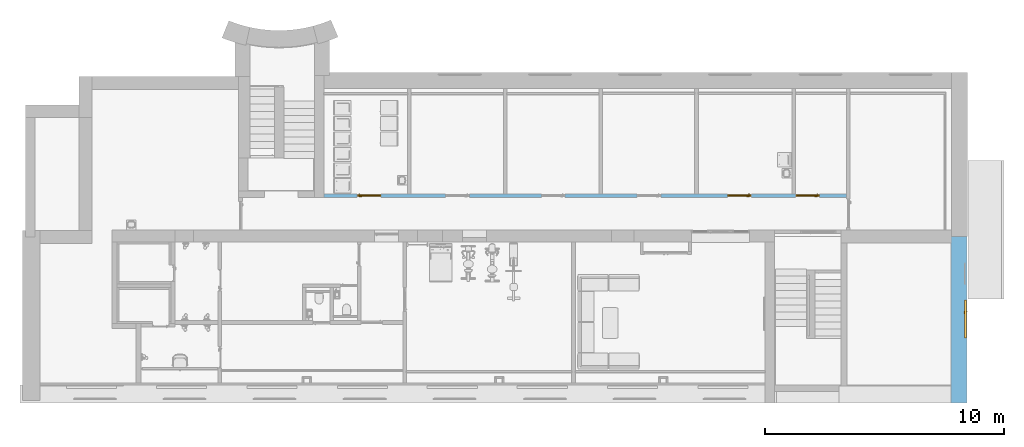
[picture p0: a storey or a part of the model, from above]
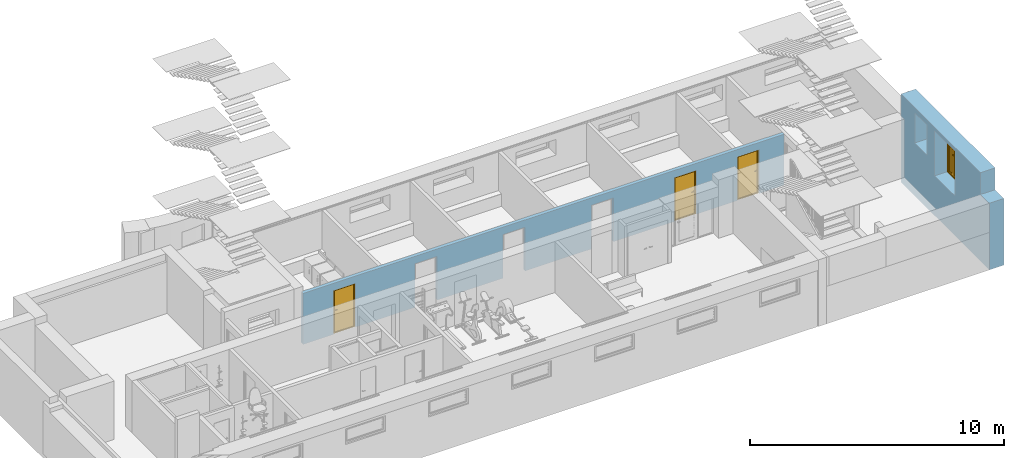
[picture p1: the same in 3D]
Properties of the parts of a building model (IFC2X3), part 1 of 4

# File
Description: ViewDefinition [CoordinationView_V2.0]
File name: 19080
Time: 2020-03-24T19:36:21
Written by: The EXPRESS Data Manager Version 5.02.0100.07 : 28 Aug 2013
Made in: 20180806_1515(x64) - Exporter 19.3.0.0 - Alternate UI 19.3.0.0
Comment: STEP Physical File produced by: The EXPRESS Data Manager Version 5.02.0100.07 : 28 Aug 2013 * Module: EDMstepFileFactory/EDMstandAlone * Creation date: Tue Mar 24 19:36:21 2020 * Host: SA-28 * Database: C:\Users\Evely\AppData\Local\Temp\{456B217A-5B38-47CA-B494-E4B1A39EF6CF}\ifc * Database version: 5507 * Database creation date: Tue Mar 24 19:32:30 2020 * Schema: IFC2X3 * Model: DataRepository.ifc * Model creation date: Tue Mar 24 19:32:31 2020 * Header model: DataRepository.ifc_HeaderModel * Header model creation date: Tue Mar 24 19:32:31 2020 * EDMuser: sdai-user * EDMgroup: sdai-group * License ID and type: 5605 : Permanent license. Expiry date: * EDMstepFileFactory options: 020000

# IfcProject, 19080
LongName: Tulika 37 rekonstrueerimine; Phase: TP

# IfcSite, Default
RefLatitude: 59, 26, 11, 113586; RefLongitude: 24, 45, 9, 290313; RefElevation: 0 mm
Pset_ProductRequirements - Category: Project Information

# IfcBuilding, SMA ARH
LongName: SMA ARH
Pset_BuildingCommon - NumberOfStoreys: 7
Pset_ProductRequirements - Category: Project Information

# IfcBuildingStorey: Level:Level head 1 (7)
In: SMA ARH
Pset_ProductRequirements - Category: Levels
Name | LongName = Pset_AirSideSystemInformation, Name = Pset_ProductRequirements, Name | Elevation (mm)
0 Sokkel | 0 Sokkel | -2800
Sissepääs | Sissepääs | -1270
1 Korrus | 1 Korrus | 0
2 Korrus | 2 Korrus | 3300
3 Korrus | 3 Korrus | 6600
4 Korrus | 4 Korrus | 9910
Katus | Katus | 13000

# IfcSpace: Abiruum 0-28:1304011, 0-28
In: 0 Sokkel
LongName: Abiruum; InteriorOrExteriorSpace: INTERNAL
Pset_AirSideSystemInformation - Name: Abiruum; sets with these values: 2
Pset_SpaceCommon - Reference: Abiruum 0-28

# IfcSpace: Abiruum 0-30:1328334, 0-30
In: 0 Sokkel
LongName: Abiruum; InteriorOrExteriorSpace: INTERNAL
Pset_AirSideSystemInformation - Name: Abiruum; sets with these values: 2
Pset_SpaceCommon - Reference: Abiruum 0-30

# IfcSpace: Administraator 1-1:847130, 1-1
In: 1 Korrus
LongName: Administraator; InteriorOrExteriorSpace: INTERNAL
Pset_AirSideSystemInformation - Name: Administraator; sets with these values: 2
Pset_SpaceCommon - Reference: Administraator 1-1

# IfcSpace: El.kilbiruum 0-21:888839, 0-21
In: 0 Sokkel
LongName: El.kilbiruum; InteriorOrExteriorSpace: INTERNAL
Pset_AirSideSystemInformation - Name: El.kilbiruum; sets with these values: 2
Pset_SpaceCommon - Reference: El.kilbiruum 0-21

# IfcSpace: El.kilp 0-29:1313636, 0-29
In: 0 Sokkel
LongName: El.kilp; InteriorOrExteriorSpace: INTERNAL
Pset_AirSideSystemInformation - Name: El.kilp; sets with these values: 2
Pset_SpaceCommon - Reference: El.kilp 0-29

# IfcSpace: Esik 1-10:847145, 1-10
In: 1 Korrus
LongName: Esik; InteriorOrExteriorSpace: INTERNAL
Pset_AirSideSystemInformation - Name: Esik; sets with these values: 2
Pset_SpaceCommon - Reference: Esik 1-10

# IfcSpace: Esik 1-16:847163, 1-16
In: 1 Korrus
LongName: Esik; InteriorOrExteriorSpace: INTERNAL
Pset_AirSideSystemInformation - Name: Esik; sets with these values: 2
Pset_SpaceCommon - Reference: Esik 1-16

# IfcSpace: Esik 1-18:847178, 1-18
In: 1 Korrus
LongName: Esik; InteriorOrExteriorSpace: INTERNAL
Pset_AirSideSystemInformation - Name: Esik; sets with these values: 2
Pset_SpaceCommon - Reference: Esik 1-18

# IfcSpace: Esik 1-25:847196, 1-25
In: 1 Korrus
LongName: Esik; InteriorOrExteriorSpace: INTERNAL
Pset_AirSideSystemInformation - Name: Esik; sets with these values: 2
Pset_SpaceCommon - Reference: Esik 1-25

# IfcSpace: Esik 1-28:847211, 1-28
In: 1 Korrus
LongName: Esik; InteriorOrExteriorSpace: INTERNAL
Pset_AirSideSystemInformation - Name: Esik; sets with these values: 2
Pset_SpaceCommon - Reference: Esik 1-28

# IfcSpace: Esik 1-32:847223, 1-32
In: 1 Korrus
LongName: Esik; InteriorOrExteriorSpace: INTERNAL
Pset_AirSideSystemInformation - Name: Esik; sets with these values: 2
Pset_SpaceCommon - Reference: Esik 1-32

# IfcSpace: Esik 2-10:856734, 2-10
In: 2 Korrus
LongName: Esik; InteriorOrExteriorSpace: INTERNAL
Pset_AirSideSystemInformation - Name: Esik; sets with these values: 2
Pset_SpaceCommon - Reference: Esik 2-10

# IfcSpace: Esik 2-16:856764, 2-16
In: 2 Korrus
LongName: Esik; InteriorOrExteriorSpace: INTERNAL
Pset_AirSideSystemInformation - Name: Esik; sets with these values: 2
Pset_SpaceCommon - Reference: Esik 2-16

# IfcSpace: Esik 2-18:856779, 2-18
In: 2 Korrus
LongName: Esik; InteriorOrExteriorSpace: INTERNAL
Pset_AirSideSystemInformation - Name: Esik; sets with these values: 2
Pset_SpaceCommon - Reference: Esik 2-18

# IfcSpace: Esik 2-25:856797, 2-25
In: 2 Korrus
LongName: Esik; InteriorOrExteriorSpace: INTERNAL
Pset_AirSideSystemInformation - Name: Esik; sets with these values: 2
Pset_SpaceCommon - Reference: Esik 2-25

# IfcSpace: Esik 2-28:856812, 2-28
In: 2 Korrus
LongName: Esik; InteriorOrExteriorSpace: INTERNAL
Pset_AirSideSystemInformation - Name: Esik; sets with these values: 2
Pset_SpaceCommon - Reference: Esik 2-28

# IfcSpace: Esik 2-3:856827, 2-3
In: 2 Korrus
LongName: Esik; InteriorOrExteriorSpace: INTERNAL
Pset_AirSideSystemInformation - Name: Esik; sets with these values: 2
Pset_SpaceCommon - Reference: Esik 2-3

# IfcSpace: Esik 3-10:867600, 3-10
In: 3 Korrus
LongName: Esik; InteriorOrExteriorSpace: INTERNAL
Pset_AirSideSystemInformation - Name: Esik; sets with these values: 2
Pset_SpaceCommon - Reference: Esik 3-10

# IfcSpace: Esik 3-16:867627, 3-16
In: 3 Korrus
LongName: Esik; InteriorOrExteriorSpace: INTERNAL
Pset_AirSideSystemInformation - Name: Esik; sets with these values: 2
Pset_SpaceCommon - Reference: Esik 3-16

# IfcSpace: Esik 3-18:867639, 3-18
In: 3 Korrus
LongName: Esik; InteriorOrExteriorSpace: INTERNAL
Pset_AirSideSystemInformation - Name: Esik; sets with these values: 2
Pset_SpaceCommon - Reference: Esik 3-18

# IfcSpace: Esik 3-25:867688, 3-25
In: 3 Korrus
LongName: Esik; InteriorOrExteriorSpace: INTERNAL
Pset_AirSideSystemInformation - Name: Esik; sets with these values: 2
Pset_SpaceCommon - Reference: Esik 3-25

# IfcSpace: Esik 3-28:867691, 3-28
In: 3 Korrus
LongName: Esik; InteriorOrExteriorSpace: INTERNAL
Pset_AirSideSystemInformation - Name: Esik; sets with these values: 2
Pset_SpaceCommon - Reference: Esik 3-28

# IfcSpace: Esik 3-3:867551, 3-3
In: 3 Korrus
LongName: Esik; InteriorOrExteriorSpace: INTERNAL
Pset_AirSideSystemInformation - Name: Esik; sets with these values: 2
Pset_SpaceCommon - Reference: Esik 3-3

# IfcSpace: Esik 4-10:867950, 4-10
In: 4 Korrus
LongName: Esik; InteriorOrExteriorSpace: INTERNAL
Pset_AirSideSystemInformation - Name: Esik; sets with these values: 2
Pset_SpaceCommon - Reference: Esik 4-10

# IfcSpace: Esik 4-16:867977, 4-16
In: 4 Korrus
LongName: Esik; InteriorOrExteriorSpace: INTERNAL
Pset_AirSideSystemInformation - Name: Esik; sets with these values: 2
Pset_SpaceCommon - Reference: Esik 4-16

# IfcSpace: Esik 4-18:867989, 4-18
In: 4 Korrus
LongName: Esik; InteriorOrExteriorSpace: INTERNAL
Pset_AirSideSystemInformation - Name: Esik; sets with these values: 2
Pset_SpaceCommon - Reference: Esik 4-18

# IfcSpace: Esik 4-25:868047, 4-25
In: 4 Korrus
LongName: Esik; InteriorOrExteriorSpace: INTERNAL
Pset_AirSideSystemInformation - Name: Esik; sets with these values: 2
Pset_SpaceCommon - Reference: Esik 4-25

# IfcSpace: Esik 4-27:868059, 4-27
In: 4 Korrus
LongName: Esik; InteriorOrExteriorSpace: INTERNAL
Pset_AirSideSystemInformation - Name: Esik; sets with these values: 2
Pset_SpaceCommon - Reference: Esik 4-27

# IfcSpace: Esik 4-3:867819, 4-3
In: 4 Korrus
LongName: Esik; InteriorOrExteriorSpace: INTERNAL
Pset_AirSideSystemInformation - Name: Esik; sets with these values: 2
Pset_SpaceCommon - Reference: Esik 4-3

# IfcSpace: Fuajee 1-3:847124, 1-3
In: 1 Korrus
LongName: Fuajee; InteriorOrExteriorSpace: INTERNAL
Pset_AirSideSystemInformation - Name: Fuajee; sets with these values: 2
Pset_SpaceCommon - Reference: Fuajee 1-3

# IfcSpace: Jõusaal 0-3:888782, 0-3
In: 0 Sokkel
LongName: Jõusaal; InteriorOrExteriorSpace: INTERNAL
Pset_AirSideSystemInformation - Name: Jõusaal; sets with these values: 2
Pset_SpaceCommon - Reference: Jõusaal 0-3

# IfcSpace: Kor.v 0-20:888836, 0-20
In: 0 Sokkel
LongName: Kor.v; InteriorOrExteriorSpace: INTERNAL
Pset_AirSideSystemInformation - Name: Kor.v; sets with these values: 2
Pset_SpaceCommon - Reference: Kor.v 0-20

# IfcSpace: Kor.v 1-21:847190, 1-21
In: 1 Korrus
LongName: Kor.v; InteriorOrExteriorSpace: INTERNAL
Pset_AirSideSystemInformation - Name: Kor.v; sets with these values: 2
Pset_SpaceCommon - Reference: Kor.v 1-21

# IfcSpace: Kor.v 2-21:856791, 2-21
In: 2 Korrus
LongName: Kor.v; InteriorOrExteriorSpace: INTERNAL
Pset_AirSideSystemInformation - Name: Kor.v; sets with these values: 2
Pset_SpaceCommon - Reference: Kor.v 2-21

# IfcSpace: Kor.v 3-21:867657, 3-21
In: 3 Korrus
LongName: Kor.v; InteriorOrExteriorSpace: INTERNAL
Pset_AirSideSystemInformation - Name: Kor.v; sets with these values: 2
Pset_SpaceCommon - Reference: Kor.v 3-21

# IfcSpace: Kor.v 4-21:868010, 4-21
In: 4 Korrus
LongName: Kor.v; InteriorOrExteriorSpace: INTERNAL
Pset_AirSideSystemInformation - Name: Kor.v; sets with these values: 2
Pset_SpaceCommon - Reference: Kor.v 4-21

# IfcSpace: Koridor 0-1:887768, 0-1
In: 0 Sokkel
LongName: Koridor; InteriorOrExteriorSpace: INTERNAL
Pset_AirSideSystemInformation - Name: Koridor; sets with these values: 2
Pset_SpaceCommon - Reference: Koridor 0-1

# IfcSpace: Koridor 0-4:888785, 0-4
In: 0 Sokkel
LongName: Koridor; InteriorOrExteriorSpace: INTERNAL
Pset_AirSideSystemInformation - Name: Koridor; sets with these values: 2
Pset_SpaceCommon - Reference: Koridor 0-4

# IfcSpace: Koridor 1-5:847139, 1-5
In: 1 Korrus
LongName: Koridor; InteriorOrExteriorSpace: INTERNAL
Pset_AirSideSystemInformation - Name: Koridor; sets with these values: 2
Pset_SpaceCommon - Reference: Koridor 1-5

# IfcSpace: Koridor 2-5:856731, 2-5
In: 2 Korrus
LongName: Koridor; InteriorOrExteriorSpace: INTERNAL
Pset_AirSideSystemInformation - Name: Koridor; sets with these values: 2
Pset_SpaceCommon - Reference: Koridor 2-5

# IfcSpace: Koridor 3-5:867579, 3-5
In: 3 Korrus
LongName: Koridor; InteriorOrExteriorSpace: INTERNAL
Pset_AirSideSystemInformation - Name: Koridor; sets with these values: 2
Pset_SpaceCommon - Reference: Koridor 3-5

# IfcSpace: Koridor 4-5:867831, 4-5
In: 4 Korrus
LongName: Koridor; InteriorOrExteriorSpace: INTERNAL
Pset_AirSideSystemInformation - Name: Koridor; sets with these values: 2
Pset_SpaceCommon - Reference: Koridor 4-5

# IfcSpace: Ladu 0-19:888833, 0-19
In: 0 Sokkel
LongName: Ladu; InteriorOrExteriorSpace: INTERNAL
Pset_AirSideSystemInformation - Name: Ladu; sets with these values: 2
Pset_SpaceCommon - Reference: Ladu 0-19

# IfcSpace: Musta pesu ladu 0-17:888827, 0-17
In: 0 Sokkel
LongName: Musta pesu ladu; InteriorOrExteriorSpace: INTERNAL
Pset_AirSideSystemInformation - Name: Musta pesu ladu; sets with these values: 2
Pset_SpaceCommon - Reference: Musta pesu ladu 0-17

# IfcSpace: Pesemisruum 0-11:888809, 0-11
In: 0 Sokkel
LongName: Pesemisruum; InteriorOrExteriorSpace: INTERNAL
Pset_AirSideSystemInformation - Name: Pesemisruum; sets with these values: 2
Pset_SpaceCommon - Reference: Pesemisruum 0-11

# IfcSpace: Pesemisruum 0-8:888800, 0-8
In: 0 Sokkel
LongName: Pesemisruum; InteriorOrExteriorSpace: INTERNAL
Pset_AirSideSystemInformation - Name: Pesemisruum; sets with these values: 2
Pset_SpaceCommon - Reference: Pesemisruum 0-8

# IfcSpace: Pesupesemisruum 0-16:888824, 0-16
In: 0 Sokkel
LongName: Pesupesemisruum; InteriorOrExteriorSpace: INTERNAL
Pset_AirSideSystemInformation - Name: Pesupesemisruum; sets with these values: 2
Pset_SpaceCommon - Reference: Pesupesemisruum 0-16

# IfcSpace: Puhkeruum 0-2:888776, 0-2
In: 0 Sokkel
LongName: Puhkeruum; InteriorOrExteriorSpace: INTERNAL
Pset_AirSideSystemInformation - Name: Puhkeruum; sets with these values: 2
Pset_SpaceCommon - Reference: Puhkeruum 0-2

# IfcSpace: Puhta pesu ladu 0-18:888830, 0-18
In: 0 Sokkel
LongName: Puhta pesu ladu; InteriorOrExteriorSpace: INTERNAL
Pset_AirSideSystemInformation - Name: Puhta pesu ladu; sets with these values: 2
Pset_SpaceCommon - Reference: Puhta pesu ladu 0-18

# IfcSpace: Riietusruum 0-12:888812, 0-12
In: 0 Sokkel
LongName: Riietusruum; InteriorOrExteriorSpace: INTERNAL
Pset_AirSideSystemInformation - Name: Riietusruum; sets with these values: 2
Pset_SpaceCommon - Reference: Riietusruum 0-12

# IfcSpace: Riietusruum 0-7:888797, 0-7
In: 0 Sokkel
LongName: Riietusruum; InteriorOrExteriorSpace: INTERNAL
Pset_AirSideSystemInformation - Name: Riietusruum; sets with these values: 2
Pset_SpaceCommon - Reference: Riietusruum 0-7

# IfcSpace: Saun 0-10:888806, 0-10
In: 0 Sokkel
LongName: Saun; InteriorOrExteriorSpace: INTERNAL
Pset_AirSideSystemInformation - Name: Saun; sets with these values: 2
Pset_SpaceCommon - Reference: Saun 0-10

# IfcSpace: Saun 0-9:888803, 0-9
In: 0 Sokkel
LongName: Saun; InteriorOrExteriorSpace: INTERNAL
Pset_AirSideSystemInformation - Name: Saun; sets with these values: 2
Pset_SpaceCommon - Reference: Saun 0-9

# IfcSpace: Tehniline ruum 0-13:888815, 0-13
In: 0 Sokkel
LongName: Tehniline ruum; InteriorOrExteriorSpace: INTERNAL
Pset_AirSideSystemInformation - Name: Tehniline ruum; sets with these values: 2
Pset_SpaceCommon - Reference: Tehniline ruum 0-13

# IfcSpace: Tehniline ruum 0-14:888818, 0-14
In: 0 Sokkel
LongName: Tehniline ruum; InteriorOrExteriorSpace: INTERNAL
Pset_AirSideSystemInformation - Name: Tehniline ruum; sets with these values: 2
Pset_SpaceCommon - Reference: Tehniline ruum 0-14

# IfcSpace: Tehniline ruum 0-22:888842, 0-22
In: 0 Sokkel
LongName: Tehniline ruum; InteriorOrExteriorSpace: INTERNAL
Pset_AirSideSystemInformation - Name: Tehniline ruum; sets with these values: 2
Pset_SpaceCommon - Reference: Tehniline ruum 0-22

# IfcSpace: Trepikoda 1 0-23:888845, 0-23
In: 0 Sokkel
LongName: Trepikoda 1; InteriorOrExteriorSpace: INTERNAL
Pset_AirSideSystemInformation - Name: Trepikoda 1; sets with these values: 2
Pset_SpaceCommon - Reference: Trepikoda 1 0-23

# IfcSpace: Trepikoda 1 1-4:847127, 1-4
In: 1 Korrus
LongName: Trepikoda 1; InteriorOrExteriorSpace: INTERNAL
Pset_AirSideSystemInformation - Name: Trepikoda 1; sets with these values: 2
Pset_SpaceCommon - Reference: Trepikoda 1 1-4

# IfcSpace: Trepikoda 1 2-4:856693, 2-4
In: 2 Korrus
LongName: Trepikoda 1; InteriorOrExteriorSpace: INTERNAL
Pset_AirSideSystemInformation - Name: Trepikoda 1; sets with these values: 2
Pset_SpaceCommon - Reference: Trepikoda 1 2-4

# IfcSpace: Trepikoda 1 3-4:867554, 3-4
In: 3 Korrus
LongName: Trepikoda 1; InteriorOrExteriorSpace: INTERNAL
Pset_AirSideSystemInformation - Name: Trepikoda 1; sets with these values: 2
Pset_SpaceCommon - Reference: Trepikoda 1 3-4

# IfcSpace: Trepikoda 1 4-4:867825, 4-4
In: 4 Korrus
LongName: Trepikoda 1; InteriorOrExteriorSpace: INTERNAL
Pset_AirSideSystemInformation - Name: Trepikoda 1; sets with these values: 2
Pset_SpaceCommon - Reference: Trepikoda 1 4-4

# IfcSpace: Trepikoda 2 0-15:888821, 0-15
In: 0 Sokkel
LongName: Trepikoda 2; InteriorOrExteriorSpace: INTERNAL
Pset_AirSideSystemInformation - Name: Trepikoda 2; sets with these values: 2
Pset_SpaceCommon - Reference: Trepikoda 2 0-15

# IfcSpace: Trepikoda 2 1-35:847193, 1-35
In: 1 Korrus
LongName: Trepikoda 2; InteriorOrExteriorSpace: INTERNAL
Pset_AirSideSystemInformation - Name: Trepikoda 2; sets with these values: 2
Pset_SpaceCommon - Reference: Trepikoda 2 1-35

# IfcSpace: Trepikoda 2 2-32:856794, 2-32
In: 2 Korrus
LongName: Trepikoda 2; InteriorOrExteriorSpace: INTERNAL
Pset_AirSideSystemInformation - Name: Trepikoda 2; sets with these values: 2
Pset_SpaceCommon - Reference: Trepikoda 2 2-32

# IfcSpace: Trepikoda 2 3-32:867660, 3-32
In: 3 Korrus
LongName: Trepikoda 2; InteriorOrExteriorSpace: INTERNAL
Pset_AirSideSystemInformation - Name: Trepikoda 2; sets with these values: 2
Pset_SpaceCommon - Reference: Trepikoda 2 3-32

# IfcSpace: Trepikoda 2 4-32:868016, 4-32
In: 4 Korrus
LongName: Trepikoda 2; InteriorOrExteriorSpace: INTERNAL
Pset_AirSideSystemInformation - Name: Trepikoda 2; sets with these values: 2
Pset_SpaceCommon - Reference: Trepikoda 2 4-32

# IfcSpace: Tuba 1-12:847166, 1-12
In: 1 Korrus
LongName: Tuba; InteriorOrExteriorSpace: INTERNAL
Pset_AirSideSystemInformation - Name: Tuba; sets with these values: 2
Pset_SpaceCommon - Reference: Tuba 1-12

# IfcSpace: Tuba 1-13:847169, 1-13
In: 1 Korrus
LongName: Tuba; InteriorOrExteriorSpace: INTERNAL
Pset_AirSideSystemInformation - Name: Tuba; sets with these values: 2
Pset_SpaceCommon - Reference: Tuba 1-13

# IfcSpace: Tuba 1-14:847172, 1-14
In: 1 Korrus
LongName: Tuba; InteriorOrExteriorSpace: INTERNAL
Pset_AirSideSystemInformation - Name: Tuba; sets with these values: 2
Pset_SpaceCommon - Reference: Tuba 1-14

# IfcSpace: Tuba 1-15:847181, 1-15
In: 1 Korrus
LongName: Tuba; InteriorOrExteriorSpace: INTERNAL
Pset_AirSideSystemInformation - Name: Tuba; sets with these values: 2
Pset_SpaceCommon - Reference: Tuba 1-15

# IfcSpace: Tuba 1-20/1:847184, 1-20/1
In: 1 Korrus
LongName: Tuba; InteriorOrExteriorSpace: INTERNAL
Pset_AirSideSystemInformation - Name: Tuba; sets with these values: 2
Pset_SpaceCommon - Reference: Tuba 1-20/1

# IfcSpace: Tuba 1-20/2:858602, 1-20/2
In: 1 Korrus
LongName: Tuba; InteriorOrExteriorSpace: INTERNAL
Pset_AirSideSystemInformation - Name: Tuba; sets with these values: 2
Pset_SpaceCommon - Reference: Tuba 1-20/2

# IfcSpace: Tuba 1-22:847199, 1-22
In: 1 Korrus
LongName: Tuba; InteriorOrExteriorSpace: INTERNAL
Pset_AirSideSystemInformation - Name: Tuba; sets with these values: 2
Pset_SpaceCommon - Reference: Tuba 1-22

# IfcSpace: Tuba 1-23:847202, 1-23
In: 1 Korrus
LongName: Tuba; InteriorOrExteriorSpace: INTERNAL
Pset_AirSideSystemInformation - Name: Tuba; sets with these values: 2
Pset_SpaceCommon - Reference: Tuba 1-23

# IfcSpace: Tuba 1-24:847205, 1-24
In: 1 Korrus
LongName: Tuba; InteriorOrExteriorSpace: INTERNAL
Pset_AirSideSystemInformation - Name: Tuba; sets with these values: 2
Pset_SpaceCommon - Reference: Tuba 1-24

# IfcSpace: Tuba 1-29:847217, 1-29
In: 1 Korrus
LongName: Tuba; InteriorOrExteriorSpace: INTERNAL
Pset_AirSideSystemInformation - Name: Tuba; sets with these values: 2
Pset_SpaceCommon - Reference: Tuba 1-29

# IfcSpace: Tuba 1-30:847220, 1-30
In: 1 Korrus
LongName: Tuba; InteriorOrExteriorSpace: INTERNAL
Pset_AirSideSystemInformation - Name: Tuba; sets with these values: 2
Pset_SpaceCommon - Reference: Tuba 1-30

# IfcSpace: Tuba 1-31:847226, 1-31
In: 1 Korrus
LongName: Tuba; InteriorOrExteriorSpace: INTERNAL
Pset_AirSideSystemInformation - Name: Tuba; sets with these values: 2
Pset_SpaceCommon - Reference: Tuba 1-31

# IfcSpace: Tuba 1-33:847229, 1-33
In: 1 Korrus
LongName: Tuba; InteriorOrExteriorSpace: INTERNAL
Pset_AirSideSystemInformation - Name: Tuba; sets with these values: 2
Pset_SpaceCommon - Reference: Tuba 1-33

# IfcSpace: Tuba 1-6:847148, 1-6
In: 1 Korrus
LongName: Tuba; InteriorOrExteriorSpace: INTERNAL
Pset_AirSideSystemInformation - Name: Tuba; sets with these values: 2
Pset_SpaceCommon - Reference: Tuba 1-6

# IfcSpace: Tuba 1-7:847151, 1-7
In: 1 Korrus
LongName: Tuba; InteriorOrExteriorSpace: INTERNAL
Pset_AirSideSystemInformation - Name: Tuba; sets with these values: 2
Pset_SpaceCommon - Reference: Tuba 1-7

# IfcSpace: Tuba 1-8:847154, 1-8
In: 1 Korrus
LongName: Tuba; InteriorOrExteriorSpace: INTERNAL
Pset_AirSideSystemInformation - Name: Tuba; sets with these values: 2
Pset_SpaceCommon - Reference: Tuba 1-8

# IfcSpace: Tuba 1-9:847157, 1-9
In: 1 Korrus
LongName: Tuba; InteriorOrExteriorSpace: INTERNAL
Pset_AirSideSystemInformation - Name: Tuba; sets with these values: 2
Pset_SpaceCommon - Reference: Tuba 1-9

# IfcSpace: Tuba 2-12:856767, 2-12
In: 2 Korrus
LongName: Tuba; InteriorOrExteriorSpace: INTERNAL
Pset_AirSideSystemInformation - Name: Tuba; sets with these values: 2
Pset_SpaceCommon - Reference: Tuba 2-12

# IfcSpace: Tuba 2-13:856770, 2-13
In: 2 Korrus
LongName: Tuba; InteriorOrExteriorSpace: INTERNAL
Pset_AirSideSystemInformation - Name: Tuba; sets with these values: 2
Pset_SpaceCommon - Reference: Tuba 2-13

# IfcSpace: Tuba 2-14:856773, 2-14
In: 2 Korrus
LongName: Tuba; InteriorOrExteriorSpace: INTERNAL
Pset_AirSideSystemInformation - Name: Tuba; sets with these values: 2
Pset_SpaceCommon - Reference: Tuba 2-14

# IfcSpace: Tuba 2-15:856782, 2-15
In: 2 Korrus
LongName: Tuba; InteriorOrExteriorSpace: INTERNAL
Pset_AirSideSystemInformation - Name: Tuba; sets with these values: 2
Pset_SpaceCommon - Reference: Tuba 2-15

# IfcSpace: Tuba 2-1:856836, 2-1
In: 2 Korrus
LongName: Tuba; InteriorOrExteriorSpace: INTERNAL
Pset_AirSideSystemInformation - Name: Tuba; sets with these values: 2
Pset_SpaceCommon - Reference: Tuba 2-1

# IfcSpace: Tuba 2-20/1:856785, 2-20/1
In: 2 Korrus
LongName: Tuba; InteriorOrExteriorSpace: INTERNAL
Pset_AirSideSystemInformation - Name: Tuba; sets with these values: 2
Pset_SpaceCommon - Reference: Tuba 2-20/1

# IfcSpace: Tuba 2-20/2:860101, 2-20/2
In: 2 Korrus
LongName: Tuba; InteriorOrExteriorSpace: INTERNAL
Pset_AirSideSystemInformation - Name: Tuba; sets with these values: 2
Pset_SpaceCommon - Reference: Tuba 2-20/2

# IfcSpace: Tuba 2-22:856800, 2-22
In: 2 Korrus
LongName: Tuba; InteriorOrExteriorSpace: INTERNAL
Pset_AirSideSystemInformation - Name: Tuba; sets with these values: 2
Pset_SpaceCommon - Reference: Tuba 2-22

# IfcSpace: Tuba 2-23:856803, 2-23
In: 2 Korrus
LongName: Tuba; InteriorOrExteriorSpace: INTERNAL
Pset_AirSideSystemInformation - Name: Tuba; sets with these values: 2
Pset_SpaceCommon - Reference: Tuba 2-23

# IfcSpace: Tuba 2-24:856806, 2-24
In: 2 Korrus
LongName: Tuba; InteriorOrExteriorSpace: INTERNAL
Pset_AirSideSystemInformation - Name: Tuba; sets with these values: 2
Pset_SpaceCommon - Reference: Tuba 2-24

# IfcSpace: Tuba 2-29:856818, 2-29
In: 2 Korrus
LongName: Tuba; InteriorOrExteriorSpace: INTERNAL
Pset_AirSideSystemInformation - Name: Tuba; sets with these values: 2
Pset_SpaceCommon - Reference: Tuba 2-29

# IfcSpace: Tuba 2-30:856821, 2-30
In: 2 Korrus
LongName: Tuba; InteriorOrExteriorSpace: INTERNAL
Pset_AirSideSystemInformation - Name: Tuba; sets with these values: 2
Pset_SpaceCommon - Reference: Tuba 2-30

# IfcSpace: Tuba 2-31/1:856830, 2-31/1
In: 2 Korrus
LongName: Tuba; InteriorOrExteriorSpace: INTERNAL
Pset_AirSideSystemInformation - Name: Tuba; sets with these values: 2
Pset_SpaceCommon - Reference: Tuba 2-31/1

# IfcSpace: Tuba 2-31:856824, 2-31
In: 2 Korrus
LongName: Tuba; InteriorOrExteriorSpace: INTERNAL
Pset_AirSideSystemInformation - Name: Tuba; sets with these values: 2
Pset_SpaceCommon - Reference: Tuba 2-31

# IfcSpace: Tuba 2-6:856737, 2-6
In: 2 Korrus
LongName: Tuba; InteriorOrExteriorSpace: INTERNAL
Pset_AirSideSystemInformation - Name: Tuba; sets with these values: 2
Pset_SpaceCommon - Reference: Tuba 2-6

# IfcSpace: Tuba 2-7:856740, 2-7
In: 2 Korrus
LongName: Tuba; InteriorOrExteriorSpace: INTERNAL
Pset_AirSideSystemInformation - Name: Tuba; sets with these values: 2
Pset_SpaceCommon - Reference: Tuba 2-7

# IfcSpace: Tuba 2-8:856743, 2-8
In: 2 Korrus
LongName: Tuba; InteriorOrExteriorSpace: INTERNAL
Pset_AirSideSystemInformation - Name: Tuba; sets with these values: 2
Pset_SpaceCommon - Reference: Tuba 2-8

# IfcSpace: Tuba 2-9:856758, 2-9
In: 2 Korrus
LongName: Tuba; InteriorOrExteriorSpace: INTERNAL
Pset_AirSideSystemInformation - Name: Tuba; sets with these values: 2
Pset_SpaceCommon - Reference: Tuba 2-9

# IfcSpace: Tuba 3-12:867612, 3-12
In: 3 Korrus
LongName: Tuba; InteriorOrExteriorSpace: INTERNAL
Pset_AirSideSystemInformation - Name: Tuba; sets with these values: 2
Pset_SpaceCommon - Reference: Tuba 3-12

# IfcSpace: Tuba 3-13:867615, 3-13
In: 3 Korrus
LongName: Tuba; InteriorOrExteriorSpace: INTERNAL
Pset_AirSideSystemInformation - Name: Tuba; sets with these values: 2
Pset_SpaceCommon - Reference: Tuba 3-13

# IfcSpace: Tuba 3-14:867618, 3-14
In: 3 Korrus
LongName: Tuba; InteriorOrExteriorSpace: INTERNAL
Pset_AirSideSystemInformation - Name: Tuba; sets with these values: 2
Pset_SpaceCommon - Reference: Tuba 3-14

# IfcSpace: Tuba 3-15:867621, 3-15
In: 3 Korrus
LongName: Tuba; InteriorOrExteriorSpace: INTERNAL
Pset_AirSideSystemInformation - Name: Tuba; sets with these values: 2
Pset_SpaceCommon - Reference: Tuba 3-15

# IfcSpace: Tuba 3-1:867539, 3-1
In: 3 Korrus
LongName: Tuba; InteriorOrExteriorSpace: INTERNAL
Pset_AirSideSystemInformation - Name: Tuba; sets with these values: 2
Pset_SpaceCommon - Reference: Tuba 3-1

# IfcSpace: Tuba 3-20/1:867651, 3-20/1
In: 3 Korrus
LongName: Tuba; InteriorOrExteriorSpace: INTERNAL
Pset_AirSideSystemInformation - Name: Tuba; sets with these values: 2
Pset_SpaceCommon - Reference: Tuba 3-20/1

# IfcSpace: Tuba 3-20/2:867654, 3-20/2
In: 3 Korrus
LongName: Tuba; InteriorOrExteriorSpace: INTERNAL
Pset_AirSideSystemInformation - Name: Tuba; sets with these values: 2
Pset_SpaceCommon - Reference: Tuba 3-20/2

# IfcSpace: Tuba 3-22:867670, 3-22
In: 3 Korrus
LongName: Tuba; InteriorOrExteriorSpace: INTERNAL
Pset_AirSideSystemInformation - Name: Tuba; sets with these values: 2
Pset_SpaceCommon - Reference: Tuba 3-22

# IfcSpace: Tuba 3-23:867673, 3-23
In: 3 Korrus
LongName: Tuba; InteriorOrExteriorSpace: INTERNAL
Pset_AirSideSystemInformation - Name: Tuba; sets with these values: 2
Pset_SpaceCommon - Reference: Tuba 3-23

# IfcSpace: Tuba 3-24:867676, 3-24
In: 3 Korrus
LongName: Tuba; InteriorOrExteriorSpace: INTERNAL
Pset_AirSideSystemInformation - Name: Tuba; sets with these values: 2
Pset_SpaceCommon - Reference: Tuba 3-24

# IfcSpace: Tuba 3-29:867715, 3-29
In: 3 Korrus
LongName: Tuba; InteriorOrExteriorSpace: INTERNAL
Pset_AirSideSystemInformation - Name: Tuba; sets with these values: 2
Pset_SpaceCommon - Reference: Tuba 3-29

# IfcSpace: Tuba 3-30:867718, 3-30
In: 3 Korrus
LongName: Tuba; InteriorOrExteriorSpace: INTERNAL
Pset_AirSideSystemInformation - Name: Tuba; sets with these values: 2
Pset_SpaceCommon - Reference: Tuba 3-30

# IfcSpace: Tuba 3-31/1:867724, 3-31/1
In: 3 Korrus
LongName: Tuba; InteriorOrExteriorSpace: INTERNAL
Pset_AirSideSystemInformation - Name: Tuba; sets with these values: 2
Pset_SpaceCommon - Reference: Tuba 3-31/1

# IfcSpace: Tuba 3-31:867721, 3-31
In: 3 Korrus
LongName: Tuba; InteriorOrExteriorSpace: INTERNAL
Pset_AirSideSystemInformation - Name: Tuba; sets with these values: 2
Pset_SpaceCommon - Reference: Tuba 3-31

# IfcSpace: Tuba 3-6:867585, 3-6
In: 3 Korrus
LongName: Tuba; InteriorOrExteriorSpace: INTERNAL
Pset_AirSideSystemInformation - Name: Tuba; sets with these values: 2
Pset_SpaceCommon - Reference: Tuba 3-6

# IfcSpace: Tuba 3-7:867588, 3-7
In: 3 Korrus
LongName: Tuba; InteriorOrExteriorSpace: INTERNAL
Pset_AirSideSystemInformation - Name: Tuba; sets with these values: 2
Pset_SpaceCommon - Reference: Tuba 3-7

# IfcSpace: Tuba 3-8:867591, 3-8
In: 3 Korrus
LongName: Tuba; InteriorOrExteriorSpace: INTERNAL
Pset_AirSideSystemInformation - Name: Tuba; sets with these values: 2
Pset_SpaceCommon - Reference: Tuba 3-8

# IfcSpace: Tuba 3-9:867594, 3-9
In: 3 Korrus
LongName: Tuba; InteriorOrExteriorSpace: INTERNAL
Pset_AirSideSystemInformation - Name: Tuba; sets with these values: 2
Pset_SpaceCommon - Reference: Tuba 3-9

# IfcSpace: Tuba 4-12:867962, 4-12
In: 4 Korrus
LongName: Tuba; InteriorOrExteriorSpace: INTERNAL
Pset_AirSideSystemInformation - Name: Tuba; sets with these values: 2
Pset_SpaceCommon - Reference: Tuba 4-12

# IfcSpace: Tuba 4-13:867965, 4-13
In: 4 Korrus
LongName: Tuba; InteriorOrExteriorSpace: INTERNAL
Pset_AirSideSystemInformation - Name: Tuba; sets with these values: 2
Pset_SpaceCommon - Reference: Tuba 4-13

# IfcSpace: Tuba 4-14:867968, 4-14
In: 4 Korrus
LongName: Tuba; InteriorOrExteriorSpace: INTERNAL
Pset_AirSideSystemInformation - Name: Tuba; sets with these values: 2
Pset_SpaceCommon - Reference: Tuba 4-14

# IfcSpace: Tuba 4-15:867971, 4-15
In: 4 Korrus
LongName: Tuba; InteriorOrExteriorSpace: INTERNAL
Pset_AirSideSystemInformation - Name: Tuba; sets with these values: 2
Pset_SpaceCommon - Reference: Tuba 4-15

# IfcSpace: Tuba 4-1:867802, 4-1
In: 4 Korrus
LongName: Tuba; InteriorOrExteriorSpace: INTERNAL
Pset_AirSideSystemInformation - Name: Tuba; sets with these values: 2
Pset_SpaceCommon - Reference: Tuba 4-1

# IfcSpace: Tuba 4-20/1:868001, 4-20/1
In: 4 Korrus
LongName: Tuba; InteriorOrExteriorSpace: INTERNAL
Pset_AirSideSystemInformation - Name: Tuba; sets with these values: 2
Pset_SpaceCommon - Reference: Tuba 4-20/1

# IfcSpace: Tuba 4-20/2:868004, 4-20/2
In: 4 Korrus
LongName: Tuba; InteriorOrExteriorSpace: INTERNAL
Pset_AirSideSystemInformation - Name: Tuba; sets with these values: 2
Pset_SpaceCommon - Reference: Tuba 4-20/2

# IfcSpace: Tuba 4-22:868030, 4-22
In: 4 Korrus
LongName: Tuba; InteriorOrExteriorSpace: INTERNAL
Pset_AirSideSystemInformation - Name: Tuba; sets with these values: 2
Pset_SpaceCommon - Reference: Tuba 4-22

# IfcSpace: Tuba 4-23:868038, 4-23
In: 4 Korrus
LongName: Tuba; InteriorOrExteriorSpace: INTERNAL
Pset_AirSideSystemInformation - Name: Tuba; sets with these values: 2
Pset_SpaceCommon - Reference: Tuba 4-23

# IfcSpace: Tuba 4-24:868041, 4-24
In: 4 Korrus
LongName: Tuba; InteriorOrExteriorSpace: INTERNAL
Pset_AirSideSystemInformation - Name: Tuba; sets with these values: 2
Pset_SpaceCommon - Reference: Tuba 4-24

# IfcSpace: Tuba 4-29:868071, 4-29
In: 4 Korrus
LongName: Tuba; InteriorOrExteriorSpace: INTERNAL
Pset_AirSideSystemInformation - Name: Tuba; sets with these values: 2
Pset_SpaceCommon - Reference: Tuba 4-29

# IfcSpace: Tuba 4-30:868074, 4-30
In: 4 Korrus
LongName: Tuba; InteriorOrExteriorSpace: INTERNAL
Pset_AirSideSystemInformation - Name: Tuba; sets with these values: 2
Pset_SpaceCommon - Reference: Tuba 4-30

# IfcSpace: Tuba 4-31/1:868080, 4-31/1
In: 4 Korrus
LongName: Tuba; InteriorOrExteriorSpace: INTERNAL
Pset_AirSideSystemInformation - Name: Tuba; sets with these values: 2
Pset_SpaceCommon - Reference: Tuba 4-31/1

# IfcSpace: Tuba 4-31:868077, 4-31
In: 4 Korrus
LongName: Tuba; InteriorOrExteriorSpace: INTERNAL
Pset_AirSideSystemInformation - Name: Tuba; sets with these values: 2
Pset_SpaceCommon - Reference: Tuba 4-31

# IfcSpace: Tuba 4-6:867837, 4-6
In: 4 Korrus
LongName: Tuba; InteriorOrExteriorSpace: INTERNAL
Pset_AirSideSystemInformation - Name: Tuba; sets with these values: 2
Pset_SpaceCommon - Reference: Tuba 4-6

# IfcSpace: Tuba 4-7:867840, 4-7
In: 4 Korrus
LongName: Tuba; InteriorOrExteriorSpace: INTERNAL
Pset_AirSideSystemInformation - Name: Tuba; sets with these values: 2
Pset_SpaceCommon - Reference: Tuba 4-7

# IfcSpace: Tuba 4-8:867843, 4-8
In: 4 Korrus
LongName: Tuba; InteriorOrExteriorSpace: INTERNAL
Pset_AirSideSystemInformation - Name: Tuba; sets with these values: 2
Pset_SpaceCommon - Reference: Tuba 4-8

# IfcSpace: Tuba 4-9:867846, 4-9
In: 4 Korrus
LongName: Tuba; InteriorOrExteriorSpace: INTERNAL
Pset_AirSideSystemInformation - Name: Tuba; sets with these values: 2
Pset_SpaceCommon - Reference: Tuba 4-9

# IfcSpace: Tuulekoda 1-2:847117, 1-2
In: 1 Korrus
LongName: Tuulekoda; InteriorOrExteriorSpace: INTERNAL
Pset_AirSideSystemInformation - Name: Tuulekoda; sets with these values: 2
Pset_SpaceCommon - Reference: Tuulekoda 1-2

# IfcSpace: Wc 0-26:1040858, 0-26
In: 0 Sokkel
LongName: Wc; InteriorOrExteriorSpace: INTERNAL
Pset_AirSideSystemInformation - Name: Wc; sets with these values: 2
Pset_SpaceCommon - Reference: Wc 0-26

# IfcSpace: Wc 0-27:1040860, 0-27
In: 0 Sokkel
LongName: Wc; InteriorOrExteriorSpace: INTERNAL
Pset_AirSideSystemInformation - Name: Wc; sets with these values: 2
Pset_SpaceCommon - Reference: Wc 0-27

# IfcSpace: Wc 1-11:847160, 1-11
In: 1 Korrus
LongName: Wc; InteriorOrExteriorSpace: INTERNAL
Pset_AirSideSystemInformation - Name: Wc; sets with these values: 2
Pset_SpaceCommon - Reference: Wc 1-11

# IfcSpace: Wc 1-17:847175, 1-17
In: 1 Korrus
LongName: Wc; InteriorOrExteriorSpace: INTERNAL
Pset_AirSideSystemInformation - Name: Wc; sets with these values: 2
Pset_SpaceCommon - Reference: Wc 1-17

# IfcSpace: Wc 1-19:847187, 1-19
In: 1 Korrus
LongName: Wc; InteriorOrExteriorSpace: INTERNAL
Pset_AirSideSystemInformation - Name: Wc; sets with these values: 2
Pset_SpaceCommon - Reference: Wc 1-19

# IfcSpace: Wc 1-26:847208, 1-26
In: 1 Korrus
LongName: Wc; InteriorOrExteriorSpace: INTERNAL
Pset_AirSideSystemInformation - Name: Wc; sets with these values: 2
Pset_SpaceCommon - Reference: Wc 1-26

# IfcSpace: Wc 1-27:847214, 1-27
In: 1 Korrus
LongName: Wc; InteriorOrExteriorSpace: INTERNAL
Pset_AirSideSystemInformation - Name: Wc; sets with these values: 2
Pset_SpaceCommon - Reference: Wc 1-27

# IfcSpace: Wc 1-34:847232, 1-34
In: 1 Korrus
LongName: Wc; InteriorOrExteriorSpace: INTERNAL
Pset_AirSideSystemInformation - Name: Wc; sets with these values: 2
Pset_SpaceCommon - Reference: Wc 1-34

# IfcSpace: Wc 1-37:847142, 1-37
In: 1 Korrus
LongName: Wc; InteriorOrExteriorSpace: INTERNAL
Pset_AirSideSystemInformation - Name: Wc; sets with these values: 2
Pset_SpaceCommon - Reference: Wc 1-37

# IfcSpace: Wc 2-11:856761, 2-11
In: 2 Korrus
LongName: Wc; InteriorOrExteriorSpace: INTERNAL
Pset_AirSideSystemInformation - Name: Wc; sets with these values: 2
Pset_SpaceCommon - Reference: Wc 2-11

# IfcSpace: Wc 2-17:856776, 2-17
In: 2 Korrus
LongName: Wc; InteriorOrExteriorSpace: INTERNAL
Pset_AirSideSystemInformation - Name: Wc; sets with these values: 2
Pset_SpaceCommon - Reference: Wc 2-17

# IfcSpace: Wc 2-19:856788, 2-19
In: 2 Korrus
LongName: Wc; InteriorOrExteriorSpace: INTERNAL
Pset_AirSideSystemInformation - Name: Wc; sets with these values: 2
Pset_SpaceCommon - Reference: Wc 2-19

# IfcSpace: Wc 2-26:856809, 2-26
In: 2 Korrus
LongName: Wc; InteriorOrExteriorSpace: INTERNAL
Pset_AirSideSystemInformation - Name: Wc; sets with these values: 2
Pset_SpaceCommon - Reference: Wc 2-26

# IfcSpace: Wc 2-27:856815, 2-27
In: 2 Korrus
LongName: Wc; InteriorOrExteriorSpace: INTERNAL
Pset_AirSideSystemInformation - Name: Wc; sets with these values: 2
Pset_SpaceCommon - Reference: Wc 2-27

# IfcSpace: Wc 2-2:856833, 2-2
In: 2 Korrus
LongName: Wc; InteriorOrExteriorSpace: INTERNAL
Pset_AirSideSystemInformation - Name: Wc; sets with these values: 2
Pset_SpaceCommon - Reference: Wc 2-2

# IfcSpace: Wc 3-11:867606, 3-11
In: 3 Korrus
LongName: Wc; InteriorOrExteriorSpace: INTERNAL
Pset_AirSideSystemInformation - Name: Wc; sets with these values: 2
Pset_SpaceCommon - Reference: Wc 3-11

# IfcSpace: Wc 3-17:867633, 3-17
In: 3 Korrus
LongName: Wc; InteriorOrExteriorSpace: INTERNAL
Pset_AirSideSystemInformation - Name: Wc; sets with these values: 2
Pset_SpaceCommon - Reference: Wc 3-17

# IfcSpace: Wc 3-19:867645, 3-19
In: 3 Korrus
LongName: Wc; InteriorOrExteriorSpace: INTERNAL
Pset_AirSideSystemInformation - Name: Wc; sets with these values: 2
Pset_SpaceCommon - Reference: Wc 3-19

# IfcSpace: Wc 3-26:867682, 3-26
In: 3 Korrus
LongName: Wc; InteriorOrExteriorSpace: INTERNAL
Pset_AirSideSystemInformation - Name: Wc; sets with these values: 2
Pset_SpaceCommon - Reference: Wc 3-26

# IfcSpace: Wc 3-27:867697, 3-27
In: 3 Korrus
LongName: Wc; InteriorOrExteriorSpace: INTERNAL
Pset_AirSideSystemInformation - Name: Wc; sets with these values: 2
Pset_SpaceCommon - Reference: Wc 3-27

# IfcSpace: Wc 3-2:867548, 3-2
In: 3 Korrus
LongName: Wc; InteriorOrExteriorSpace: INTERNAL
Pset_AirSideSystemInformation - Name: Wc; sets with these values: 2
Pset_SpaceCommon - Reference: Wc 3-2

# IfcSpace: Wc 4-11:867956, 4-11
In: 4 Korrus
LongName: Wc; InteriorOrExteriorSpace: INTERNAL
Pset_AirSideSystemInformation - Name: Wc; sets with these values: 2
Pset_SpaceCommon - Reference: Wc 4-11

# IfcSpace: Wc 4-17:867983, 4-17
In: 4 Korrus
LongName: Wc; InteriorOrExteriorSpace: INTERNAL
Pset_AirSideSystemInformation - Name: Wc; sets with these values: 2
Pset_SpaceCommon - Reference: Wc 4-17

# IfcSpace: Wc 4-19:867995, 4-19
In: 4 Korrus
LongName: Wc; InteriorOrExteriorSpace: INTERNAL
Pset_AirSideSystemInformation - Name: Wc; sets with these values: 2
Pset_SpaceCommon - Reference: Wc 4-19

# IfcSpace: Wc 4-26:868053, 4-26
In: 4 Korrus
LongName: Wc; InteriorOrExteriorSpace: INTERNAL
Pset_AirSideSystemInformation - Name: Wc; sets with these values: 2
Pset_SpaceCommon - Reference: Wc 4-26

# IfcSpace: Wc 4-28:868065, 4-28
In: 4 Korrus
LongName: Wc; InteriorOrExteriorSpace: INTERNAL
Pset_AirSideSystemInformation - Name: Wc; sets with these values: 2
Pset_SpaceCommon - Reference: Wc 4-28

# IfcSpace: Wc 4-2:867813, 4-2
In: 4 Korrus
LongName: Wc; InteriorOrExteriorSpace: INTERNAL
Pset_AirSideSystemInformation - Name: Wc; sets with these values: 2
Pset_SpaceCommon - Reference: Wc 4-2

# IfcBuildingElementProxy: Exercise Bike:Exercise Bike, Exercise Bike:Exercise Bike:922687
In: 0-3
Type - Classification: E1090 Other Equipment (Uniformat); Material: Metal - Chrome
Type - Pset_BuildingElementProxyCommon - Reference: Exercise Bike
Type - Pset_ProductRequirements - Category: Specialty Equipment
Type - Pset_QuantityTakeOff - Reference: Exercise Bike
Material: Metal - Chrome, Plastic - Black
Pset_BuildingElementProxyCommon - sets with these values: 2

# IfcBuildingElementProxy: M_Dryer:595x745x850 (3)
In: 0-16
Type - Material: Metal - Paint Finish - Ivory, Glossy
Type - Pset_BuildingElementProxyCommon - Reference: 595x745x850
Type - Pset_ProductRequirements - Category: Specialty Equipment
Type - Pset_QuantityTakeOff - Reference: 595x745x850
Type - Pset_ProvisionForVoid - Width: 600 mm; Height: 850 mm; Depth: 726 mm
Pset_BuildingElementProxyCommon - sets with these values: 2
Name (M_Dryer:595x745x850:...)
1231806
1231809
1231810

# IfcBuildingElementProxy: M_Washer:595x745x850 (6)
In: 0-16
Type - Material: Metal - Paint Finish - Ivory, Matte
Type - Pset_BuildingElementProxyCommon - Reference: 595x745x850
Type - Pset_ProductRequirements - Category: Specialty Equipment
Type - Pset_QuantityTakeOff - Reference: 595x745x850
Type - Pset_ProvisionForVoid - Width: 600 mm; Height: 850 mm; Depth: 726 mm
Pset_BuildingElementProxyCommon - sets with these values: 2
Name (M_Washer:595x745x850:...)
889782
891253
1207262
1213917
1213918
1217104

# IfcBuildingElementProxy: M_Washer:600 x 600 x 850mm, M_Washer:600 x 600 x 850mm:1214918
In: 0-20
Type - Material: Metal - Paint Finish - Ivory, Matte
Type - Pset_BuildingElementProxyCommon - Reference: 600 x 600 x 850mm
Type - Pset_ProductRequirements - Category: Specialty Equipment
Type - Pset_QuantityTakeOff - Reference: 600 x 600 x 850mm
Type - Pset_ProvisionForVoid - Width: 600 mm; Height: 850 mm; Depth: 585 mm
Pset_BuildingElementProxyCommon - sets with these values: 2

# IfcBuildingElementProxy: Reeper:Reeper, Reeper:Reeper:622283
In: 1-15
Type - Pset_BuildingElementProxyCommon - Reference: Reeper
Type - Pset_ProductRequirements - Category: Generic Models
Type - Pset_QuantityTakeOff - Reference: Reeper
Pset_BuildingElementProxyCommon - sets with these values: 2
Pset_ProvisionForVoid - Width: 500 mm; Height: 500 mm; Depth: 500 mm

# IfcBuildingElementProxy: Rowing_Machine_10106:Rowing_Machine_10106, Rowing_Machine_10106:Rowing_Machine_10106:922688
In: 0-3
Type - Material: Slider
Type - Pset_BuildingElementProxyCommon - Reference: Rowing_Machine_10106
Type - Pset_ProductRequirements - Category: Generic Models
Type - Pset_QuantityTakeOff - Reference: Rowing_Machine_10106
Material: Slider, Casing
Pset_BuildingElementProxyCommon - sets with these values: 2

# IfcBuildingElementProxy: Sony_TV:Sony_TV, Sony_TV:Sony_TV:935220
In: 0-2
Type - Material: base
Type - Pset_BuildingElementProxyCommon - Reference: Sony_TV
Type - Pset_ProductRequirements - Category: Generic Models
Type - Pset_QuantityTakeOff - Reference: Sony_TV
Material: base, Glass, tv, sony, underlining
Pset_BuildingElementProxyCommon - sets with these values: 2

# IfcCurtainWall: Curtain Wall:Curtain Wall SKF-02 (2)
In: 1 Korrus
Type - Pset_CurtainWallCommon - IsExternal: no; Reference: Curtain Wall SKF-02
Type - Pset_ProductRequirements - Category: Walls
Type - Pset_QuantityTakeOff - Reference: Curtain Wall SKF-02
Pset_OpeningElementCommon - Reference: Curtain Wall SKF-02; sets with these values: 2
Name (Curtain Wall:Curtain Wall SKF-02:...)
1027751
1330473

# IfcCurtainWall: Curtain Wall:Curtain Wall SKF-04, Curtain Wall:Curtain Wall SKF-04:1021930
In: 0 Sokkel
Type - Pset_CurtainWallCommon - IsExternal: no; Reference: Curtain Wall SKF-04
Type - Pset_ProductRequirements - Category: Walls
Type - Pset_QuantityTakeOff - Reference: Curtain Wall SKF-04
Pset_OpeningElementCommon - Reference: Curtain Wall SKF-04; sets with these values: 2

# IfcDistributionPort (73)
Description: Flow
Name | FlowDirection
Port_801374 | SINK
Port_816834 | SINK
Port_816834 | SOURCE
Port_819935 | SOURCE
Port_819935 | SINK
Port_828721 | SOURCE
Port_828721 | SINK
Port_828854 | SOURCE
Port_828854 | SINK
Port_839856 | SOURCE
Port_839856 | SINK
Port_843473 | SINK
Port_843473 | SOURCE
Port_849649 | SOURCE
Port_849649 | SINK
Port_849653 | SOURCE
Port_849653 | SINK
Port_849655 | SINK
Port_849655 | SOURCE
Port_849657 | SOURCE
Port_849657 | SINK
Port_849661 | SOURCE
Port_849661 | SINK
Port_866612 | SOURCE
Port_866612 | SINK
Port_866613 | SINK
Port_866613 | SOURCE
Port_866614 | SINK
Port_866614 | SOURCE
Port_866616 | SINK
Port_866616 | SOURCE
Port_866624 | SOURCE
Port_866624 | SINK
Port_866625 | SINK
Port_866625 | SOURCE
Port_866626 | SOURCE
Port_866626 | SINK
Port_866628 | SINK
Port_866628 | SOURCE
2 x Port_893462 | SOURCE
2 x Port_894493 | SOURCE
2 x Port_894641 | SOURCE
2 x Port_894926 | SOURCE
2 x Port_894928 | SOURCE
Port_918148 | SINK
Port_1040856 | SINK
Port_1040856 | SOURCE
Port_1040857 | SINK
Port_1040857 | SOURCE
Port_1040867 | SOURCE
Port_1040868 | SOURCE
2 x Port_1082817 | SOURCE
2 x Port_1082912 | SOURCE
Port_1087120 | SINK
Port_1087120 | SOURCE
Port_1090002 | SOURCE
Port_1090002 | SINK
Port_1090435 | SINK
Port_1090435 | SOURCE
Port_1090476 | SINK
Port_1090476 | SOURCE
Port_1096048 | SOURCE
Port_1096048 | SINK
Port_1101381 | SOURCE
Port_1101381 | SINK
Port_1213923 | SINK

# IfcDoor: SMA_D01, 1-poolne:SU-KL-02 - 900x2100, SMA_D01, 1-poolne:SU-KL-02 - 900x2100:887654
In: 0 Sokkel
Type - ParameterTakesPrecedence: no; Sizeable: no; Material: <Unnamed> (3), EST. Klaas. 3x. Default, EST. Metall. Alumiinium. Värvitud. RAL7023 (Concrete grey) (3)
Type - Pset_ConcreteElementGeneral - FireRating: -
Type - Pset_DoorCommon - IsExternal: no; Reference: SU-KL-02 - 900x2100; FireRating: -; AcousticRating: -
Type - Pset_ProductRequirements - Category: Doors
Type - Pset_QuantityTakeOff - Reference: SU-KL-02 - 900x2100
OverallHeight: 2100 mm; OverallWidth: 900 mm; Material: EST. Metall. Alumiinium. Värvitud. RAL7023 (Concrete grey)

# IfcDoor: SMA_D01, 1-poolne:SU-KL-02 - 900x2100, SMA_D01, 1-poolne:SU-KL-02 - 900x2100:887573
In: 0 Sokkel
Type - ParameterTakesPrecedence: no; Sizeable: no; Material: EST. Klaas. 3x. Default, <Unnamed> (3), EST. Metall. Alumiinium. Värvitud. RAL7023 (Concrete grey) (3)
Type - Pset_ConcreteElementGeneral - FireRating: -
Type - Pset_DoorCommon - IsExternal: no; Reference: SU-KL-02 - 900x2100; FireRating: -; AcousticRating: -
Type - Pset_ProductRequirements - Category: Doors
Type - Pset_QuantityTakeOff - Reference: SU-KL-02 - 900x2100
OverallHeight: 2100 mm; OverallWidth: 900 mm; Material: EST. Metall. Alumiinium. Värvitud. RAL7023 (Concrete grey)

# IfcDoor: SMA_D01, 1-poolne:SU-M-01 - 1200x2100 EI-30, SMA_D01, 1-poolne:SU-M-01 - 1200x2100 EI-30:898495
In: 0 Sokkel
Type - ParameterTakesPrecedence: no; Sizeable: no; Material: <Unnamed> (3), EST. Metall. Alumiinium. Värvitud. RAL7023 (Concrete grey) (3), EST. Klaas. 3x. Default
Type - Pset_ConcreteElementGeneral - FireRating: EI-30
Type - Pset_DoorCommon - IsExternal: no; Reference: SU-M-01 - 1200x2100 EI-30; FireRating: EI-30; AcousticRating: 30dB
Type - Pset_ProductRequirements - Category: Doors
Type - Pset_QuantityTakeOff - Reference: SU-M-01 - 1200x2100 EI-30
OverallHeight: 2100 mm; OverallWidth: 1200 mm; Material: EST. Metall. Alumiinium. Värvitud. RAL7023 (Concrete grey)

# IfcDoor: SMA_D01, 1-poolne:SU-M-01 - 1200x2100 EI-30, SMA_D01, 1-poolne:SU-M-01 - 1200x2100 EI-30:887443
In: 0 Sokkel
Type - ParameterTakesPrecedence: no; Sizeable: no; Material: EST. Metall. Alumiinium. Värvitud. RAL7023 (Concrete grey) (3), <Unnamed> (3), EST. Klaas. 3x. Default
Type - Pset_ConcreteElementGeneral - FireRating: EI-30
Type - Pset_DoorCommon - IsExternal: no; Reference: SU-M-01 - 1200x2100 EI-30; FireRating: EI-30; AcousticRating: 30dB
Type - Pset_ProductRequirements - Category: Doors
Type - Pset_QuantityTakeOff - Reference: SU-M-01 - 1200x2100 EI-30
OverallHeight: 2100 mm; OverallWidth: 1200 mm; Material: EST. Metall. Alumiinium. Värvitud. RAL7023 (Concrete grey)

# IfcDoor: SMA_D01, 1-poolne:SU-M-02 - 1000x2100 EI-30, SMA_D01, 1-poolne:SU-M-02 - 1000x2100 EI-30:1242184
In: 1 Korrus
Type - OperationType: SINGLE_SWING_LEFT; ParameterTakesPrecedence: no; Sizeable: no; Material: EST. Metall. Alumiinium. Värvitud. RAL7023 (Concrete grey) (3), <Unnamed> (3), EST. Klaas. 3x. Default
Type - SMA_D01, 1-poolne:SU-M-02 - 1000x2100 EI-30:1242184 - PanelOperation: SWINGING
Type - Pset_ConcreteElementGeneral - FireRating: EI-30
Type - Pset_DoorCommon - IsExternal: no; Reference: SU-M-02 - 1000x2100 EI-30; FireRating: EI-30; AcousticRating: 30dB
Type - Pset_ProductRequirements - Category: Doors
Type - Pset_QuantityTakeOff - Reference: SU-M-02 - 1000x2100 EI-30
OverallHeight: 2100 mm; OverallWidth: 1000 mm; Material: EST. Metall. Alumiinium. Värvitud. RAL7023 (Concrete grey)

# IfcDoor: SMA_D01, 1-poolne:SU-M-02 - 1000x2100 EI-30 (2)
In: 0 Sokkel
Type - ParameterTakesPrecedence: no; Sizeable: no; Material: <Unnamed> (3), EST. Metall. Alumiinium. Värvitud. RAL7023 (Concrete grey) (3), EST. Klaas. 3x. Default
Type - Pset_ConcreteElementGeneral - FireRating: EI-30
Type - Pset_DoorCommon - IsExternal: no; Reference: SU-M-02 - 1000x2100 EI-30; FireRating: EI-30; AcousticRating: 30dB
Type - Pset_ProductRequirements - Category: Doors
Type - Pset_QuantityTakeOff - Reference: SU-M-02 - 1000x2100 EI-30
OverallHeight: 2100 mm; OverallWidth: 1000 mm; Material: EST. Metall. Alumiinium. Värvitud. RAL7023 (Concrete grey)
Name (SMA_D01, 1-poolne:SU-M-02 - 1000x2100 EI-30:...)
887050
887383

# IfcDoor: SMA_D01, 1-poolne:SU-M-03 - 1000x2000, SMA_D01, 1-poolne:SU-M-03 - 1000x2000:882178
In: 0 Sokkel
Type - ParameterTakesPrecedence: no; Sizeable: no; Material: EST. Metall. Alumiinium. Värvitud. RAL7023 (Concrete grey) (3), <Unnamed> (3), EST. Klaas. 3x. Default
Type - Pset_ConcreteElementGeneral - FireRating: -
Type - Pset_DoorCommon - IsExternal: no; Reference: SU-M-03 - 1000x2000; FireRating: -; AcousticRating: -
Type - Pset_ProductRequirements - Category: Doors
Type - Pset_QuantityTakeOff - Reference: SU-M-03 - 1000x2000
OverallHeight: 2000 mm; OverallWidth: 1000 mm; Material: EST. Metall. Alumiinium. Värvitud. RAL7023 (Concrete grey)

# IfcDoor: SMA_D01, 1-poolne:SU-M-03 - 1000x2100, SMA_D01, 1-poolne:SU-M-03 - 1000x2100:887324
In: 0 Sokkel
Type - ParameterTakesPrecedence: no; Sizeable: no; Material: EST. Metall. Alumiinium. Värvitud. RAL7023 (Concrete grey) (3), <Unnamed> (3), EST. Klaas. 3x. Default
Type - Pset_ConcreteElementGeneral - FireRating: -
Type - Pset_DoorCommon - IsExternal: no; Reference: SU-M-03 - 1000x2100; FireRating: -; AcousticRating: -
Type - Pset_ProductRequirements - Category: Doors
Type - Pset_QuantityTakeOff - Reference: SU-M-03 - 1000x2100
OverallHeight: 2100 mm; OverallWidth: 1000 mm; Material: EST. Metall. Alumiinium. Värvitud. RAL7023 (Concrete grey)

# IfcDoor: SMA_D01, 1-poolne:SU-M-04 - 1000x2100 EI-60 (3)
In: 0 Sokkel
Type - ParameterTakesPrecedence: no; Sizeable: no; Material: EST. Klaas. 3x. Default, EST. Metall. Alumiinium. Värvitud. RAL7023 (Concrete grey) (3), <Unnamed> (3)
Type - Pset_ConcreteElementGeneral - FireRating: EI-60
Type - Pset_DoorCommon - IsExternal: no; Reference: SU-M-04 - 1000x2100 EI-60; FireRating: EI-60; AcousticRating: -
Type - Pset_ProductRequirements - Category: Doors
Type - Pset_QuantityTakeOff - Reference: SU-M-04 - 1000x2100 EI-60
OverallHeight: 2100 mm; OverallWidth: 1000 mm; Material: EST. Metall. Alumiinium. Värvitud. RAL7023 (Concrete grey)
Name (SMA_D01, 1-poolne:SU-M-04 - 1000x2100 EI-60:...)
1081425
1081426
1081427

# IfcDoor: SMA_D01, 1-poolne:SU-M-06 - 1000x1200 EI-30, SMA_D01, 1-poolne:SU-M-06 - 1000x1200 EI-30:1145495
In: 0 Sokkel
Type - ParameterTakesPrecedence: no; Sizeable: no; Material: <Unnamed> (3), EST. Klaas. 3x. Default, EST. Metall. Alumiinium. Värvitud. RAL7023 (Concrete grey) (3)
Type - Pset_ConcreteElementGeneral - FireRating: -
Type - Pset_DoorCommon - IsExternal: no; Reference: SU-M-06 - 1000x1200 EI-30; FireRating: -; AcousticRating: -
Type - Pset_ProductRequirements - Category: Doors
Type - Pset_QuantityTakeOff - Reference: SU-M-06 - 1000x1200 EI-30
OverallHeight: 1200 mm; OverallWidth: 1000 mm; Material: EST. Metall. Alumiinium. Värvitud. RAL7023 (Concrete grey)
Pset_OpeningElementCommon - Reference: SU-M-06 - 1000x1200 EI-30; sets with these values: 2

# IfcDoor: SMA_D01, 1-poolne:SU-M-06 - 1000x1200 EI-30, SMA_D01, 1-poolne:SU-M-06 - 1000x1200 EI-30:1241829
In: 0 Sokkel
Type - ParameterTakesPrecedence: no; Sizeable: no; Material: <Unnamed> (3), EST. Metall. Alumiinium. Värvitud. RAL7023 (Concrete grey) (3), EST. Klaas. 3x. Default
Type - Pset_ConcreteElementGeneral - FireRating: -
Type - Pset_DoorCommon - IsExternal: no; Reference: SU-M-06 - 1000x1200 EI-30; FireRating: -; AcousticRating: -
Type - Pset_ProductRequirements - Category: Doors
Type - Pset_QuantityTakeOff - Reference: SU-M-06 - 1000x1200 EI-30
OverallHeight: 1200 mm; OverallWidth: 1000 mm; Material: EST. Metall. Alumiinium. Värvitud. RAL7023 (Concrete grey)

# IfcDoor: SMA_D01, 1-poolne:SU-M-07 - 800x2100 KORIS. (4)
Type - OperationType: SINGLE_SWING_RIGHT; ParameterTakesPrecedence: no; Sizeable: no; Material: <Unnamed> (3), EST. Metall. Alumiinium. Värvitud. RAL7023 (Concrete grey) (3), EST. Klaas. 3x. Default
Type - SMA_D01, 1-poolne:SU-M-07 - 800x2100 KORIS.:845257 - PanelOperation: SWINGING
Type - Pset_ConcreteElementGeneral - FireRating: -
Type - Pset_DoorCommon - IsExternal: no; Reference: SU-M-07 - 800x2100 KORIS.; FireRating: -; AcousticRating: -
Type - Pset_ProductRequirements - Category: Doors
Type - Pset_QuantityTakeOff - Reference: SU-M-07 - 800x2100 KORIS.
OverallHeight: 2100 mm; OverallWidth: 800 mm; Material: EST. Metall. Alumiinium. Värvitud. RAL7023 (Concrete grey)
Name (SMA_D01, 1-poolne:SU-M-07 - 800x2100 KORIS.:...) | In
845257 | 1 Korrus | Pset_OpeningElementCommon - Reference: SU-M-07 - 800x2100 KORIS.; sets with these values: 2
847510 | 2 Korrus
862837 | 3 Korrus | Pset_OpeningElementCommon - Reference: SU-M-07 - 800x2100 KORIS.; sets with these values: 2
865951 | 4 Korrus

# IfcDoor: SMA_D01, 1-poolne:SU-P-01 - 900x2100, SMA_D01, 1-poolne:SU-P-01 - 900x2100:885756
In: 0 Sokkel
Type - ParameterTakesPrecedence: no; Sizeable: no; Material: <Unnamed> (3), EST. Metall. Alumiinium. Värvitud. RAL7023 (Concrete grey) (3), EST. Klaas. 3x. Default
Type - Pset_ConcreteElementGeneral - FireRating: EI-30
Type - Pset_DoorCommon - IsExternal: no; Reference: SU-P-01 - 900x2100; FireRating: EI-30; AcousticRating: 30dB
Type - Pset_ProductRequirements - Category: Doors
Type - Pset_QuantityTakeOff - Reference: SU-P-01 - 900x2100
OverallHeight: 2100 mm; OverallWidth: 900 mm; Material: EST. Metall. Alumiinium. Värvitud. RAL7023 (Concrete grey)

# IfcDoor: SMA_D01, 1-poolne:SU-P-01 - 900x2100, SMA_D01, 1-poolne:SU-P-01 - 900x2100:1040855
In: 0 Sokkel
Type - ParameterTakesPrecedence: no; Sizeable: no; Material: EST. Klaas. 3x. Default, <Unnamed> (3), EST. Metall. Alumiinium. Värvitud. RAL7023 (Concrete grey) (3)
Type - Pset_ConcreteElementGeneral - FireRating: EI-30
Type - Pset_DoorCommon - IsExternal: no; Reference: SU-P-01 - 900x2100; FireRating: EI-30; AcousticRating: 30dB
Type - Pset_ProductRequirements - Category: Doors
Type - Pset_QuantityTakeOff - Reference: SU-P-01 - 900x2100
OverallHeight: 2100 mm; OverallWidth: 900 mm; Material: EST. Metall. Alumiinium. Värvitud. RAL7023 (Concrete grey)

# IfcDoor: SMA_D01, 1-poolne:SU-P-02 - 700x2100, SMA_D01, 1-poolne:SU-P-02 - 700x2100:1040864
In: 0 Sokkel
Type - ParameterTakesPrecedence: no; Sizeable: no; Material: <Unnamed> (3), EST. Klaas. 3x. Default, EST. Metall. Alumiinium. Värvitud. RAL7023 (Concrete grey) (3)
Type - Pset_ConcreteElementGeneral - FireRating: -
Type - Pset_DoorCommon - IsExternal: no; Reference: SU-P-02 - 700x2100; FireRating: -; AcousticRating: -
Type - Pset_ProductRequirements - Category: Doors
Type - Pset_QuantityTakeOff - Reference: SU-P-02 - 700x2100
OverallHeight: 2100 mm; OverallWidth: 700 mm; Material: EST. Metall. Alumiinium. Värvitud. RAL7023 (Concrete grey)
Pset_OpeningElementCommon - Reference: SU-P-02 - 700x2100; sets with these values: 2

# IfcDoor: SMA_D01, 1-poolne:SU-P-02 - 700x2100, SMA_D01, 1-poolne:SU-P-02 - 700x2100:1040854
In: 0 Sokkel
Type - ParameterTakesPrecedence: no; Sizeable: no; Material: <Unnamed> (3), EST. Metall. Alumiinium. Värvitud. RAL7023 (Concrete grey) (3), EST. Klaas. 3x. Default
Type - Pset_ConcreteElementGeneral - FireRating: -
Type - Pset_DoorCommon - IsExternal: no; Reference: SU-P-02 - 700x2100; FireRating: -; AcousticRating: -
Type - Pset_ProductRequirements - Category: Doors
Type - Pset_QuantityTakeOff - Reference: SU-P-02 - 700x2100
OverallHeight: 2100 mm; OverallWidth: 700 mm; Material: EST. Metall. Alumiinium. Värvitud. RAL7023 (Concrete grey)

# IfcDoor: SMA_D01, 1-poolne:SU-P-03 - 1000x2100, SMA_D01, 1-poolne:SU-P-03 - 1000x2100:847005
In: Sissepääs
Type - ParameterTakesPrecedence: no; Sizeable: no; Material: <Unnamed> (3), EST. Klaas. 3x. Default, __Aknaraam (2), EST. Metall. Alumiinium. Värvitud. RAL7023 (Concrete grey)
Type - Pset_ConcreteElementGeneral - FireRating: -
Type - Pset_DoorCommon - IsExternal: no; Reference: SU-P-03 - 1000x2100; FireRating: -; AcousticRating: 35dB
Type - Pset_ProductRequirements - Category: Doors
Type - Pset_QuantityTakeOff - Reference: SU-P-03 - 1000x2100
OverallHeight: 2100 mm; OverallWidth: 1000 mm; Material: EST. Metall. Alumiinium. Värvitud. RAL7023 (Concrete grey), __Aknaraam, EST. Klaas. 3x. Default

# IfcDoor: SMA_D01, 1-poolne:SU-P-03 - 1000x2100, SMA_D01, 1-poolne:SU-P-03 - 1000x2100:1041072
In: 0 Sokkel
Type - ParameterTakesPrecedence: no; Sizeable: no; Material: __Aknaraam (2), EST. Metall. Alumiinium. Värvitud. RAL7023 (Concrete grey), <Unnamed> (3), EST. Klaas. 3x. Default
Type - Pset_ConcreteElementGeneral - FireRating: -
Type - Pset_DoorCommon - IsExternal: no; Reference: SU-P-03 - 1000x2100; FireRating: -; AcousticRating: 35dB
Type - Pset_ProductRequirements - Category: Doors
Type - Pset_QuantityTakeOff - Reference: SU-P-03 - 1000x2100
OverallHeight: 2100 mm; OverallWidth: 1000 mm; Material: EST. Metall. Alumiinium. Värvitud. RAL7023 (Concrete grey), __Aknaraam, EST. Klaas. 3x. Default

# IfcDoor: SMA_D01, 1-poolne:SU-P-04 - 1000x2020 EI-30, SMA_D01, 1-poolne:SU-P-04 - 1000x2020 EI-30:864017
In: 3 Korrus
Type - ParameterTakesPrecedence: no; Sizeable: no; Material: EST. Metall. Alumiinium. Värvitud. RAL7023 (Concrete grey) (3), <Unnamed> (3), EST. Klaas. 3x. Default
Type - Pset_ConcreteElementGeneral - FireRating: EI-30
Type - Pset_DoorCommon - IsExternal: no; Reference: SU-P-04 - 1000x2020 EI-30; FireRating: EI-30; AcousticRating: 35dB
Type - Pset_ProductRequirements - Category: Doors
Type - Pset_QuantityTakeOff - Reference: SU-P-04 - 1000x2020 EI-30
OverallHeight: 2020 mm; OverallWidth: 1000 mm; Material: EST. Metall. Alumiinium. Värvitud. RAL7023 (Concrete grey)

# IfcDoor: SMA_D01, 1-poolne:SU-P-04 - 1000x2040 EI-30, SMA_D01, 1-poolne:SU-P-04 - 1000x2040 EI-30:864098
In: 3 Korrus
Type - ParameterTakesPrecedence: no; Sizeable: no; Material: EST. Klaas. 3x. Default, <Unnamed> (3), EST. Metall. Alumiinium. Värvitud. RAL7023 (Concrete grey) (3)
Type - Pset_ConcreteElementGeneral - FireRating: EI-30
Type - Pset_DoorCommon - IsExternal: no; Reference: SU-P-04 - 1000x2040 EI-30; FireRating: EI-30; AcousticRating: 35dB
Type - Pset_ProductRequirements - Category: Doors
Type - Pset_QuantityTakeOff - Reference: SU-P-04 - 1000x2040 EI-30
OverallHeight: 2040 mm; OverallWidth: 1000 mm; Material: EST. Metall. Alumiinium. Värvitud. RAL7023 (Concrete grey)

# IfcDoor: SMA_D01, 1-poolne:SU-P-04 - 1000x2050 EI-30, SMA_D01, 1-poolne:SU-P-04 - 1000x2050 EI-30:788744
In: 1 Korrus
Type - OperationType: SINGLE_SWING_RIGHT; ParameterTakesPrecedence: no; Sizeable: no; Material: EST. Metall. Alumiinium. Värvitud. RAL7023 (Concrete grey) (3), <Unnamed> (3), EST. Klaas. 3x. Default
Type - SMA_D01, 1-poolne:SU-P-04 - 1000x2050 EI-30:788744 - PanelOperation: SWINGING
Type - Pset_ConcreteElementGeneral - FireRating: EI-30
Type - Pset_DoorCommon - IsExternal: no; Reference: SU-P-04 - 1000x2050 EI-30; FireRating: EI-30; AcousticRating: 35dB
Type - Pset_ProductRequirements - Category: Doors
Type - Pset_QuantityTakeOff - Reference: SU-P-04 - 1000x2050 EI-30
OverallHeight: 2050 mm; OverallWidth: 1000 mm; Material: EST. Metall. Alumiinium. Värvitud. RAL7023 (Concrete grey)

# IfcDoor: SMA_D01, 1-poolne:SU-P-04 - 1000x2060 EI-30, SMA_D01, 1-poolne:SU-P-04 - 1000x2060 EI-30:788842
In: 1 Korrus
Type - OperationType: SINGLE_SWING_RIGHT; ParameterTakesPrecedence: no; Sizeable: no; Material: EST. Metall. Alumiinium. Värvitud. RAL7023 (Concrete grey) (3), <Unnamed> (3), EST. Klaas. 3x. Default
Type - SMA_D01, 1-poolne:SU-P-04 - 1000x2060 EI-30:788842 - PanelOperation: SWINGING
Type - Pset_ConcreteElementGeneral - FireRating: EI-30
Type - Pset_DoorCommon - IsExternal: no; Reference: SU-P-04 - 1000x2060 EI-30; FireRating: EI-30; AcousticRating: 35dB
Type - Pset_ProductRequirements - Category: Doors
Type - Pset_QuantityTakeOff - Reference: SU-P-04 - 1000x2060 EI-30
OverallHeight: 2060 mm; OverallWidth: 1000 mm; Material: EST. Metall. Alumiinium. Värvitud. RAL7023 (Concrete grey)

# IfcDoor: SMA_D01, 1-poolne:SU-P-04 - 1000x2070 EI-30, SMA_D01, 1-poolne:SU-P-04 - 1000x2070 EI-30:847724
In: 2 Korrus
Type - ParameterTakesPrecedence: no; Sizeable: no; Material: EST. Klaas. 3x. Default, <Unnamed> (3), EST. Metall. Alumiinium. Värvitud. RAL7023 (Concrete grey) (3)
Type - Pset_ConcreteElementGeneral - FireRating: EI-30
Type - Pset_DoorCommon - IsExternal: no; Reference: SU-P-04 - 1000x2070 EI-30; FireRating: EI-30; AcousticRating: 35dB
Type - Pset_ProductRequirements - Category: Doors
Type - Pset_QuantityTakeOff - Reference: SU-P-04 - 1000x2070 EI-30
OverallHeight: 2070 mm; OverallWidth: 1000 mm; Material: EST. Metall. Alumiinium. Värvitud. RAL7023 (Concrete grey)

# IfcDoor: SMA_D01, 1-poolne:SU-P-04 - 1000x2070 EI-30, SMA_D01, 1-poolne:SU-P-04 - 1000x2070 EI-30:866954
In: 4 Korrus
Type - ParameterTakesPrecedence: no; Sizeable: no; Material: EST. Metall. Alumiinium. Värvitud. RAL7023 (Concrete grey) (3), <Unnamed> (3), EST. Klaas. 3x. Default
Type - Pset_ConcreteElementGeneral - FireRating: EI-30
Type - Pset_DoorCommon - IsExternal: no; Reference: SU-P-04 - 1000x2070 EI-30; FireRating: EI-30; AcousticRating: 35dB
Type - Pset_ProductRequirements - Category: Doors
Type - Pset_QuantityTakeOff - Reference: SU-P-04 - 1000x2070 EI-30
OverallHeight: 2070 mm; OverallWidth: 1000 mm; Material: EST. Metall. Alumiinium. Värvitud. RAL7023 (Concrete grey)

# IfcDoor: SMA_D01, 1-poolne:SU-P-04 - 1000x2080 EI-30, SMA_D01, 1-poolne:SU-P-04 - 1000x2080 EI-30:867932
In: 4 Korrus
Type - ParameterTakesPrecedence: no; Sizeable: no; Material: <Unnamed> (3), EST. Metall. Alumiinium. Värvitud. RAL7023 (Concrete grey) (3), EST. Klaas. 3x. Default
Type - Pset_ConcreteElementGeneral - FireRating: EI-30
Type - Pset_DoorCommon - IsExternal: no; Reference: SU-P-04 - 1000x2080 EI-30; FireRating: EI-30; AcousticRating: 35dB
Type - Pset_ProductRequirements - Category: Doors
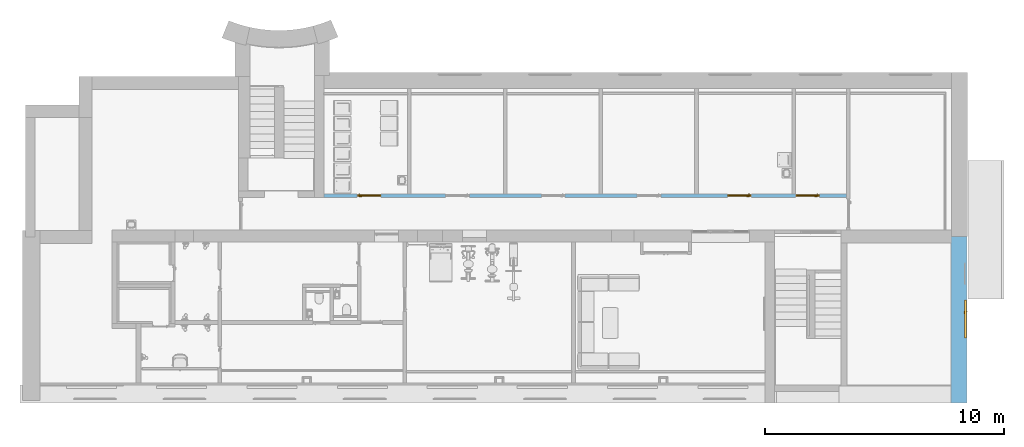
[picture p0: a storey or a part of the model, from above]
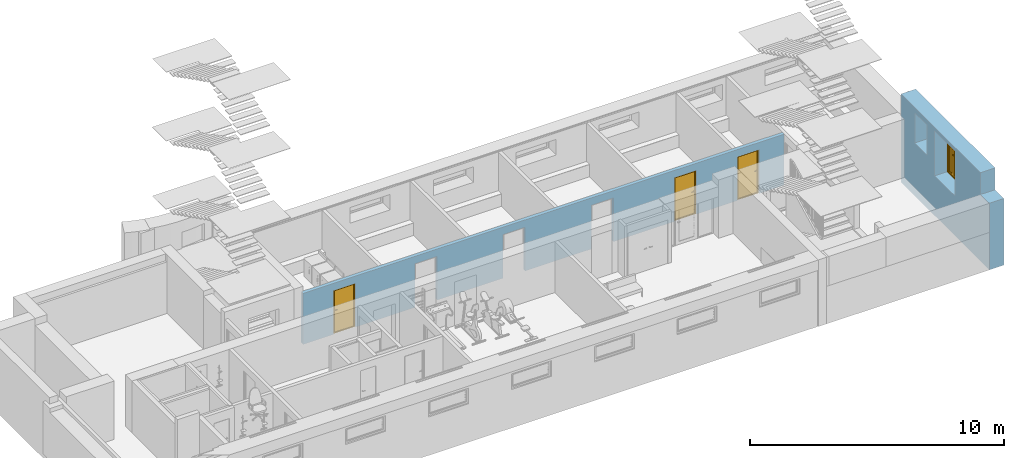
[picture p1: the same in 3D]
Properties of the parts of a building model (IFC2X3), part 2 of 4

# IfcDoor: SMA_D01, 1-poolne:SU-P-04 - 1000x2080 EI-30, SMA_D01, 1-poolne:SU-P-04 - 1000x2080 EI-30:867932
Type - Pset_QuantityTakeOff - Reference: SU-P-04 - 1000x2080 EI-30
OverallHeight: 2080 mm; OverallWidth: 1000 mm; Material: EST. Metall. Alumiinium. Värvitud. RAL7023 (Concrete grey)

# IfcDoor: SMA_D01, 1-poolne:SU-P-04 - 1000x2090 EI-30, SMA_D01, 1-poolne:SU-P-04 - 1000x2090 EI-30:849220
In: 2 Korrus
Type - ParameterTakesPrecedence: no; Sizeable: no; Material: <Unnamed> (3), EST. Klaas. 3x. Default, EST. Metall. Alumiinium. Värvitud. RAL7023 (Concrete grey) (3)
Type - Pset_ConcreteElementGeneral - FireRating: EI-30
Type - Pset_DoorCommon - IsExternal: no; Reference: SU-P-04 - 1000x2090 EI-30; FireRating: EI-30; AcousticRating: 35dB
Type - Pset_ProductRequirements - Category: Doors
Type - Pset_QuantityTakeOff - Reference: SU-P-04 - 1000x2090 EI-30
OverallHeight: 2090 mm; OverallWidth: 1000 mm; Material: EST. Metall. Alumiinium. Värvitud. RAL7023 (Concrete grey)

# IfcDoor: SMA_D01, 1-poolne:SU-P-04 - 1000x2100 EI-30 (7)
Type - OperationType: SINGLE_SWING_LEFT; ParameterTakesPrecedence: no; Sizeable: no; Material: EST. Metall. Alumiinium. Värvitud. RAL7023 (Concrete grey) (3), <Unnamed> (3), EST. Klaas. 3x. Default
Type - SMA_D01, 1-poolne:SU-P-04 - 1000x2100 EI-30:831116 - PanelOperation: SWINGING
Type - Pset_ConcreteElementGeneral - FireRating: EI-30
Type - Pset_DoorCommon - IsExternal: no; Reference: SU-P-04 - 1000x2100 EI-30; FireRating: EI-30; AcousticRating: 35dB
Type - Pset_ProductRequirements - Category: Doors
Type - Pset_QuantityTakeOff - Reference: SU-P-04 - 1000x2100 EI-30
OverallHeight: 2100 mm; OverallWidth: 1000 mm; Material: EST. Metall. Alumiinium. Värvitud. RAL7023 (Concrete grey)
Name (SMA_D01, 1-poolne:SU-P-04 - 1000x2100 EI-30:...) | In
831116 | 1 Korrus
847492 | 2 Korrus | Pset_OpeningElementCommon - Reference: SU-P-04 - 1000x2100 EI-30; sets with these values: 2
847500 | 2 Korrus
862823 | 3 Korrus | Pset_OpeningElementCommon - Reference: SU-P-04 - 1000x2100 EI-30; sets with these values: 2
862830 | 3 Korrus
865937 | 4 Korrus | Pset_OpeningElementCommon - Reference: SU-P-04 - 1000x2100 EI-30; sets with these values: 2
865944 | 4 Korrus

# IfcDoor: SMA_D01, 1-poolne:SU-P-04 - 1000x2100 EI-30 (5)
Type - OperationType: SINGLE_SWING_RIGHT; ParameterTakesPrecedence: no; Sizeable: no; Material: <Unnamed> (3), EST. Klaas. 3x. Default, EST. Metall. Alumiinium. Värvitud. RAL7023 (Concrete grey) (3)
Type - SMA_D01, 1-poolne:SU-P-04 - 1000x2100 EI-30:828314 - PanelOperation: SWINGING
Type - Pset_ConcreteElementGeneral - FireRating: EI-30
Type - Pset_DoorCommon - IsExternal: no; Reference: SU-P-04 - 1000x2100 EI-30; FireRating: EI-30; AcousticRating: 35dB
Type - Pset_ProductRequirements - Category: Doors
Type - Pset_QuantityTakeOff - Reference: SU-P-04 - 1000x2100 EI-30
OverallHeight: 2100 mm; OverallWidth: 1000 mm; Material: EST. Metall. Alumiinium. Värvitud. RAL7023 (Concrete grey)
Name (SMA_D01, 1-poolne:SU-P-04 - 1000x2100 EI-30:...) | In
828314 | 1 Korrus
830798 | 1 Korrus
847499 | 2 Korrus
862829 | 3 Korrus
865943 | 4 Korrus

# IfcDoor: SMA_D01, 1-poolne:SU-P-04 - 1000x2100 EI-30 (4)
Type - OperationType: SINGLE_SWING_RIGHT; ParameterTakesPrecedence: no; Sizeable: no; Material: EST. Metall. Alumiinium. Värvitud. RAL7023 (Concrete grey) (3), <Unnamed> (3), EST. Klaas. 3x. Default
Type - SMA_D01, 1-poolne:SU-P-04 - 1000x2100 EI-30:845374 - PanelOperation: SWINGING
Type - Pset_ConcreteElementGeneral - FireRating: EI-30
Type - Pset_DoorCommon - IsExternal: no; Reference: SU-P-04 - 1000x2100 EI-30; FireRating: EI-30; AcousticRating: 35dB
Type - Pset_ProductRequirements - Category: Doors
Type - Pset_QuantityTakeOff - Reference: SU-P-04 - 1000x2100 EI-30
OverallHeight: 2100 mm; OverallWidth: 1000 mm; Material: EST. Metall. Alumiinium. Värvitud. RAL7023 (Concrete grey)
Name (SMA_D01, 1-poolne:SU-P-04 - 1000x2100 EI-30:...) | In
845374 | 1 Korrus
847511 | 2 Korrus
862838 | 3 Korrus
865952 | 4 Korrus

# IfcDoor: SMA_D01, 1-poolne:SU-P-05 - 900x2100 TUBA (3)
Type - OperationType: SINGLE_SWING_LEFT; ParameterTakesPrecedence: no; Sizeable: no; Material: <Unnamed> (3), EST. Klaas. 3x. Default, EST. Metall. Alumiinium. Värvitud. RAL7023 (Concrete grey) (3)
Type - SMA_D01, 1-poolne:SU-P-05 - 900x2100 TUBA:838925 - PanelOperation: SWINGING
Type - Pset_ConcreteElementGeneral - FireRating: -
Type - Pset_DoorCommon - IsExternal: no; Reference: SU-P-05 - 900x2100 TUBA; FireRating: -; AcousticRating: 35dB
Type - Pset_ProductRequirements - Category: Doors
Type - Pset_QuantityTakeOff - Reference: SU-P-05 - 900x2100 TUBA
OverallHeight: 2100 mm; OverallWidth: 900 mm; Material: EST. Metall. Alumiinium. Värvitud. RAL7023 (Concrete grey)
Pset_OpeningElementCommon - Reference: SU-P-05 - 900x2100 TUBA; sets with these values: 2
Name (SMA_D01, 1-poolne:SU-P-05 - 900x2100 TUBA:...) | In
838925 | 1 Korrus
862849 | 3 Korrus
865963 | 4 Korrus

# IfcDoor: SMA_D01, 1-poolne:SU-P-05 - 900x2100 TUBA (24)
Type - OperationType: SINGLE_SWING_LEFT; ParameterTakesPrecedence: no; Sizeable: no; Material: EST. Metall. Alumiinium. Värvitud. RAL7023 (Concrete grey) (3), <Unnamed> (3), EST. Klaas. 3x. Default
Type - SMA_D01, 1-poolne:SU-P-05 - 900x2100 TUBA:809404 - PanelOperation: SWINGING
Type - Pset_ConcreteElementGeneral - FireRating: -
Type - Pset_DoorCommon - IsExternal: no; Reference: SU-P-05 - 900x2100 TUBA; FireRating: -; AcousticRating: 35dB
Type - Pset_ProductRequirements - Category: Doors
Type - Pset_QuantityTakeOff - Reference: SU-P-05 - 900x2100 TUBA
OverallHeight: 2100 mm; OverallWidth: 900 mm; Material: EST. Metall. Alumiinium. Värvitud. RAL7023 (Concrete grey)
Name (SMA_D01, 1-poolne:SU-P-05 - 900x2100 TUBA:...) | In
809404 | 1 Korrus
814190 | 1 Korrus
828277 | 1 Korrus | Pset_OpeningElementCommon - Reference: SU-P-05 - 900x2100 TUBA; sets with these values: 2
830719 | 1 Korrus
847460 | 2 Korrus
847472 | 2 Korrus
847494 | 2 Korrus
847498 | 2 Korrus
847504 | 2 Korrus
855845 | 2 Korrus | Pset_OpeningElementCommon - Reference: SU-P-05 - 900x2100 TUBA; sets with these values: 2
860016 | 2 Korrus | Pset_OpeningElementCommon - Reference: SU-P-05 - 900x2100 TUBA; sets with these values: 2
862794 | 3 Korrus
862805 | 3 Korrus
862825 | 3 Korrus
862828 | 3 Korrus
862833 | 3 Korrus
862851 | 3 Korrus
865908 | 4 Korrus
865919 | 4 Korrus
865942 | 4 Korrus
865947 | 4 Korrus
865965 | 4 Korrus
1066458 | 1 Korrus | Pset_OpeningElementCommon - Reference: SU-P-05 - 900x2100 TUBA; sets with these values: 2
1087235 | 1 Korrus

# IfcDoor: SMA_D01, 1-poolne:SU-P-05 - 900x2100 TUBA (37)
Type - OperationType: SINGLE_SWING_RIGHT; ParameterTakesPrecedence: no; Sizeable: no; Material: <Unnamed> (3), EST. Klaas. 3x. Default, EST. Metall. Alumiinium. Värvitud. RAL7023 (Concrete grey) (3)
Type - SMA_D01, 1-poolne:SU-P-05 - 900x2100 TUBA:809587 - PanelOperation: SWINGING
Type - Pset_ConcreteElementGeneral - FireRating: -
Type - Pset_DoorCommon - IsExternal: no; Reference: SU-P-05 - 900x2100 TUBA; FireRating: -; AcousticRating: 35dB
Type - Pset_ProductRequirements - Category: Doors
Type - Pset_QuantityTakeOff - Reference: SU-P-05 - 900x2100 TUBA
OverallHeight: 2100 mm; OverallWidth: 900 mm; Material: EST. Metall. Alumiinium. Värvitud. RAL7023 (Concrete grey)
Name (SMA_D01, 1-poolne:SU-P-05 - 900x2100 TUBA:...) | In
809587 | 1 Korrus
811532 | 1 Korrus
811581 | 1 Korrus
813377 | 1 Korrus
825858 | 1 Korrus
830617 | 1 Korrus
847461 | 2 Korrus
847467 | 2 Korrus
847468 | 2 Korrus
847470 | 2 Korrus | Pset_OpeningElementCommon - Reference: SU-P-05 - 900x2100 TUBA; sets with these values: 2
847483 | 2 Korrus
847495 | 2 Korrus
847497 | 2 Korrus
852576 | 2 Korrus | Pset_OpeningElementCommon - Reference: SU-P-05 - 900x2100 TUBA; sets with these values: 2
852751 | 2 Korrus
860031 | 2 Korrus
862795 | 3 Korrus
862800 | 3 Korrus
862801 | 3 Korrus
862803 | 3 Korrus
862815 | 3 Korrus
862826 | 3 Korrus
862827 | 3 Korrus
862846 | 3 Korrus | Pset_OpeningElementCommon - Reference: SU-P-05 - 900x2100 TUBA; sets with these values: 2
862847 | 3 Korrus
862852 | 3 Korrus
865914 | 4 Korrus
865915 | 4 Korrus
865917 | 4 Korrus
865929 | 4 Korrus
865940 | 4 Korrus
865960 | 4 Korrus | Pset_OpeningElementCommon - Reference: SU-P-05 - 900x2100 TUBA; sets with these values: 2
865961 | 4 Korrus
865966 | 4 Korrus
1066460 | 1 Korrus
1087236 | 1 Korrus
1087275 | 1 Korrus

# IfcDoor: SMA_D01, 1-poolne:SU-P-05 - 900x2100 TUBA, SMA_D01, 1-poolne:SU-P-05 - 900x2100 TUBA:865939
In: 4 Korrus
Type - ParameterTakesPrecedence: no; Sizeable: no; Material: <Unnamed> (3), EST. Klaas. 3x. Default, EST. Metall. Alumiinium. Värvitud. RAL7023 (Concrete grey) (3)
Type - Pset_ConcreteElementGeneral - FireRating: -
Type - Pset_DoorCommon - IsExternal: no; Reference: SU-P-05 - 900x2100 TUBA; FireRating: -; AcousticRating: 35dB
Type - Pset_ProductRequirements - Category: Doors
Type - Pset_QuantityTakeOff - Reference: SU-P-05 - 900x2100 TUBA
OverallHeight: 2100 mm; OverallWidth: 900 mm; Material: EST. Metall. Alumiinium. Värvitud. RAL7023 (Concrete grey)

# IfcDoor: SMA_D01, 1-poolne:SU-P-05 - 900x2100 TUBA, SMA_D01, 1-poolne:SU-P-05 - 900x2100 TUBA:865909
In: 4 Korrus
Type - ParameterTakesPrecedence: no; Sizeable: no; Material: <Unnamed> (3), EST. Metall. Alumiinium. Värvitud. RAL7023 (Concrete grey) (3), EST. Klaas. 3x. Default
Type - Pset_ConcreteElementGeneral - FireRating: -
Type - Pset_DoorCommon - IsExternal: no; Reference: SU-P-05 - 900x2100 TUBA; FireRating: -; AcousticRating: 35dB
Type - Pset_ProductRequirements - Category: Doors
Type - Pset_QuantityTakeOff - Reference: SU-P-05 - 900x2100 TUBA
OverallHeight: 2100 mm; OverallWidth: 900 mm; Material: EST. Metall. Alumiinium. Värvitud. RAL7023 (Concrete grey)

# IfcDoor: SMA_D01, 1-poolne:SU-P-05 - 900x2100 TUBA, SMA_D01, 1-poolne:SU-P-05 - 900x2100 TUBA:865941
In: 4 Korrus
Type - ParameterTakesPrecedence: no; Sizeable: no; Material: EST. Metall. Alumiinium. Värvitud. RAL7023 (Concrete grey) (3), <Unnamed> (3), EST. Klaas. 3x. Default
Type - Pset_ConcreteElementGeneral - FireRating: -
Type - Pset_DoorCommon - IsExternal: no; Reference: SU-P-05 - 900x2100 TUBA; FireRating: -; AcousticRating: 35dB
Type - Pset_ProductRequirements - Category: Doors
Type - Pset_QuantityTakeOff - Reference: SU-P-05 - 900x2100 TUBA
OverallHeight: 2100 mm; OverallWidth: 900 mm; Material: EST. Metall. Alumiinium. Värvitud. RAL7023 (Concrete grey)

# IfcDoor: SMA_D01, 1-poolne:SU-P-06 - 800x2100 DUŠŠ (6)
Type - OperationType: SINGLE_SWING_LEFT; ParameterTakesPrecedence: no; Sizeable: no; Material: EST. Klaas. 3x. Default, EST. Metall. Alumiinium. Värvitud. RAL7023 (Concrete grey) (3), <Unnamed> (3)
Type - SMA_D01, 1-poolne:SU-P-06 - 800x2100 DUŠŠ:817009 - PanelOperation: SWINGING
Type - Pset_ConcreteElementGeneral - FireRating: -
Type - Pset_DoorCommon - IsExternal: no; Reference: SU-P-06 - 800x2100 DUŠŠ; FireRating: -; AcousticRating: 30dB
Type - Pset_ProductRequirements - Category: Doors
Type - Pset_QuantityTakeOff - Reference: SU-P-06 - 800x2100 DUŠŠ
OverallHeight: 2100 mm; OverallWidth: 800 mm; Material: EST. Metall. Alumiinium. Värvitud. RAL7023 (Concrete grey)
Name (SMA_D01, 1-poolne:SU-P-06 - 800x2100 DUŠŠ:...) | In | Reference | sets with these values
817009 | 1 Korrus | SU-P-06 - 800x2100 DUŠŠ | 2
830090 | 1 Korrus
863623 | 3 Korrus | SU-P-06 - 800x2100 DUŠŠ | 2
863627 | 3 Korrus | SU-P-06 - 800x2100 DUŠŠ | 2
866267 | 4 Korrus | SU-P-06 - 800x2100 DUŠŠ | 2
866271 | 4 Korrus | SU-P-06 - 800x2100 DUŠŠ | 2

# IfcDoor: SMA_D01, 1-poolne:SU-P-06 - 800x2100 DUŠŠ (6)
Type - OperationType: SINGLE_SWING_RIGHT; ParameterTakesPrecedence: no; Sizeable: no; Material: EST. Metall. Alumiinium. Värvitud. RAL7023 (Concrete grey) (3), <Unnamed> (3), EST. Klaas. 3x. Default
Type - SMA_D01, 1-poolne:SU-P-06 - 800x2100 DUŠŠ:830153 - PanelOperation: SWINGING
Type - Pset_ConcreteElementGeneral - FireRating: -
Type - Pset_DoorCommon - IsExternal: no; Reference: SU-P-06 - 800x2100 DUŠŠ; FireRating: -; AcousticRating: 30dB
Type - Pset_ProductRequirements - Category: Doors
Type - Pset_QuantityTakeOff - Reference: SU-P-06 - 800x2100 DUŠŠ
OverallHeight: 2100 mm; OverallWidth: 800 mm; Material: EST. Metall. Alumiinium. Värvitud. RAL7023 (Concrete grey)
Name (SMA_D01, 1-poolne:SU-P-06 - 800x2100 DUŠŠ:...) | In | Reference | sets with these values
830153 | 1 Korrus
843613 | 1 Korrus | SU-P-06 - 800x2100 DUŠŠ | 2
863628 | 3 Korrus | SU-P-06 - 800x2100 DUŠŠ | 2
863634 | 3 Korrus | SU-P-06 - 800x2100 DUŠŠ | 2
866272 | 4 Korrus | SU-P-06 - 800x2100 DUŠŠ | 2
866278 | 4 Korrus | SU-P-06 - 800x2100 DUŠŠ | 2

# IfcDoor: SMA_D01, 1-poolne:SU-P-06 - 800x2100 DUŠŠ (2)
In: 2 Korrus
Type - ParameterTakesPrecedence: no; Sizeable: no; Material: EST. Metall. Alumiinium. Värvitud. RAL7023 (Concrete grey) (3), <Unnamed> (3), EST. Klaas. 3x. Default
Type - Pset_ConcreteElementGeneral - FireRating: -
Type - Pset_DoorCommon - IsExternal: no; Reference: SU-P-06 - 800x2100 DUŠŠ; FireRating: -; AcousticRating: 30dB
Type - Pset_ProductRequirements - Category: Doors
Type - Pset_QuantityTakeOff - Reference: SU-P-06 - 800x2100 DUŠŠ
OverallHeight: 2100 mm; OverallWidth: 800 mm; Material: EST. Metall. Alumiinium. Värvitud. RAL7023 (Concrete grey)
Pset_OpeningElementCommon - Reference: SU-P-06 - 800x2100 DUŠŠ; sets with these values: 2
Name (SMA_D01, 1-poolne:SU-P-06 - 800x2100 DUŠŠ:...)
847550
847556

# IfcDoor: SMA_D01, 1-poolne:SU-P-06 - 800x2100 DUŠŠ (6)
Type - ParameterTakesPrecedence: no; Sizeable: no; Material: EST. Metall. Alumiinium. Värvitud. RAL7023 (Concrete grey) (3), EST. Klaas. 3x. Default, <Unnamed> (3)
Type - Pset_ConcreteElementGeneral - FireRating: -
Type - Pset_DoorCommon - IsExternal: no; Reference: SU-P-06 - 800x2100 DUŠŠ; FireRating: -; AcousticRating: 30dB
Type - Pset_ProductRequirements - Category: Doors
Type - Pset_QuantityTakeOff - Reference: SU-P-06 - 800x2100 DUŠŠ
OverallHeight: 2100 mm; OverallWidth: 800 mm; Material: EST. Metall. Alumiinium. Värvitud. RAL7023 (Concrete grey)
Name (SMA_D01, 1-poolne:SU-P-06 - 800x2100 DUŠŠ:...) | In
847557 | 2 Korrus | Pset_OpeningElementCommon - Reference: SU-P-06 - 800x2100 DUŠŠ; sets with these values: 2
847565 | 2 Korrus | Pset_OpeningElementCommon - Reference: SU-P-06 - 800x2100 DUŠŠ; sets with these values: 2
859936 | 2 Korrus
862850 | 3 Korrus
865964 | 4 Korrus
1087133 | 1 Korrus

# IfcDoor: SMA_D01, 1-poolne:SU-P-07 - 1000x2100, SMA_D01, 1-poolne:SU-P-07 - 1000x2100:788999
In: 1 Korrus
Type - OperationType: SINGLE_SWING_RIGHT; ParameterTakesPrecedence: no; Sizeable: no; Material: EST. Metall. Alumiinium. Värvitud. RAL7023 (Concrete grey) (3), <Unnamed> (3), EST. Klaas. 3x. Default
Type - SMA_D01, 1-poolne:SU-P-07 - 1000x2100:788999 - PanelOperation: SWINGING
Type - Pset_ConcreteElementGeneral - FireRating: -
Type - Pset_DoorCommon - IsExternal: no; Reference: SU-P-07 - 1000x2100; FireRating: -; AcousticRating: -
Type - Pset_ProductRequirements - Category: Doors
Type - Pset_QuantityTakeOff - Reference: SU-P-07 - 1000x2100
OverallHeight: 2060 mm; OverallWidth: 1000 mm; Material: EST. Metall. Alumiinium. Värvitud. RAL7023 (Concrete grey)
Pset_OpeningElementCommon - Reference: SU-P-07 - 1000x2100; sets with these values: 2

# IfcDoor: SMA_D01, 1-poolne:SU-P-08 - 700x2100 DUŠŠ, SMA_D01, 1-poolne:SU-P-08 - 700x2100 DUŠŠ:839488
In: 1 Korrus
Type - OperationType: SINGLE_SWING_LEFT; ParameterTakesPrecedence: no; Sizeable: no; Material: EST. Metall. Alumiinium. Värvitud. RAL7023 (Concrete grey) (3), EST. Klaas. 3x. Default, <Unnamed> (3)
Type - SMA_D01, 1-poolne:SU-P-08 - 700x2100 DUŠŠ:839488 - PanelOperation: SWINGING
Type - Pset_ConcreteElementGeneral - FireRating: -
Type - Pset_DoorCommon - IsExternal: no; Reference: SU-P-08 - 700x2100 DUŠŠ; FireRating: -; AcousticRating: 30dB
Type - Pset_ProductRequirements - Category: Doors
Type - Pset_QuantityTakeOff - Reference: SU-P-08 - 700x2100 DUŠŠ
OverallHeight: 2100 mm; OverallWidth: 700 mm; Material: EST. Metall. Alumiinium. Värvitud. RAL7023 (Concrete grey)
Pset_OpeningElementCommon - Reference: SU-P-08 - 700x2100 DUŠŠ; sets with these values: 2

# IfcDoor: SMA_D01, 1-poolne:SU-P-08 - 700x2100 DUŠŠ (3)
Type - ParameterTakesPrecedence: no; Sizeable: no; Material: EST. Metall. Alumiinium. Värvitud. RAL7023 (Concrete grey) (3), EST. Klaas. 3x. Default, <Unnamed> (3)
Type - Pset_ConcreteElementGeneral - FireRating: -
Type - Pset_DoorCommon - IsExternal: no; Reference: SU-P-08 - 700x2100 DUŠŠ; FireRating: -; AcousticRating: 30dB
Type - Pset_ProductRequirements - Category: Doors
Type - Pset_QuantityTakeOff - Reference: SU-P-08 - 700x2100 DUŠŠ
OverallHeight: 2100 mm; OverallWidth: 700 mm; Material: EST. Metall. Alumiinium. Värvitud. RAL7023 (Concrete grey)
Name (SMA_D01, 1-poolne:SU-P-08 - 700x2100 DUŠŠ:...) | In | Reference | sets with these values
847561 | 2 Korrus
866580 | 3 Korrus | SU-P-08 - 700x2100 DUŠŠ | 2
866586 | 4 Korrus | SU-P-08 - 700x2100 DUŠŠ | 2

# IfcDoor: SMA_D01, 1-poolne:SU-P-09 - 1000x2020, SMA_D01, 1-poolne:SU-P-09 - 1000x2020:863814
In: 3 Korrus
Type - ParameterTakesPrecedence: no; Sizeable: no; Material: EST. Klaas. 3x. Default, <Unnamed> (3), EST. Metall. Alumiinium. Värvitud. RAL7023 (Concrete grey) (3)
Type - Pset_ConcreteElementGeneral - FireRating: -
Type - Pset_DoorCommon - IsExternal: no; Reference: SU-P-09 - 1000x2020; FireRating: -; AcousticRating: 35dB
Type - Pset_ProductRequirements - Category: Doors
Type - Pset_QuantityTakeOff - Reference: SU-P-09 - 1000x2020
OverallHeight: 2020 mm; OverallWidth: 1000 mm; Material: EST. Metall. Alumiinium. Värvitud. RAL7023 (Concrete grey)

# IfcDoor: SMA_D01, 1-poolne:SU-P-09 - 1000x2050, SMA_D01, 1-poolne:SU-P-09 - 1000x2050:788391
In: 1 Korrus
Type - OperationType: SINGLE_SWING_LEFT; ParameterTakesPrecedence: no; Sizeable: no; Material: <Unnamed> (3), EST. Metall. Alumiinium. Värvitud. RAL7023 (Concrete grey) (3), EST. Klaas. 3x. Default
Type - SMA_D01, 1-poolne:SU-P-09 - 1000x2050:788391 - PanelOperation: SWINGING
Type - Pset_ConcreteElementGeneral - FireRating: -
Type - Pset_DoorCommon - IsExternal: no; Reference: SU-P-09 - 1000x2050; FireRating: -; AcousticRating: 35dB
Type - Pset_ProductRequirements - Category: Doors
Type - Pset_QuantityTakeOff - Reference: SU-P-09 - 1000x2050
OverallHeight: 2050 mm; OverallWidth: 1000 mm; Material: EST. Metall. Alumiinium. Värvitud. RAL7023 (Concrete grey)

# IfcDoor: SMA_D01, 1-poolne:SU-P-09 - 1000x2070, SMA_D01, 1-poolne:SU-P-09 - 1000x2070:847815
In: 2 Korrus
Type - ParameterTakesPrecedence: no; Sizeable: no; Material: <Unnamed> (3), EST. Metall. Alumiinium. Värvitud. RAL7023 (Concrete grey) (3), EST. Klaas. 3x. Default
Type - Pset_ConcreteElementGeneral - FireRating: -
Type - Pset_DoorCommon - IsExternal: no; Reference: SU-P-09 - 1000x2070; FireRating: -; AcousticRating: 35dB
Type - Pset_ProductRequirements - Category: Doors
Type - Pset_QuantityTakeOff - Reference: SU-P-09 - 1000x2070
OverallHeight: 2070 mm; OverallWidth: 1000 mm; Material: EST. Metall. Alumiinium. Värvitud. RAL7023 (Concrete grey)

# IfcDoor: SMA_D01, 1-poolne:SU-P-09 - 1000x2090, SMA_D01, 1-poolne:SU-P-09 - 1000x2090:866955
In: 4 Korrus
Type - ParameterTakesPrecedence: no; Sizeable: no; Material: <Unnamed> (3), EST. Metall. Alumiinium. Värvitud. RAL7023 (Concrete grey) (3), EST. Klaas. 3x. Default
Type - Pset_ConcreteElementGeneral - FireRating: -
Type - Pset_DoorCommon - IsExternal: no; Reference: SU-P-09 - 1000x2090; FireRating: -; AcousticRating: 35dB
Type - Pset_ProductRequirements - Category: Doors
Type - Pset_QuantityTakeOff - Reference: SU-P-09 - 1000x2090
OverallHeight: 2090 mm; OverallWidth: 1000 mm; Material: EST. Metall. Alumiinium. Värvitud. RAL7023 (Concrete grey)
Pset_OpeningElementCommon - Reference: SU-P-09 - 1000x2090; sets with these values: 2

# IfcDoor: SMA_D01, 1-poolne:SU-P-10 - 1000x2000, SMA_D01, 1-poolne:SU-P-10 - 1000x2000:1102583
In: 0 Sokkel
Type - ParameterTakesPrecedence: no; Sizeable: no; Material: <Unnamed> (3), EST. Metall. Alumiinium. Värvitud. RAL7023 (Concrete grey), EST. Klaas. 3x. Default, __Aknaraam (2)
Type - Pset_ConcreteElementGeneral - FireRating: -
Type - Pset_DoorCommon - IsExternal: no; Reference: SU-P-10 - 1000x2000; FireRating: -; AcousticRating: 35dB
Type - Pset_ProductRequirements - Category: Doors
Type - Pset_QuantityTakeOff - Reference: SU-P-10 - 1000x2000
OverallHeight: 2000 mm; OverallWidth: 1000 mm; Material: EST. Metall. Alumiinium. Värvitud. RAL7023 (Concrete grey), __Aknaraam, EST. Klaas. 3x. Default
Pset_OpeningElementCommon - Reference: SU-P-10 - 1000x2000; sets with these values: 2

# IfcDoor: SMA_D01, 1-poolne:VU-01 - 1250x2100, SMA_D01, 1-poolne:VU-01 - 1250x2100:847334
In: 1 Korrus
Type - OperationType: SINGLE_SWING_LEFT; ParameterTakesPrecedence: no; Sizeable: no; Material: <Unnamed> (3), EST. Metall. Alumiinium. Värvitud. RAL7023 (Concrete grey) (4)
Type - SMA_D01, 1-poolne:VU-01 - 1250x2100:847334 - PanelOperation: SWINGING
Type - Pset_ConcreteElementGeneral - FireRating: -
Type - Pset_DoorCommon - IsExternal: no; Reference: VU-01 - 1250x2100; FireRating: -; AcousticRating: 30dB
Type - Pset_ProductRequirements - Category: Doors
Type - Pset_QuantityTakeOff - Reference: VU-01 - 1250x2100
OverallHeight: 2100 mm; OverallWidth: 1250 mm; Material: EST. Metall. Alumiinium. Värvitud. RAL7023 (Concrete grey)
Pset_OpeningElementCommon - Reference: VU-01 - 1250x2100; sets with these values: 2

# IfcDoor: SMA_D01, 1-poolne:VU-02 - 1000x2100, SMA_D01, 1-poolne:VU-02 - 1000x2100:847238
In: 1 Korrus
Type - OperationType: SINGLE_SWING_RIGHT; ParameterTakesPrecedence: no; Sizeable: no; Material: EST. Klaas. 3x. Default, EST. Metall. Alumiinium. Värvitud. RAL7023 (Concrete grey) (3), <Unnamed> (3)
Type - SMA_D01, 1-poolne:VU-02 - 1000x2100:847238 - PanelOperation: SWINGING
Type - Pset_ConcreteElementGeneral - FireRating: -
Type - Pset_DoorCommon - IsExternal: no; Reference: VU-02 - 1000x2100; FireRating: -; AcousticRating: 30dB
Type - Pset_ProductRequirements - Category: Doors
Type - Pset_QuantityTakeOff - Reference: VU-02 - 1000x2100
OverallHeight: 2100 mm; OverallWidth: 1050 mm; Material: EST. Metall. Alumiinium. Värvitud. RAL7023 (Concrete grey), EST. Klaas. 3x. Default
Pset_OpeningElementCommon - Reference: VU-02 - 1000x2100; sets with these values: 2

# IfcDoor: SMA_D02, 2-poolne:SU-AL-01 - 1500x2100, SMA_D02, 2-poolne:SU-AL-01 - 1500x2100:783124
In: 0 Sokkel
Type - ParameterTakesPrecedence: no; Sizeable: no; Material: EST. Metall. Plekk. Värvitud. RAL7023 (Concrete grey) (3), <Unnamed> (3), EST. Klaas. 3x. Default
Type - Pset_ConcreteElementGeneral - FireRating: EI-30
Type - Pset_DoorCommon - IsExternal: no; Reference: SU-AL-01 - 1500x2100; FireRating: EI-30; AcousticRating: -
Type - Pset_ProductRequirements - Category: Doors
Type - Pset_QuantityTakeOff - Reference: SU-AL-01 - 1500x2100
OverallHeight: 2100 mm; OverallWidth: 1500 mm; Material: EST. Metall. Plekk. Värvitud. RAL7023 (Concrete grey), EST. Klaas. 3x. Default

# IfcDoor: SMA_D02, 2-poolne:SU-AL-02 - 1400x2100 EI-30, SMA_D02, 2-poolne:SU-AL-02 - 1400x2100 EI-30:776660
In: 1 Korrus
Type - OperationType: SINGLE_SWING_RIGHT; ParameterTakesPrecedence: no; Sizeable: no; Material: <Unnamed> (3), EST. Metall. Plekk. Värvitud. RAL7023 (Concrete grey) (3), EST. Klaas. 3x. Default
Type - SMA_D02, 2-poolne:SU-AL-02 - 1400x2100 EI-30:776660 - PanelOperation: SWINGING
Type - Pset_ConcreteElementGeneral - FireRating: EI-30
Type - Pset_DoorCommon - IsExternal: no; Reference: SU-AL-02 - 1400x2100 EI-30; FireRating: EI-30; AcousticRating: -
Type - Pset_ProductRequirements - Category: Doors
Type - Pset_QuantityTakeOff - Reference: SU-AL-02 - 1400x2100 EI-30
OverallHeight: 2100 mm; OverallWidth: 1400 mm; Material: EST. Metall. Plekk. Värvitud. RAL7023 (Concrete grey)

# IfcDoor: SMA_D02, 2-poolne:SU-AL-03 - 1350x2100 (4)
Type - OperationType: SINGLE_SWING_RIGHT; ParameterTakesPrecedence: no; Sizeable: no; Material: <Unnamed> (3), EST. Metall. Plekk. Värvitud. RAL7023 (Concrete grey) (3), EST. Klaas. 3x. Default
Type - SMA_D02, 2-poolne:SU-AL-03 - 1350x2100:774996 - PanelOperation: SWINGING
Type - Pset_ConcreteElementGeneral - FireRating: EI-30
Type - Pset_DoorCommon - IsExternal: no; Reference: SU-AL-03 - 1350x2100; FireRating: EI-30; AcousticRating: -
Type - Pset_ProductRequirements - Category: Doors
Type - Pset_QuantityTakeOff - Reference: SU-AL-03 - 1350x2100
OverallHeight: 2100 mm; OverallWidth: 1350 mm; Material: EST. Metall. Plekk. Värvitud. RAL7023 (Concrete grey), EST. Klaas. 3x. Default
Name (SMA_D02, 2-poolne:SU-AL-03 - 1350x2100:...) | In
774996 | 1 Korrus
780030 | 2 Korrus | Pset_OpeningElementCommon - Reference: SU-AL-03 - 1350x2100; sets with these values: 2
780763 | 3 Korrus
780823 | 4 Korrus | Pset_OpeningElementCommon - Reference: SU-AL-03 - 1350x2100; sets with these values: 2

# IfcDoor: SMA_D02, 2-poolne:SU-AL-03 - 1350x2100 (3)
Type - ParameterTakesPrecedence: no; Sizeable: no; Material: EST. Metall. Plekk. Värvitud. RAL7023 (Concrete grey) (3), <Unnamed> (3), EST. Klaas. 3x. Default
Type - Pset_ConcreteElementGeneral - FireRating: EI-30
Type - Pset_DoorCommon - IsExternal: no; Reference: SU-AL-03 - 1350x2100; FireRating: EI-30; AcousticRating: -
Type - Pset_ProductRequirements - Category: Doors
Type - Pset_QuantityTakeOff - Reference: SU-AL-03 - 1350x2100
OverallHeight: 2100 mm; OverallWidth: 1350 mm; Material: EST. Metall. Plekk. Värvitud. RAL7023 (Concrete grey), EST. Klaas. 3x. Default
Name (SMA_D02, 2-poolne:SU-AL-03 - 1350x2100:...) | In
780028 | 2 Korrus
780761 | 3 Korrus
780821 | 4 Korrus

# IfcDoor: SMA_D02, 2-poolne:SU-AL-04 - 1600x2100, SMA_D02, 2-poolne:SU-AL-04 - 1600x2100:846940
In: Sissepääs
Type - ParameterTakesPrecedence: no; Sizeable: no; Material: EST. Metall. Plekk. Värvitud. RAL7023 (Concrete grey) (3), <Unnamed> (3), EST. Klaas. 3x. Default
Type - Pset_ConcreteElementGeneral - FireRating: -
Type - Pset_DoorCommon - IsExternal: no; Reference: SU-AL-04 - 1600x2100; FireRating: -; AcousticRating: -
Type - Pset_ProductRequirements - Category: Doors
Type - Pset_QuantityTakeOff - Reference: SU-AL-04 - 1600x2100
OverallHeight: 2190 mm; OverallWidth: 1600 mm; Material: EST. Metall. Plekk. Värvitud. RAL7023 (Concrete grey), EST. Klaas. 3x. Default

# IfcDoor: SMA_D02, 2-poolne:SU-AL-04 - 1600x2100, SMA_D02, 2-poolne:SU-AL-04 - 1600x2100:1080265
In: Sissepääs
Type - ParameterTakesPrecedence: no; Sizeable: no; Material: EST. Metall. Plekk. Värvitud. RAL7023 (Concrete grey) (3), EST. Klaas. 3x. Default, <Unnamed> (3)
Type - Pset_ConcreteElementGeneral - FireRating: -
Type - Pset_DoorCommon - IsExternal: no; Reference: SU-AL-04 - 1600x2100; FireRating: -; AcousticRating: -
Type - Pset_ProductRequirements - Category: Doors
Type - Pset_QuantityTakeOff - Reference: SU-AL-04 - 1600x2100
OverallHeight: 2190 mm; OverallWidth: 1600 mm; Material: EST. Metall. Plekk. Värvitud. RAL7023 (Concrete grey), EST. Klaas. 3x. Default
Pset_OpeningElementCommon - Reference: SU-AL-04 - 1600x2100; sets with these values: 2

# IfcDoor: SMA_D02, 2-poolne:SU-M-05 - 1800x2100, SMA_D02, 2-poolne:SU-M-05 - 1800x2100:1067058
In: 0 Sokkel
Type - ParameterTakesPrecedence: no; Sizeable: no; Material: <Unnamed> (3), EST. Metall. Plekk. Värvitud. RAL7023 (Concrete grey) (3), EST. Klaas. 3x. Default
Type - Pset_ConcreteElementGeneral - FireRating: EI-30
Type - Pset_DoorCommon - IsExternal: no; Reference: SU-M-05 - 1800x2100; FireRating: EI-30; AcousticRating: -
Type - Pset_ProductRequirements - Category: Doors
Type - Pset_QuantityTakeOff - Reference: SU-M-05 - 1800x2100
OverallHeight: 2100 mm; OverallWidth: 1800 mm; Material: EST. Metall. Plekk. Värvitud. RAL7023 (Concrete grey)

# IfcDoor: SMA_D02, 2-poolne:VU-AL-03- 1600x2100, SMA_D02, 2-poolne:VU-AL-03- 1600x2100:779409
In: 1 Korrus
Type - OperationType: DOUBLE_DOOR_SINGLE_SWING; ParameterTakesPrecedence: no; Sizeable: no; Material: EST. Metall. Plekk. Värvitud. RAL7023 (Concrete grey) (3), <Unnamed> (3), EST. Klaas. 3x. Default
Type - SMA_D02, 2-poolne:VU-AL-03- 1600x2100:779409 - PanelOperation: SWINGING
Type - Pset_ConcreteElementGeneral - FireRating: -
Type - Pset_DoorCommon - IsExternal: no; Reference: VU-AL-03- 1600x2100; FireRating: -; AcousticRating: 30dB
Type - Pset_ProductRequirements - Category: Doors
Type - Pset_QuantityTakeOff - Reference: VU-AL-03- 1600x2100
OverallHeight: 2150 mm; OverallWidth: 1600 mm; Material: EST. Metall. Plekk. Värvitud. RAL7023 (Concrete grey), EST. Klaas. 3x. Default

# IfcDoor: sma_D01:SU-KL-01 - 700x2000 SAUN KLAAS (2)
In: 0 Sokkel
Type - ParameterTakesPrecedence: no; Sizeable: no; Material: <Unnamed> (3), Glass (2), Metal - Aluminium, __Aknaraam
Type - Pset_ConcreteElementGeneral - FireRating: -
Type - Pset_DoorCommon - IsExternal: no; Reference: SU-KL-01 - 700x2000 SAUN KLAAS; FireRating: -; AcousticRating: -
Type - Pset_ProductRequirements - Category: Doors
Type - Pset_QuantityTakeOff - Reference: SU-KL-01 - 700x2000 SAUN KLAAS
OverallHeight: 2000 mm; OverallWidth: 700 mm; Material: Metal - Aluminium, __Aknaraam, Glass
Pset_OpeningElementCommon - Reference: SU-KL-01 - 700x2000 SAUN KLAAS; sets with these values: 2
Name (sma_D01:SU-KL-01 - 700x2000 SAUN KLAAS:...)
885303
1037578

# IfcFlowSegment: Gutter:Gutter:19886, Gutter:Gutter:901488
In: Katus
Type - ElementType: Gutter:Gutter:19886; PredefinedType: GUTTER
Pset_DistributionFlowElementCommon - Reference: Gutter; sets with these values: 2
Pset_FlowSegmentDuctSegment - Length: 63878.7 mm; sets with these values: 2
Pset_PipeSegmentTypeGutter - Slope: 0 deg
Pset_ProductRequirements - Category: Gutters

# IfcFlowTerminal: Dušši segisti:SA-00 - Dušš Oras Nova + Apollo 530 ECO (7)
Type - Classification: D2010 Plumbing Fixtures (Uniformat); Material: Gustavsberg Chrome - Polished
Type - Pset_ManufacturerTypeInformation - Manufacturer: Oras+Apollo
Type - Pset_ProductRequirements - Category: Plumbing Fixtures
Type - Pset_QuantityTakeOff - Reference: SA-00 - Dušš Oras Nova + Apollo 530 ECO
Pset_DistributionFlowElementCommon - Reference: SA-00 - Dušš Oras Nova + Apollo 530 ECO; sets with these values: 3
Pset_ManufacturerTypeInformation - sets with these values: 2
Pset_ProductRequirements - sets with these values: 2
Name (Dušši segisti:SA-00 - Dušš Oras Nova + Apollo 530 ECO:...) | In
893462 | 0-11
894493 | 0-11
894641 | 0-11
894926 | 0-8
894928 | 0-8
1082817 | 0-8
1082912 | 0-11

# IfcFlowTerminal: PRD_FrankeWS_WlHngWshBsns_AnimaWashbasin_WT400A,WT400A-M:WT400A-M (3)
Type - PredefinedType: WASHHANDBASIN; Material: PRD_FrankeWS_StainlessSteel_SatinFinished (2)
Type - Pset_DistributionFlowElementCommon - Reference: WT400A-M
Type - Pset_ElementShading - Color: Stainless steel
Type - Pset_ManufacturerTypeInformation - ModelReference: WT400A-M; Manufacturer: FRANKE Water Systems AG
Type - Pset_ProductRequirements - Name: ANIMA wall-hung wash basin WT400A-M; Category: Plumbing Fixtures
Type - Pset_QuantityTakeOff - Reference: WT400A-M
Material: PRD_FrankeWS_StainlessSteel_SatinFinished
Pset_DistributionFlowElementCommon - sets with these values: 2
Pset_ManufacturerOccurrence - BarCode: n/a; SerialNumber: n/a
Name (PRD_FrankeWS_WlHngWshBsns_AnimaWashbasin_WT400A,WT400A-M:WT400A-M:...) | In
801374 | 0-14
918148 | 0-20
1213923 | 0-16

# IfcFlowTerminal: SMA_Pro A allas 28x48cm:SA-00 - Laufen Pro 480 + Oras Saga, SMA_Pro A allas 28x48cm:SA-00 - Laufen Pro 480 + Oras Saga:1040867
In: 0-27
Type - Material: Chrome, Duravit Keramik
Type - Pset_ManufacturerTypeInformation - ArticleNumber: PL8159550001041F; Manufacturer: Laufen+Oras
Type - Pset_ProductRequirements - Category: Plumbing Fixtures
Type - Pset_QuantityTakeOff - Reference: SA-00 - Laufen Pro 480 + Oras Saga
Pset_DistributionFlowElementCommon - Reference: SA-00 - Laufen Pro 480 + Oras Saga; sets with these values: 3
Pset_ManufacturerTypeInformation - sets with these values: 2
Pset_ProductRequirements - sets with these values: 2

# IfcFlowTerminal: SMA_Pro A allas 28x48cm:SA-00 - Laufen Pro 480 + Oras Saga, SMA_Pro A allas 28x48cm:SA-00 - Laufen Pro 480 + Oras Saga:1040868
In: 0-26
Type - Material: Duravit Keramik, Chrome
Type - Pset_ManufacturerTypeInformation - ArticleNumber: PL8159550001041F; Manufacturer: Laufen+Oras
Type - Pset_ProductRequirements - Category: Plumbing Fixtures
Type - Pset_QuantityTakeOff - Reference: SA-00 - Laufen Pro 480 + Oras Saga
Material: Chrome, Duravit Keramik
Pset_DistributionFlowElementCommon - Reference: SA-00 - Laufen Pro 480 + Oras Saga; sets with these values: 3
Pset_ManufacturerTypeInformation - sets with these values: 2
Pset_ProductRequirements - sets with these values: 2

# IfcFlowTerminal: WC-GBG-Nautic_5530-Wall_Mounted:Standard seat (2)
Type - Classification: D2010100 Water Closets (Uniformat); Material: Gustavsberg Porcelain - White
Type - Pset_ManufacturerTypeInformation - ArticleNumber: GB115530001010; Manufacturer: Villeroy & Boch Gustavsberg AB
Type - Pset_ProductRequirements - Category: Plumbing Fixtures
Type - Pset_QuantityTakeOff - Reference: Standard seat
Pset_DistributionFlowElementCommon - Reference: Standard seat; sets with these values: 3
Pset_ManufacturerTypeInformation - sets with these values: 2
Pset_ProductRequirements - sets with these values: 2
Name (WC-GBG-Nautic_5530-Wall_Mounted:Standard seat:...) | In
1040856 | 0-27
1040857 | 0-26

# IfcFlowTerminal: WC-GBG-Nautic_5530-Wall_Mounted:Without seat (25)
Type - Classification: D2010100 Water Closets (Uniformat); Material: Gustavsberg Porcelain - White
Type - Pset_ManufacturerTypeInformation - ArticleNumber: GB115530001000; Manufacturer: Villeroy & Boch Gustavsberg AB
Type - Pset_ProductRequirements - Category: Plumbing Fixtures
Type - Pset_QuantityTakeOff - Reference: Without seat
Pset_DistributionFlowElementCommon - Reference: Without seat; sets with these values: 3
Pset_ManufacturerTypeInformation - sets with these values: 2
Pset_ProductRequirements - sets with these values: 2
Name (WC-GBG-Nautic_5530-Wall_Mounted:Without seat:...) | In
816834 | 1-11
819935 | 1-37
828721 | 1-26
828854 | 1-27
839856 | 1-34
843473 | 1-17
849649 | 2-11
849653 | 2-26
849655 | 2-27
849657 | 2-2
849661 | 2-17
866612 | 3-11
866613 | 3-26
866614 | 3-27
866616 | 3-17
866624 | 4-11
866625 | 4-26
866626 | 4-28
866628 | 4-17
1087120 | 1-19
1090002 | 2-19
1090435 | 3-19
1090476 | 4-19
1096048 | 3-2
1101381 | 4-2

# IfcFlowTerminal: vannisegisti 1:Umyvadlová - páková (4)
Type - Pset_ProductRequirements - Category: Plumbing Fixtures
Type - Pset_QuantityTakeOff - Reference: Umyvadlová - páková
Pset_DistributionFlowElementCommon - Reference: Umyvadlová - páková
Name (vannisegisti 1:Umyvadlová - páková:...) | In | Pset_DistributionFlowElementCommon, sets with these values | Pset_ProductRequirements, sets with these values
796674 | 1-21 | 2
1163441 | 2-21 | 3 | 2
1163445 | 3-21 | 3 | 2
1163455 | 4-21 | 3 | 2

# IfcFurnishingElement: Exercise_Bike_4766:Exercise_Bike_4766, Exercise_Bike_4766:Exercise_Bike_4766:922684
In: 0-3
Type - Material: plastic 2
Type - Pset_ProductRequirements - Category: Furniture
Type - Pset_QuantityTakeOff - Reference: Exercise_Bike_4766
Material: plastic 2, Plastic, Plastic - Black, Metal - Chrome, plastic 3

# IfcFurnishingElement: Furniture_Chairs_Great-Openings_Sparkeology-SLY_Chair:Standard (36)
Type - Material: Wood - Birch_tume, Plastic - Great Openings_Sparkeology - Black, __Metall 1
Type - Pset_FurnitureTypeCommon - Description: Juno tool, art 3600 või sellega samaväärne toode. Nelja jalaga polüpropüleenist avatud seljaavaga toon tumehall PT00005, Pilt on illustratiivse tähendusega ja toodud näidisena; NominalHeight: 831.85 mm
Type - Pset_ManufacturerTypeInformation - Manufacturer: Elke
Type - Pset_ProductRequirements - Category: Furniture
Type - Pset_QuantityTakeOff - Reference: Standard
Material: Plastic - Great Openings_Sparkeology - Black, __Metall 1, Wood - Birch_tume
Name (Furniture_Chairs_Great-Openings_Sparkeology-SLY_Chair:Standard:...) | In
825596 | 2-10
825621 | 2-10
826586 | 2-16
826587 | 2-16
844536 | 2-18
844687 | 2-18
849146 | 3-10
849147 | 3-10
849150 | 3-16
849151 | 3-16
849153 | 3-18
849154 | 3-18
854564 | 3-3
854565 | 3-3
855926 | 3-28
855927 | 3-28
863762 | 4-10
863763 | 4-10
863766 | 4-16
863767 | 4-16
863769 | 4-18
863770 | 4-18
863772 | 4-3
863773 | 4-3
863775 | 4-27
863776 | 4-27
863779 | 4 Korrus
863780 | 4 Korrus
863783 | 4 Korrus
863784 | 4 Korrus
863786 | 4 Korrus
863787 | 4 Korrus
863789 | 4 Korrus
863790 | 4 Korrus
863792 | 4 Korrus
863793 | 4 Korrus

# IfcFurnishingElement: Furniture_Chairs_Great-Openings_Sparkeology-SLY_Chair:Standard (22)
Type - Material: __Metall 1, Plastic - Great Openings_Sparkeology - Black, Wood - Birch_tume
Type - Pset_FurnitureTypeCommon - Description: Juno tool, art 3600 või sellega samaväärne toode. Nelja jalaga polüpropüleenist avatud seljaavaga toon tumehall PT00005, Pilt on illustratiivse tähendusega ja toodud näidisena; NominalHeight: 831.85 mm
Type - Pset_ManufacturerTypeInformation - Manufacturer: Elke
Type - Pset_ProductRequirements - Category: Furniture
Type - Pset_QuantityTakeOff - Reference: Standard
Material: Plastic - Great Openings_Sparkeology - Black, __Metall 1, Wood - Birch_tume
Name (Furniture_Chairs_Great-Openings_Sparkeology-SLY_Chair:Standard:...) | In
821816 | 2-10
825622 | 2-10
826585 | 2-16
826588 | 2-16
849145 | 3-10
849148 | 3-10
849149 | 3-16
849152 | 3-16
854563 | 3-3
854566 | 3-3
863761 | 4-10
863764 | 4-10
863765 | 4-16
863768 | 4-16
863771 | 4-3
863774 | 4-3
863778 | 4 Korrus
863781 | 4 Korrus
863782 | 4 Korrus
863785 | 4 Korrus
863788 | 4 Korrus
863791 | 4 Korrus

# IfcFurnishingElement: Kasarmu voodi ühekordne 2308x830:Kasarmu voodi ühekordne 2308x830 (134)
Type - Material: Madrats
Type - Pset_FurnitureTypeCommon - Description: Töölaud CRATE abilaua ja lisalauaga või sellega samaväärne toode. - lauaplaat CRLAL1610FA(B)käelisust vaata plaanilt, 1640x800/1000x740mm, melamiinplaat 22mm/ABS kant 2mm - toon latte; - U-jalaraam, metallist nelikanttoru 40x40, toruseina paksus 2mm, raamjalg pulbervärvitud hõbehall RAL9006 H:740mm, jalgade otstes reguleerimiseks plastkork, lauaplaadi all kaks metallsarja, metallraam ühendatud poltühendusega, metallraami ja lauaplaadi vahel 10mm distants; - Lisalaud CRLL0707A(B) käelisus vaata plaanilt, 700x700mm, toon latte, - abilaud CRLAK1006FKP, kinnitatakse tööpinna külge, toon latte; - laekakapp PALK8 424x575(H)x600mm pliiatsilaekaga PALSPLK (korpus melamiin valge 18mm, ABS kant valge 2mm, fassaad ja pealisplaat latte 16mm, ABS kant 2mm) kesklukuga; - abikapp 1600x666(H)x446mm PAAK3A/PAAK3B korpus valge melamiin 18mm, valge ABS kant 2mm, fassaad ja pealisplaat latte 16mm, ABS kant 2mm); ava töölauas rosett LSR2. Lauaplaadi ala- ja ülaserv pehmendatud (R3mm), välisnurkadele anda ümardus. Kõik keevised lihvitud, servad ja nurgad pehmendatud.
Type - Pset_ManufacturerTypeInformation - Manufacturer: Standard
Type - Pset_ProductRequirements - Category: Furniture
Type - Pset_QuantityTakeOff - Reference: Kasarmu voodi ühekordne 2308x830
Name (Kasarmu voodi ühekordne 2308x830:Kasarmu voodi ühekordne 2308x830:...) | In
791363 | 1-12
793662 | 1-12
794427 | 1-14
811269 | 1-8
811414 | 1-7
812036 | 1-8
818825 | 1-13
818873 | 1-13
819228 | 1-7
819409 | 1-6
819445 | 1-6
825998 | 1-9
826175 | 1-9
826863 | 1-14
831386 | 1-22
831925 | 1-22
832617 | 1-23
832635 | 1-23
833705 | 1-24
834203 | 1-24
835689 | 1-29
835697 | 1-29
835751 | 1-30
835800 | 1-31
835808 | 1-31
835855 | 1-30
837499 | 1-20/1
838114 | 1-33
838307 | 1-33
843204 | 1-20/2
845464 | 1-15
845587 | 1-15
848787 | 2-12
848788 | 2-12
848789 | 2-14
848791 | 2-8
848792 | 2-7
848793 | 2-8
848794 | 2-13
848795 | 2-13
848796 | 2-7
848797 | 2-6
848798 | 2-6
848799 | 2-9
848800 | 2-9
848801 | 2-14
848802 | 2-22
848803 | 2-22
848806 | 2-24
848807 | 2-24
848808 | 2-29
848809 | 2-29
848816 | 2-31/1
848817 | 2-31/1
848819 | 2-15
848820 | 2-15
852039 | 2-31
852187 | 2-31
852934 | 2-30
852935 | 2-30
853137 | 2-23
853138 | 2-23
854669 | 2-1
854902 | 2-1
860124 | 2-20/1
860129 | 2-20/2
864991 | 3-12
864992 | 3-12
864993 | 3-14
864994 | 3-8
864995 | 3-7
864996 | 3-8
864997 | 3-13
864998 | 3-13
864999 | 3-7
865000 | 3-6
865001 | 3-6
865002 | 3-9
865003 | 3-9
865004 | 3-14
865005 | 3-22
865006 | 3-22
865007 | 3-24
865008 | 3-24
865009 | 3-29
865010 | 3-29
865011 | 3-31/1
865012 | 3-31/1
865013 | 3-15
865014 | 3-15
865015 | 3-31
865016 | 3-31
865017 | 3-30
865018 | 3-30
865019 | 3-23
865020 | 3-23
865021 | 3-1
865022 | 3-1
865023 | 3-20/1
865024 | 3-20/2
866518 | 4-12
866519 | 4-12
866520 | 4-14
866521 | 4-8
866522 | 4-7
866523 | 4-8
866524 | 4-13
866525 | 4-13
866526 | 4-7
866527 | 4-6
866528 | 4-6
866529 | 4-9
866530 | 4-9
866531 | 4-14
866532 | 4-22
866533 | 4-22
866534 | 4-24
866535 | 4-24
866536 | 4-29
866537 | 4-29
866538 | 4-31/1
866539 | 4-31/1
866540 | 4-15
866541 | 4-15
866542 | 4-31
866543 | 4-31
866544 | 4-30
866545 | 4-30
866546 | 4-23
866547 | 4-23
866549 | 4-1
866550 | 4-20/1
866551 | 4-20/2
1065299 | 4-1

# IfcFurnishingElement: M_Chair-Executive:M_Chair-Executive (10)
Type - Material: Plastic - Black (2), Textile - Slate Blue
Type - Pset_FurnitureTypeCommon - Description: Töötool IDEA või sellega samaväärne toode, Kattematerjal - Iste ja seljatugi polsterdatud kangaga Politex (50 000 Martindale), - Sünkroonmehhanism- Kiike jäikuse reguleerimine, vastavalt istuja kaalule. Istme kõrguse reguleerimine gaasamordiga. Kõrguses ja laiuses reguleeritavad käetoed.Jalarist must plastik, Pehmed rattad kõvadele põrandatele - ISO 9001, ISO 14001. Kõrgus 1180-1300 mm, Istme kõrgus 420-540 mm, Istme sügavus 460-590 mm, Istme laius 440 mm, Jalarist Ø 700 mm
Type - Pset_ManufacturerTypeInformation - Manufacturer: Standard
Type - Pset_ProductRequirements - Category: Furniture
Type - Pset_QuantityTakeOff - Reference: M_Chair-Executive
Material: Plastic - Black, Textile - Slate Blue
Name (M_Chair-Executive:M_Chair-Executive:...) | In
835696 | 1-29
848912 | 2-29
852453 | 2-31
853140 | 2-23
865716 | 3-29
865720 | 3-31
865721 | 3-23
865736 | 4-29
865740 | 4-31
865741 | 4-23

# IfcFurnishingElement: M_Chair-Executive:M_Chair-Executive (65)
Type - Material: Textile - Slate Blue, Plastic - Black (2)
Type - Pset_FurnitureTypeCommon - Description: Töötool IDEA või sellega samaväärne toode, Kattematerjal - Iste ja seljatugi polsterdatud kangaga Politex (50 000 Martindale), - Sünkroonmehhanism- Kiike jäikuse reguleerimine, vastavalt istuja kaalule. Istme kõrguse reguleerimine gaasamordiga. Kõrguses ja laiuses reguleeritavad käetoed.Jalarist must plastik, Pehmed rattad kõvadele põrandatele - ISO 9001, ISO 14001. Kõrgus 1180-1300 mm, Istme kõrgus 420-540 mm, Istme sügavus 460-590 mm, Istme laius 440 mm, Jalarist Ø 700 mm
Type - Pset_ManufacturerTypeInformation - Manufacturer: Standard
Type - Pset_ProductRequirements - Category: Furniture
Type - Pset_QuantityTakeOff - Reference: M_Chair-Executive
Material: Plastic - Black, Textile - Slate Blue
Name (M_Chair-Executive:M_Chair-Executive:...) | In
812426 | 1-8
819384 | 1-7
819393 | 1-6
826477 | 1-9
826914 | 1-12
826920 | 1-13
826958 | 0-8
833583 | 1-23
833818 | 1-24
834645 | 1-22
835753 | 1-30
835807 | 1-31
839185 | 1-33
842608 | 1-20/2
842619 | 1-20/1
845888 | 1-15
845922 | 1-15
848902 | 2-8
848903 | 2-7
848904 | 2-6
848905 | 2-9
848906 | 2-12
848907 | 2-13
848908 | 2-14
848910 | 2-24
848911 | 2-22
848915 | 2-31/1
848918 | 2-15
848919 | 2-15
853526 | 2-30
855380 | 2-1
860126 | 2-20/2
860128 | 2-20/1
865707 | 3-8
865708 | 3-7
865709 | 3-6
865710 | 3-9
865711 | 3-12
865712 | 3-13
865713 | 3-14
865714 | 3-24
865715 | 3-22
865717 | 3-31/1
865718 | 3-15
865719 | 3-15
865722 | 3-30
865723 | 3-1
865724 | 3-20/2
865725 | 3-20/1
865727 | 4-8
865728 | 4-7
865729 | 4-6
865730 | 4-9
865731 | 4-12
865732 | 4-13
865733 | 4-14
865734 | 4-24
865735 | 4-22
865737 | 4-31/1
865738 | 4-15
865739 | 4-15
865742 | 4-30
865743 | 4-1
865744 | 4-20/2
865745 | 4-20/1

# IfcFurnishingElement: Treadmill_8126:Treadmill_8126, Treadmill_8126:Treadmill_8126:922685
In: 0-3
Type - Material: <Unnamed> (2)
Type - Pset_FurnitureTypeCommon - Description: Jooksulint Gilavar, maksimaalne kiirus kuni 22 km/h jooksulindi mootori võimsus: 3,5 HP võimalus muuta kallakut kuni 22% maksimaalne kasutaja kaal 150 kg trenažööri kaal 97 kg kompuuter näitab distantsi, aega, kiirust, pulssi, põletatud kaloreid
Type - Pset_ManufacturerTypeInformation - Manufacturer: inSPORTline
Type - Pset_ProductRequirements - Category: Furniture
Type - Pset_QuantityTakeOff - Reference: Treadmill_8126

# IfcFurnishingElement: ZED2.dwg:ZED2.dwg (4)
In: 0-2
Type - Material: Laminate, Ivory, Matte, __Metal Tumehall
Type - Pset_FurnitureTypeCommon - Description: Diivan ZEETA või sellega samaväärne toode. Diivan ZED3, metalljalad RAL9005, must. Polstri porolooni tulekindlus SK1, mahukaal 35kg/m3, kõvadus 150N±15%. Kanga kulumiskindlus vähemalt 100000 Martindale, tulekindlus vähemalt EN1021-1/2. Kangas - küljed ja põhi Gabriel Step Melange 64178, istumine Gabriel Step Melange 66019 (tumehall). Pilt on illustratiivse tähendusega ja toodud näidisena.
Type - Pset_ManufacturerTypeInformation - Manufacturer: Standard
Type - Pset_ProductRequirements - Category: Furniture
Type - Pset_QuantityTakeOff - Reference: ZED2.dwg
Name (ZED2.dwg:ZED2.dwg:...)
1041836
1041837
1041840
1041842

# IfcFurnishingElement: ZESP2 ZEETA SIRGE DIIVAN.0001:B korpuse kapp, ZESP2 ZEETA SIRGE DIIVAN.0001:B korpuse kapp:1041838
In: 0-2
Type - Material: Laminate, Ivory, Matte (2)
Type - Pset_FurnitureTypeCommon - Description: Diivanilaud Zeeta või sellega samaväärne toode. - lauaplaat 1300x700x22mm, melamiinplaat valgendatud saar; - U-jalaraam, metallist nelikanttoru 40x40, toruseina paksus 2mm, raamjalg pulbervärvitud must RAL9005, jalgade otstes reguleerimiseks plastkork, lauaplaadi all kaks metallsarja, metallraam ühendatud poltühendusega, metallraami ja lauaplaadi vahel 10mm distants; Pilt on illustratiivse tähendusega ja toodud näidisena
Type - Pset_ManufacturerTypeInformation - Manufacturer: Standard
Type - Pset_ProductRequirements - Category: Furniture
Type - Pset_QuantityTakeOff - Reference: B korpuse kapp

# IfcFurnishingElement: kirjutuslaud 1360x700mm:kirjutuslaud 1360x700mm (75)
Type - Material: <Unnamed> (2)
Type - Pset_FurnitureTypeCommon - Description: töölaud PIANO U, laekakapiga või sellega samaväärne toode. - lauaplaat PALPK1206 1200x600x22mm, melamiinplaat 22mm/ABS kant 2mm - toon valgendatud saar; - U-jalaraam, metallist nelikanttoru 40x40, toruseina paksus 2mm, raamjalg pulbervärvitud must RAL9005 H:740mm, jalgade otstes reguleerimiseks plastkork, lauaplaadi all kaks metallsarja, metallraam ühendatud poltühendusega, metallraami ja lauaplaadi vahel 10mm distants; - laekakapp PALK5 424x740(H)x600mm pliiatsilaekaga PALSPLK (korpus melamiin valge 18mm, ABS kant valge 2mm, fassaad ja pealisplaat valgentatud saar 16mm, ABS kant 2mm) kesklukuga; ava töölauas rosett LSR2. Lauaplaadi ala- ja ülaserv pehmendatud (R3mm), välisnurkadele anda ümardus. Kõik keevised lihvitud, servad ja nurgad pehmendatud. Pilt on illustratiivse tähendusega ja toodud näidisena. Tooted peavad olema testitud ja vastama Euroopa normidele NE 527-1:2000, NE 521-2:2003, EN521-3:2003 Pilt on illustratiivse tähendusega ja toodud näidisena.
Type - Pset_ManufacturerTypeInformation - Manufacturer: Standard
Type - Pset_ProductRequirements - Category: Furniture
Type - Pset_QuantityTakeOff - Reference: kirjutuslaud 1360x700mm
Name (kirjutuslaud 1360x700mm:kirjutuslaud 1360x700mm:...) | In
792973 | 1-12
794147 | 1-13
811707 | 1-8
819383 | 1-7
819392 | 1-6
826476 | 1-9
826957 | 1-14
832437 | 1-23
833807 | 1-24
834644 | 1-22
835690 | 1-29
835752 | 1-30
835801 | 1-31
839184 | 1-33
842607 | 1-20/2
842618 | 1-20/1
845887 | 1-15
845921 | 1-15
848830 | 2-12
848831 | 2-13
848832 | 2-8
848833 | 2-7
848834 | 2-6
848835 | 2-9
848836 | 2-14
848838 | 2-24
848839 | 2-22
848840 | 2-29
848843 | 2-31/1
848846 | 2-15
848847 | 2-15
852452 | 2-31
853139 | 2-23
853525 | 2-30
855100 | 2-1
860125 | 2-20/2
860127 | 2-20/1
865659 | 3-12
865660 | 3-13
865661 | 3-8
865662 | 3-7
865663 | 3-6
865664 | 3-9
865665 | 3-14
865666 | 3-24
865667 | 3-22
865668 | 3-29
865669 | 3-31/1
865670 | 3-15
865671 | 3-15
865672 | 3-31
865673 | 3-23
865674 | 3-30
865675 | 3-1
865676 | 3-20/2
865677 | 3-20/1
865679 | 4-12
865680 | 4-13
865681 | 4-8
865682 | 4-7
865683 | 4-6
865684 | 4-9
865685 | 4-14
865686 | 4-24
865687 | 4-22
865688 | 4-29
865689 | 4-31/1
865690 | 4-15
865691 | 4-15
865692 | 4-31
865693 | 4-23
865694 | 4-30
865695 | 4-1
865696 | 4-20/2
865697 | 4-20/1

# IfcFurnishingElement: laud_1200x800:laud_1200x800 (15)
Type - Material: Metal - Stud Layer, <Unnamed>
Type - Pset_FurnitureTypeCommon - Description: laud 1200x740(H)x800 või sellega samaväärne toode. Lauaplaat 1200mm, paksus 22mm, puitlaastplaat kaetud mööbli Linoleumiga (Forbo furniture linoleum desktop - 2mm, toon 4184 olive, kuumtöötlusega valatud 4mm polüuretaankant hall 95, metallist jalg 40x40, toruseina paksus 2mm, raamjalg pulbervärvitud must RAL9005 H:740mm, jalgade otstes reguleerimiseks plastkork, lauaplaadi all kaks metallsarja, metallraam ühendatud poltühendusega, metallraami ja lauaplaadi vahel 10mm distants, Lauaplaadi ala- ja ülaserv pehmendatud (R3mm), välisnurkadele anda ümardus. Kõik keevised lihvitud, servad ja nurgad pehmendatud. Pilt on illustratiivse tähendusega ja toodud näidisena.
Type - Pset_ManufacturerTypeInformation - Manufacturer: Standard
Type - Pset_ProductRequirements - Category: Furniture
Type - Pset_QuantityTakeOff - Reference: laud_1200x800
Material: Metal - Stud Layer
Name (laud_1200x800:laud_1200x800:...) | In
821483 | 1-10
826584 | 1-16
843952 | 1-18
849099 | 2-10
849100 | 2-16
849101 | 2-18
854562 | 2-3
865755 | 3-10
865756 | 3-16
865757 | 3-18
865758 | 3-3
865760 | 4-10
865761 | 4-16
865762 | 4-18
865763 | 4-3

# IfcFurnishingElement: varbsein 1,00x2.30:varbsein 1,00x2.30, varbsein 1,00x2.30:varbsein 1,00x2.30:926198
In: 0-3
Type - Pset_FurnitureTypeCommon - Description: Puidust varbsein ovaalsete pulkadega. Peab vastama EN913 standardile.
Type - Pset_ManufacturerTypeInformation - Manufacturer: Tommi Play
Type - Pset_ProductRequirements - Category: Furniture
Type - Pset_QuantityTakeOff - Reference: varbsein 1,00x2.30

# IfcFurnishingElement: zeeta.2A:zeeta.2A, zeeta.2A:zeeta.2A:1041841
In: 0-2
Type - Material: __Aknaraam, __Metall 1, + Melamiin hall
Type - Pset_FurnitureTypeCommon - Description: Diivan ZEETA või sellega samaväärne toode. Diivan ZED2A, metalljalad RAL9005, must. Polstri porolooni tulekindlus SK1, mahukaal 35kg/m3, kõvadus 150N±15%. Kanga kulumiskindlus vähemalt 100000 Martindale, tulekindlus vähemalt EN1021-1/2. Kangas - küljed ja põhi Gabriel Step 64178, istumine Gabriel Step Melange 66019 (tume hall). Pilt on illustratiivse tähendusega ja toodud näidisena.
Type - Pset_ManufacturerTypeInformation - Manufacturer: Standard
Type - Pset_ProductRequirements - Category: Furniture
Type - Pset_QuantityTakeOff - Reference: zeeta.2A

# IfcFurnishingElement: zeeta.2A:zeeta.2A, zeeta.2A:zeeta.2A:1041839
In: 0-2
Type - Material: __Metall 1, + Melamiin hall, __Aknaraam
Type - Pset_FurnitureTypeCommon - Description: Diivan ZEETA või sellega samaväärne toode. Diivan ZED2A, metalljalad RAL9005, must. Polstri porolooni tulekindlus SK1, mahukaal 35kg/m3, kõvadus 150N±15%. Kanga kulumiskindlus vähemalt 100000 Martindale, tulekindlus vähemalt EN1021-1/2. Kangas - küljed ja põhi Gabriel Step 64178, istumine Gabriel Step Melange 66019 (tume hall). Pilt on illustratiivse tähendusega ja toodud näidisena.
Type - Pset_ManufacturerTypeInformation - Manufacturer: Standard
Type - Pset_ProductRequirements - Category: Furniture
Type - Pset_QuantityTakeOff - Reference: zeeta.2A

# IfcMember: Rectangular Mullion:50 x 100mm (32)
Type - PredefinedType: MULLION; Material: __Aknaraam
Type - Pset_MemberCommon - IsExternal: no; Reference: 50 x 100mm
Type - Pset_ProductRequirements - Category: Curtain Wall Mullions
Type - Pset_QuantityTakeOff - Reference: 50 x 100mm
Pset_MemberCommon - IsExternal: yes
Name (Rectangular Mullion:50 x 100mm:...) | In | Span (mm)
1021933 | 0 Sokkel | 2000
1021934 | 0 Sokkel | 2000
1102779 | 0 Sokkel | 615
1102780 | 0 Sokkel | 614.524
1102783 | 0 Sokkel | 2000
1102784 | 0 Sokkel | 2000
1247552 | 0 Sokkel | 615
1247553 | 0 Sokkel | 614.524
1027764 | 1 Korrus | 330
1244880 | 1 Korrus | 330
1366173 | 1 Korrus | 875
1366808 | 1 Korrus | 350
1366809 | 1 Korrus | 305
1366902 | 1 Korrus | 875
1366903 | 1 Korrus | 305
1366944 | 1 Korrus | 875
1367122 | 1 Korrus | 875
1367123 | 1 Korrus | 350
1367335 | 1 Korrus | 330
1367336 | 1 Korrus | 420
1367337 | 1 Korrus | 370
1367338 | 1 Korrus | 370
1367340 | 1 Korrus | 400
1368535 | 1 Korrus | 420
1368536 | 1 Korrus | 330
1368537 | 1 Korrus | 305
1368538 | 1 Korrus | 305
1368540 | 1 Korrus | 400
1330475 | 1 Korrus | 2100
1330476 | 1 Korrus | 725
1330477 | 1 Korrus | 725
1330478 | 1 Korrus | 2100

# IfcOpeningElement: Opening (392)
Name | In
Basic Wall:Generic - 650mm:772438 | 1 Korrus | Pset_OpeningElementCommon - Reference: A-00_950x1450; sets with these values: 2; Pset_ProductRequirements - Category: Windows
Basic Wall:Generic - 650mm:772438 | 1 Korrus | Pset_OpeningElementCommon - Reference: A-00 - 19800x1900; sets with these values: 2; Pset_ProductRequirements - Category: Windows
Basic Wall:Generic - 280mm:773745 | 1 Korrus | Pset_OpeningElementCommon - Reference: SU-P-07 - 1000x2100; sets with these values: 2; Pset_ProductRequirements - Category: Doors
Basic Wall:Generic - 280mm:773745 | 1 Korrus | Pset_OpeningElementCommon - Reference: SU-AL-03 - 1350x2100; sets with these values: 2; Pset_ProductRequirements - Category: Doors
Basic Wall:Generic - 400mm:774572 | 1 Korrus | Pset_OpeningElementCommon - Reference: VU-02 - 1000x2100; sets with these values: 2; Pset_ProductRequirements - Category: Doors
Basic Wall:SS-02_ 150mm šahtide vahesein:775914 | 1 Korrus | Pset_OpeningElementCommon - Reference: SU-P-05 - 900x2100 TUBA; sets with these values: 2; Pset_ProductRequirements - Category: Doors
Basic Wall:SS-02_ 150mm šahtide vahesein:775914 | 1 Korrus | Pset_OpeningElementCommon - Reference: SU-M-07 - 800x2100 KORIS.; sets with these values: 2; Pset_ProductRequirements - Category: Doors
Basic Wall:SS-02_ 150mm šahtide vahesein:775972 | 1 Korrus | Pset_OpeningElementCommon - Reference: SU-P-05 - 900x2100 TUBA; sets with these values: 2; Pset_ProductRequirements - Category: Doors
Basic Wall:SS-02_ 150mm šahtide vahesein:776480 | 1 Korrus | Pset_OpeningElementCommon - Reference: SU-P-05 - 900x2100 TUBA; sets with these values: 2; Pset_ProductRequirements - Category: Doors
Basic Wall:SS-02_ 150mm šahtide vahesein:776562 | 1 Korrus | Pset_OpeningElementCommon - Reference: SU-P-08 - 700x2100 DUŠŠ; sets with these values: 2; Pset_ProductRequirements - Category: Doors
Basic Wall:SS-02_ 150mm šahtide vahesein:776599 | 1 Korrus | Pset_OpeningElementCommon - Reference: SU-P-08 - 700x2100 DUŠŠ; sets with these values: 2; Pset_ProductRequirements - Category: Doors
Basic Wall:SS-02_ 150mm šahtide vahesein:776599 | 1 Korrus | Pset_OpeningElementCommon - Reference: SU-P-05 - 900x2100 TUBA; sets with these values: 2; Pset_ProductRequirements - Category: Doors
Basic Wall:Generic - 770mm:777373:1 | 1 Korrus | Pset_OpeningElementCommon - Reference: Generic - 770mm; sets with these values: 2; Pset_ProductRequirements - Category: Walls; Pset_ElementShading - Roughness: 914.4 mm
Basic Wall:Generic - 770mm:777373 | 1 Korrus | Pset_OpeningElementCommon - Reference: A-00 - 19800x1900; sets with these values: 2; Pset_ProductRequirements - Category: Windows
Basic Wall:Generic - 770mm:777373 | 1 Korrus | Pset_OpeningElementCommon - Reference: A-00_950x1450; sets with these values: 2; Pset_ProductRequirements - Category: Windows
Basic Wall:Generic - 250mm:780019 | 2 Korrus | Pset_OpeningElementCommon - Reference: Generic - 250mm; sets with these values: 2; Pset_ProductRequirements - Category: Rectangular Straight Wall Opening; Pset_ElementShading - Roughness: 914.4 mm
Basic Wall:Generic - 470mm:780040 | 2 Korrus | Pset_OpeningElementCommon - Reference: A-00 - 19800x1900; sets with these values: 2; Pset_ProductRequirements - Category: Windows
2 x Basic Wall:Generic - 700mm:780742 | 3 Korrus | Pset_OpeningElementCommon - Reference: A-00_18000x600 mm; sets with these values: 2; Pset_ProductRequirements - Category: Windows
Basic Wall:Generic - 650mm:780748 | 3 Korrus | Pset_OpeningElementCommon - Reference: A-00 - 19800x1900; sets with these values: 2; Pset_ProductRequirements - Category: Windows
Basic Wall:Generic - 280mm:780751 | 3 Korrus | Pset_OpeningElementCommon - Reference: SU-AL-03 - 1350x2100; sets with these values: 2; Pset_ProductRequirements - Category: Doors
Basic Wall:Generic - 250mm:780752 | 3 Korrus | Pset_OpeningElementCommon - Reference: Generic - 250mm; sets with these values: 2; Pset_ProductRequirements - Category: Rectangular Straight Wall Opening; Pset_ElementShading - Roughness: 914.4 mm
Basic Wall:Generic - 400mm:780757 | 3 Korrus | Pset_OpeningElementCommon - Reference: A-03_1140x670; sets with these values: 2; Pset_ProductRequirements - Category: Windows
Basic Wall:Generic - 457mm:780774 | 3 Korrus | Pset_OpeningElementCommon - Reference: A-00 - 19800x1900; sets with these values: 2; Pset_ProductRequirements - Category: Windows
Basic Wall:Generic - 790mm:780788 | 3 Korrus | Pset_OpeningElementCommon - Reference: A-00 - 19800x1900; sets with these values: 2; Pset_ProductRequirements - Category: Windows
Basic Wall:Generic - 680mm:780801:1 | 4 Korrus | Pset_OpeningElementCommon - Reference: Generic - 680mm; sets with these values: 2; Pset_ProductRequirements - Category: Walls; Pset_ElementShading - Roughness: 914.4 mm
Basic Wall:Generic - 700mm:780802 | 4 Korrus | Pset_OpeningElementCommon - Reference: A-00_18000x600 mm; sets with these values: 2; Pset_ProductRequirements - Category: Windows
Basic Wall:Generic - 450mm:780809 | 4 Korrus | Pset_OpeningElementCommon - Reference: SU-P-09 - 1000x2090; sets with these values: 2; Pset_ProductRequirements - Category: Doors
Basic Wall:Generic - 350mm:780817 | 4 Korrus | Pset_OpeningElementCommon - Reference: A-03_1140x670; sets with these values: 2; Pset_ProductRequirements - Category: Windows
Basic Wall:Generic - 665mm:783109 | 0 Sokkel | Pset_OpeningElementCommon - Reference: A-00_950x1450; sets with these values: 2; Pset_ProductRequirements - Category: Windows
Basic Wall:Generic - 250mm:783113 | 0 Sokkel | Pset_OpeningElementCommon - Reference: SU-AL-04 - 1600x2100; sets with these values: 2; Pset_ProductRequirements - Category: Doors
Basic Wall:Generic - 630mm:783118 | 0 Sokkel | Pset_OpeningElementCommon - Reference: VU-01 - 1250x2100; sets with these values: 2; Pset_ProductRequirements - Category: Doors
Basic Wall:Generic - 400mm:783119 | 0 Sokkel | Pset_OpeningElementCommon - Reference: VU-02 - 1000x2100; sets with these values: 2; Pset_ProductRequirements - Category: Doors
Basic Wall:Generic - 280mm:783120 | 0 Sokkel | Pset_OpeningElementCommon - Reference: Generic - 280mm; sets with these values: 2; Pset_ProductRequirements - Category: Rectangular Straight Wall Opening; Pset_ElementShading - Roughness: 914.4 mm
Basic Wall:Generic - 770mm:783123 | 0 Sokkel | Pset_OpeningElementCommon - Reference: VU-02 - 1000x2100; sets with these values: 2; Pset_ProductRequirements - Category: Doors
Basic Wall:Generic - 665mm:786336 | 0 Sokkel | Pset_OpeningElementCommon - Reference: A-00 - 19800x1900; sets with these values: 2; Pset_ProductRequirements - Category: Windows
Basic Wall:SS-05_Kips, 66mm metallkarkass:812245 | 1 Korrus | Pset_OpeningElementCommon - Reference: SU-P-06 - 800x2100 DUŠŠ; sets with these values: 2; Pset_ProductRequirements - Category: Doors
Basic Wall:SS-05_Kips, 66mm metallkarkass:818687 | 1 Korrus | Pset_OpeningElementCommon - Reference: SU-M-07 - 800x2100 KORIS.; sets with these values: 2; Pset_ProductRequirements - Category: Doors
Basic Wall:SS-04_Kips, 50+50 mm metallkarkass 2:827800 | 1 Korrus | Pset_OpeningElementCommon - Reference: SU-P-05 - 900x2100 TUBA; sets with these values: 2; Pset_ProductRequirements - Category: Doors
SMA_D01, 1-poolne:SU-P-10 - 1000x2000:1102583:1 | 0 Sokkel
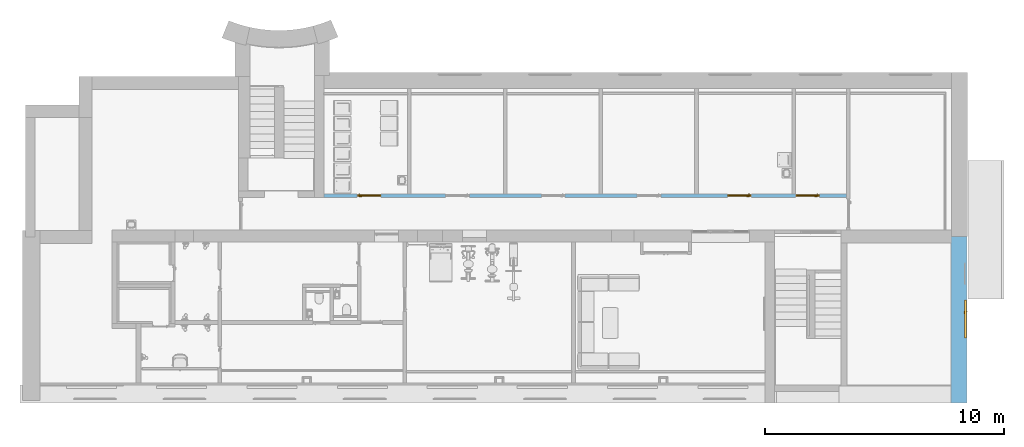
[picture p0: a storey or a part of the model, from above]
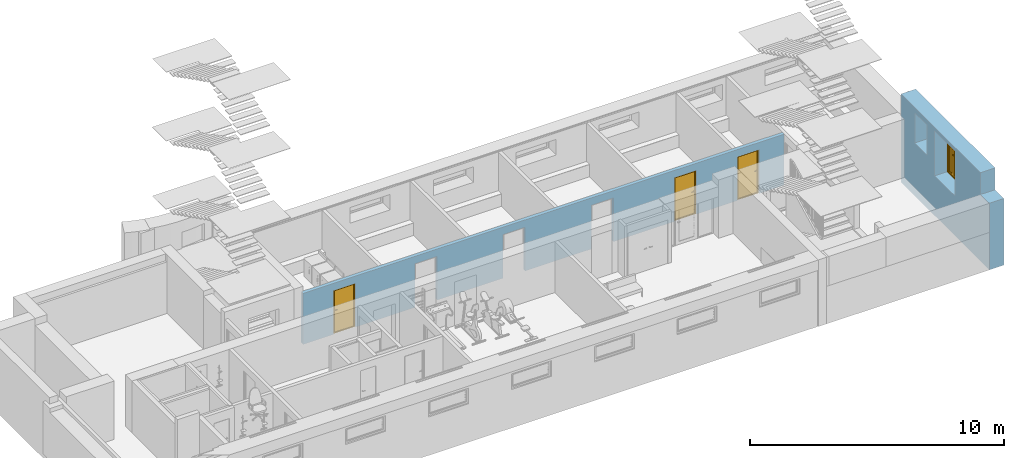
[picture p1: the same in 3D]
Properties of the parts of a building model (IFC2X3), part 3 of 4

# IfcOpeningElement: Opening (392)
Name | In
Basic Wall:SS-03_Kips, 66mm metallkarkass:843557 | 1 Korrus | Pset_OpeningElementCommon - Reference: SU-P-06 - 800x2100 DUŠŠ; sets with these values: 2; Pset_ProductRequirements - Category: Doors
SMA_W1, 1-jaotus1:A-00_18000x600 mm:1246395:1 | 2 Korrus
2 x Basic Wall:SS-04_Kips, 95mm metallkarkass:846701 | Sissepääs | Pset_OpeningElementCommon - Reference: Curtain Wall SKF-02; sets with these values: 2; Pset_ProductRequirements - Category: Walls
Basic Wall:SS-04_Kips, 95mm metallkarkass:806244 | Sissepääs | Pset_OpeningElementCommon - Reference: SS-04_Kips, 95mm metallkarkass; sets with these values: 2; Pset_ProductRequirements - Category: <Sketch>; Pset_ElementShading - Roughness: 914.4 mm
Basic Wall:SS-05_Kips, 66mm metallkarkass:847464 | 2 Korrus | Pset_OpeningElementCommon - Reference: SU-P-05 - 900x2100 TUBA; sets with these values: 2; Pset_ProductRequirements - Category: Doors
Basic Wall:SS-05_Kips, 66mm metallkarkass:847469 | 2 Korrus | Pset_OpeningElementCommon - Reference: SU-P-06 - 800x2100 DUŠŠ; sets with these values: 2; Pset_ProductRequirements - Category: Doors
Basic Wall:SS-05_Kips, 66mm metallkarkass:847476 | 2 Korrus | Pset_OpeningElementCommon - Reference: SU-P-06 - 800x2100 DUŠŠ; sets with these values: 2; Pset_ProductRequirements - Category: Doors
Basic Wall:SS-04_Kips, 50+50 mm metallkarkass 2:847484 | 2 Korrus | Pset_OpeningElementCommon - Reference: SU-P-04 - 1000x2100 EI-30; sets with these values: 2; Pset_ProductRequirements - Category: Doors
Basic Wall:SS-05_Kips, 66mm metallkarkass:847502 | 2 Korrus | Pset_OpeningElementCommon - Reference: SU-P-05 - 900x2100 TUBA; sets with these values: 2; Pset_ProductRequirements - Category: Doors
SMA_D01, 1-poolne:SU-P-05 - 900x2100 TUBA:1087275:1 | 1 Korrus
Basic Wall:SS-05_Kips, 66mm metallkarkass:847502 | 2 Korrus | Pset_OpeningElementCommon - Reference: SU-P-06 - 800x2100 DUŠŠ; sets with these values: 2; Pset_ProductRequirements - Category: Doors
Basic Wall:SS-04_Kips, 50+50 mm metallkarkass 2:847509 | 2 Korrus | Pset_OpeningElementCommon - Reference: SU-P-05 - 900x2100 TUBA; sets with these values: 2; Pset_ProductRequirements - Category: Doors
Basic Wall:SS-05_Kips, 66mm metallkarkass:847564 | 2 Korrus | Pset_OpeningElementCommon - Reference: SU-P-06 - 800x2100 DUŠŠ; sets with these values: 2; Pset_ProductRequirements - Category: Doors
Basic Wall:SS-02_ 150mm šahtide vahesein:847583 | 2 Korrus | Pset_ProductRequirements - Category: Doors; Pset_ConcreteElementGeneral - FireRating: -; Pset_DoorCommon - IsExternal: no; Reference: SU-M-07 - 800x2100 KORIS.; FireRating: -; AcousticRating: -; Pset_QuantityTakeOff - Reference: SU-M-07 - 800x2100 KORIS.
Basic Wall:SS-02_ 150mm šahtide vahesein:847584 | 2 Korrus | Pset_OpeningElementCommon - Reference: SU-P-05 - 900x2100 TUBA; sets with these values: 2; Pset_ProductRequirements - Category: Doors
Basic Wall:SS-02_ 150mm šahtide vahesein:847585 | 2 Korrus | Pset_OpeningElementCommon - Reference: SU-P-05 - 900x2100 TUBA; sets with these values: 2; Pset_ProductRequirements - Category: Doors
Basic Wall:SS-02_ 150mm šahtide vahesein:847593 | 2 Korrus | Pset_ProductRequirements - Category: Doors; Pset_ConcreteElementGeneral - FireRating: -; Pset_DoorCommon - IsExternal: no; Reference: SU-P-05 - 900x2100 TUBA; FireRating: -; AcousticRating: 35dB; Pset_QuantityTakeOff - Reference: SU-P-05 - 900x2100 TUBA
Basic Wall:SS-02_ 150mm šahtide vahesein:847595 | 2 Korrus | Pset_ProductRequirements - Category: Doors; Pset_ConcreteElementGeneral - FireRating: -; Pset_DoorCommon - IsExternal: no; Reference: SU-P-08 - 700x2100 DUŠŠ; FireRating: -; AcousticRating: 30dB; Pset_QuantityTakeOff - Reference: SU-P-08 - 700x2100 DUŠŠ
Basic Wall:SS-02_ 150mm šahtide vahesein:847596 | 2 Korrus | Pset_ProductRequirements - Category: Doors; Pset_ConcreteElementGeneral - FireRating: -; Pset_DoorCommon - IsExternal: no; Reference: SU-P-08 - 700x2100 DUŠŠ; FireRating: -; AcousticRating: 30dB; Pset_QuantityTakeOff - Reference: SU-P-08 - 700x2100 DUŠŠ
Basic Wall:SS-02_ 150mm šahtide vahesein:847596 | 2 Korrus | Pset_ProductRequirements - Category: Doors; Pset_ConcreteElementGeneral - FireRating: -; Pset_DoorCommon - IsExternal: no; Reference: SU-P-05 - 900x2100 TUBA; FireRating: -; AcousticRating: 35dB; Pset_QuantityTakeOff - Reference: SU-P-05 - 900x2100 TUBA
Basic Wall:SS-05_Kips, 66mm metallkarkass:848696 | 2 Korrus | Pset_OpeningElementCommon - Reference: SU-P-05 - 900x2100 TUBA; sets with these values: 2; Pset_ProductRequirements - Category: Doors
SMA_D01, 1-poolne:SU-P-05 - 900x2100 TUBA:1087235:1 | 1 Korrus
SMA_D01, 1-poolne:SU-P-05 - 900x2100 TUBA:1087236:1 | 1 Korrus
SMA_W1, 1-jaotus1:A-00_1860x750 mm:1081043:1 | 0 Sokkel
SMA_W1, 1-jaotus1:A-00_1860x750 mm:1081042:1 | 0 Sokkel
SMA_W1, 1-jaotus1:A-00_1860x750 mm:1081041:1 | 0 Sokkel
Basic Wall:SS-03_Fibo 510mm kinnilaotav ava:852897 | 2 Korrus | Pset_ProductRequirements - Category: Doors; Pset_ConcreteElementGeneral - FireRating: EI-30; Pset_DoorCommon - IsExternal: no; Reference: SU-P-04 - 1000x2100 EI-30; FireRating: EI-30; AcousticRating: 35dB; Pset_QuantityTakeOff - Reference: SU-P-04 - 1000x2100 EI-30
SMA_W1, 1-jaotus1:A-00_1860x750 mm:1081040:1 | 0 Sokkel
SMA_W1, 1-jaotus1:A-00_1860x750 mm:1081039:1 | 0 Sokkel
Basic Wall:SS-05_Kips, 66mm metallkarkass:862802 | 3 Korrus | Pset_OpeningElementCommon - Reference: SU-P-06 - 800x2100 DUŠŠ; sets with these values: 2; Pset_ProductRequirements - Category: Doors
Basic Wall:SS-05_Kips, 66mm metallkarkass:862809 | 3 Korrus | Pset_OpeningElementCommon - Reference: SU-P-06 - 800x2100 DUŠŠ; sets with these values: 2; Pset_ProductRequirements - Category: Doors
Basic Wall:SS-05_Kips, 66mm metallkarkass:862814 | 3 Korrus | Pset_OpeningElementCommon - Reference: SU-M-07 - 800x2100 KORIS.; sets with these values: 2; Pset_ProductRequirements - Category: Doors
SMA_W1, 1-jaotus1:A-00_1860x750 mm:1081038:1 | 0 Sokkel
Basic Wall:SS-04_Kips, 50+50 mm metallkarkass 2:862816 | 3 Korrus | Pset_OpeningElementCommon - Reference: SU-P-04 - 1000x2100 EI-30; sets with these values: 2; Pset_ProductRequirements - Category: Doors
Basic Wall:SS-05_Kips, 66mm metallkarkass:862831 | 3 Korrus | Pset_OpeningElementCommon - Reference: SU-P-05 - 900x2100 TUBA; sets with these values: 2; Pset_ProductRequirements - Category: Doors
Basic Wall:SS-05_Kips, 66mm metallkarkass:862831 | 3 Korrus | Pset_OpeningElementCommon - Reference: SU-P-06 - 800x2100 DUŠŠ; sets with these values: 2; Pset_ProductRequirements - Category: Doors
Basic Wall:SS-05_Kips, 66mm metallkarkass:862844 | 3 Korrus | Pset_OpeningElementCommon - Reference: SU-P-05 - 900x2100 TUBA; sets with these values: 2; Pset_ProductRequirements - Category: Doors
Basic Wall:SS-02_ 150mm šahtide vahesein:862874 | 3 Korrus | Pset_OpeningElementCommon - Reference: SU-M-07 - 800x2100 KORIS.; sets with these values: 2; Pset_ProductRequirements - Category: Doors
Basic Wall:SS-02_ 150mm šahtide vahesein:862875 | 3 Korrus | Pset_ProductRequirements - Category: Doors; Pset_ConcreteElementGeneral - FireRating: -; Pset_DoorCommon - IsExternal: no; Reference: SU-P-05 - 900x2100 TUBA; FireRating: -; AcousticRating: 35dB; Pset_QuantityTakeOff - Reference: SU-P-05 - 900x2100 TUBA
Basic Wall:SS-02_ 150mm šahtide vahesein:862876 | 3 Korrus | Pset_ProductRequirements - Category: Doors; Pset_ConcreteElementGeneral - FireRating: -; Pset_DoorCommon - IsExternal: no; Reference: SU-P-05 - 900x2100 TUBA; FireRating: -; AcousticRating: 35dB; Pset_QuantityTakeOff - Reference: SU-P-05 - 900x2100 TUBA
Basic Wall:SS-02_ 150mm šahtide vahesein:862884 | 3 Korrus | Pset_ProductRequirements - Category: Doors; Pset_ConcreteElementGeneral - FireRating: -; Pset_DoorCommon - IsExternal: no; Reference: SU-P-05 - 900x2100 TUBA; FireRating: -; AcousticRating: 35dB; Pset_QuantityTakeOff - Reference: SU-P-05 - 900x2100 TUBA
Basic Wall:SS-02_ 150mm šahtide vahesein:862886 | 3 Korrus | Pset_OpeningElementCommon - Reference: SU-P-08 - 700x2100 DUŠŠ; sets with these values: 2; Pset_ProductRequirements - Category: Doors
Basic Wall:SS-02_ 150mm šahtide vahesein:862887 | 3 Korrus | Pset_ProductRequirements - Category: Doors; Pset_ConcreteElementGeneral - FireRating: -; Pset_DoorCommon - IsExternal: no; Reference: SU-P-05 - 900x2100 TUBA; FireRating: -; AcousticRating: 35dB; Pset_QuantityTakeOff - Reference: SU-P-05 - 900x2100 TUBA
Basic Wall:SS-02_ 150mm šahtide vahesein:862887 | 3 Korrus | Pset_OpeningElementCommon - Reference: SU-P-08 - 700x2100 DUŠŠ; sets with these values: 2; Pset_ProductRequirements - Category: Doors
Basic Wall:SS-03_Kips, 66mm metallkarkass:863633 | 3 Korrus | Pset_OpeningElementCommon - Reference: SU-P-06 - 800x2100 DUŠŠ; sets with these values: 2; Pset_ProductRequirements - Category: Doors
SMA_D02, 2-poolne:SU-AL-04 - 1600x2100:1080265:1 | 1 Korrus
SMA_D02, 2-poolne:SU-M-05 - 1800x2100:1067058:1 | 0 Sokkel
Basic Wall:SS-03_Fibo 510mm kinnilaotav ava:864742 | 3 Korrus | Pset_ProductRequirements - Category: Doors; Pset_ConcreteElementGeneral - FireRating: EI-30; Pset_DoorCommon - IsExternal: no; Reference: SU-P-04 - 1000x2100 EI-30; FireRating: EI-30; AcousticRating: 35dB; Pset_QuantityTakeOff - Reference: SU-P-04 - 1000x2100 EI-30
SMA_D01, 1-poolne:SU-P-06 - 800x2100 DUŠŠ:1087133:1 | 1 Korrus
SMA_D01, 1-poolne:SU-P-05 - 900x2100 TUBA:1066460:1 | 1 Korrus
SMA_D01, 1-poolne:SU-P-05 - 900x2100 TUBA:1066458:1 | 1 Korrus
SMA_W2, 2-jaotus:A-00 - 19800x1900:1060019:1 | 4 Korrus
SMA_W2, 2-jaotus:A-00 - 19800x1900:1060018:1 | 4 Korrus
SMA_W1, 1-jaotus1:A-02_1650x1900 mm kinni EI-30:1047986:1 | 1 Korrus
SMA_W1, 1-jaotus1:A-00_1650x1900 mm:1047985:1 | 1 Korrus
SMA_W2, 2-jaotus:A-00 - 2100x1300:1047779:1 | 1 Korrus
Basic Wall:SS-05_Kips, 66mm metallkarkass:865916 | 4 Korrus | Pset_OpeningElementCommon - Reference: SU-P-06 - 800x2100 DUŠŠ; sets with these values: 2; Pset_ProductRequirements - Category: Doors
Basic Wall:SS-03_Kips, 66mm metallkarkass:865923 | 4 Korrus | Pset_OpeningElementCommon - Reference: SU-P-06 - 800x2100 DUŠŠ; sets with these values: 2; Pset_ProductRequirements - Category: Doors
Basic Wall:SS-04_Kips, 50+50 mm metallkarkass 2:865930 | 4 Korrus | Pset_OpeningElementCommon - Reference: SU-P-04 - 1000x2100 EI-30; sets with these values: 2; Pset_ProductRequirements - Category: Doors
Basic Wall:SS-05_Kips, 66mm metallkarkass:865945 | 4 Korrus | Pset_OpeningElementCommon - Reference: SU-P-06 - 800x2100 DUŠŠ; sets with these values: 2; Pset_ProductRequirements - Category: Doors
Basic Wall:SS-05_Kips, 66mm metallkarkass:865945 | 4 Korrus | Pset_OpeningElementCommon - Reference: SU-P-05 - 900x2100 TUBA; sets with these values: 2; Pset_ProductRequirements - Category: Doors
Basic Wall:SS-05_Kips, 66mm metallkarkass:865958 | 4 Korrus | Pset_OpeningElementCommon - Reference: SU-P-05 - 900x2100 TUBA; sets with these values: 2; Pset_ProductRequirements - Category: Doors
Basic Wall:SS-02_ 150mm šahtide vahesein:866135 | 4 Korrus | Pset_ProductRequirements - Category: Doors; Pset_ConcreteElementGeneral - FireRating: -; Pset_DoorCommon - IsExternal: no; Reference: SU-M-07 - 800x2100 KORIS.; FireRating: -; AcousticRating: -; Pset_QuantityTakeOff - Reference: SU-M-07 - 800x2100 KORIS.
SMA_W1, 1-jaotus1:A-00_18000x600 mm:1046503:1 | 1 Korrus
Basic Wall:SS-02_ 150mm šahtide vahesein:866136 | 4 Korrus | Pset_ProductRequirements - Category: Doors; Pset_ConcreteElementGeneral - FireRating: -; Pset_DoorCommon - IsExternal: no; Reference: SU-P-05 - 900x2100 TUBA; FireRating: -; AcousticRating: 35dB; Pset_QuantityTakeOff - Reference: SU-P-05 - 900x2100 TUBA
Basic Wall:SS-02_ 150mm šahtide vahesein:866145 | 4 Korrus | Pset_ProductRequirements - Category: Doors; Pset_ConcreteElementGeneral - FireRating: -; Pset_DoorCommon - IsExternal: no; Reference: SU-P-05 - 900x2100 TUBA; FireRating: -; AcousticRating: 35dB; Pset_QuantityTakeOff - Reference: SU-P-05 - 900x2100 TUBA
Basic Wall:SS-02_ 150mm šahtide vahesein:866147 | 4 Korrus | Pset_OpeningElementCommon - Reference: SU-P-08 - 700x2100 DUŠŠ; sets with these values: 2; Pset_ProductRequirements - Category: Doors
Basic Wall:SS-02_ 150mm šahtide vahesein:866148 | 4 Korrus | Pset_ProductRequirements - Category: Doors; Pset_ConcreteElementGeneral - FireRating: -; Pset_DoorCommon - IsExternal: no; Reference: SU-P-05 - 900x2100 TUBA; FireRating: -; AcousticRating: 35dB; Pset_QuantityTakeOff - Reference: SU-P-05 - 900x2100 TUBA
Basic Wall:SS-02_ 150mm šahtide vahesein:866148 | 4 Korrus | Pset_OpeningElementCommon - Reference: SU-P-08 - 700x2100 DUŠŠ; sets with these values: 2; Pset_ProductRequirements - Category: Doors
Basic Wall:SS-03_Kips, 66mm metallkarkass:866277 | 4 Korrus | Pset_OpeningElementCommon - Reference: SU-P-06 - 800x2100 DUŠŠ; sets with these values: 2; Pset_ProductRequirements - Category: Doors
SMA_W2, 2-jaotus:A-00 - 2100x1900:1046495:1 | 1 Korrus
SMA_W2, 2-jaotus:A-00 - 2100x1900:1046496:1 | 1 Korrus
SMA_W2, 2-jaotus:A-00 - 2100x1900:1046497:1 | 1 Korrus
Basic Wall:SS-03_Fibo 510mm kinnilaotav ava:866976 | 4 Korrus | Pset_ProductRequirements - Category: Doors; Pset_ConcreteElementGeneral - FireRating: EI-30; Pset_DoorCommon - IsExternal: no; Reference: SU-P-04 - 1000x2100 EI-30; FireRating: EI-30; AcousticRating: 35dB; Pset_QuantityTakeOff - Reference: SU-P-04 - 1000x2100 EI-30
Basic Wall:SS-00_Sauna sein:882537 | 0 Sokkel | Pset_OpeningElementCommon - Reference: SU-KL-01 - 700x2000 SAUN KLAAS; sets with these values: 2; Pset_ProductRequirements - Category: Doors
Basic Wall:SS-00_Sauna sein:883119 | 0 Sokkel | Pset_OpeningElementCommon - Reference: SU-KL-01 - 700x2000 SAUN KLAAS; sets with these values: 2; Pset_ProductRequirements - Category: Doors
Basic Wall:SS-05_Kips, 66mm metallkarkass:1108207 | Sissepääs | Pset_OpeningElementCommon - Reference: SS-05_Kips, 66mm metallkarkass; sets with these values: 2; Pset_ProductRequirements - Category: <Sketch>; Pset_ElementShading - Roughness: 914.4 mm
Basic Wall:Generic - 400mm:886707 | 0 Sokkel | Pset_OpeningElementCommon - Reference: SU-M-06 - 1000x1200 EI-30; sets with these values: 2; Pset_ProductRequirements - Category: Doors
Basic Wall:Generic - 120mm:888521 | 0 Sokkel | Pset_OpeningElementCommon - Reference: Curtain Wall SKF-04; sets with these values: 2; Pset_ProductRequirements - Category: Walls
Basic Wall:Generic - 120mm:888521 | 0 Sokkel | Pset_OpeningElementCommon - Reference: SU-P-10 - 1000x2000; sets with these values: 2; Pset_ProductRequirements - Category: Doors
Basic Wall:Generic - 350mm:1069594 | 0 Sokkel | Pset_OpeningElementCommon - Reference: Generic - 350mm; sets with these values: 2; Pset_ProductRequirements - Category: <Sketch>; Pset_ElementShading - Roughness: 914.4 mm
SMA_W2, 2-jaotus:A-00 - 2100x1900:1046498:1 | 1 Korrus
SMA_W2, 2-jaotus:A-00 - 2100x1900:1046499:1 | 1 Korrus
SMA_W2, 2-jaotus:A-00 - 2100x1900:1046500:1 | 1 Korrus
SMA_W2, 2-jaotus:A-00 - 2100x1900:1046501:1 | 1 Korrus
SMA_W2, 2-jaotus:A-00 - 2100x1900:1046502:1 | 1 Korrus
SMA_W1, 1-jaotus1:A-00_1860x750 mm:1046385:1 | 0 Sokkel
SMA_W1, 1-jaotus1:A-00_1860x750 mm:1046384:1 | 0 Sokkel
Basic Wall:Generic - 630mm:1034815 | 0 Sokkel | Pset_OpeningElementCommon - Reference: VU-02 - 1000x2100; sets with these values: 2; Pset_ProductRequirements - Category: Doors
Basic Wall:Generic - 470mm:1034883 | 0 Sokkel | Pset_OpeningElementCommon - Reference: VU-01 - 1250x2100; sets with these values: 2; Pset_ProductRequirements - Category: Doors
Basic Wall:SS-01_ 150mm soklikorruse seinad:1037457:1 | 0 Sokkel | Pset_OpeningElementCommon - Reference: SS-01_ 150mm soklikorruse seinad; sets with these values: 2; Pset_ProductRequirements - Category: Walls; Pset_ElementShading - Roughness: 914.4 mm
Basic Wall:SS-01_ 150mm soklikorruse seinad:1040851 | 0 Sokkel | Pset_OpeningElementCommon - Reference: SU-P-02 - 700x2100; sets with these values: 2; Pset_ProductRequirements - Category: Doors
SMA_W1, 1-jaotus1:A-00_1860x750 mm:1046383:1 | 0 Sokkel
2 x Basic Wall:Generic - 700mm:1045941 | 2 Korrus | Pset_OpeningElementCommon - Reference: A-00_18000x600 mm; sets with these values: 2; Pset_ProductRequirements - Category: Windows
Basic Wall:Generic - 700mm:1046494 | 1 Korrus | Pset_OpeningElementCommon - Reference: A-00_18000x600 mm; sets with these values: 2; Pset_ProductRequirements - Category: Windows
SMA_W1, 1-jaotus1:A-00_1860x750 mm:1046382:1 | 0 Sokkel
Basic Wall:Generic - 450mm:1047984 | 1 Korrus | Pset_OpeningElementCommon - Reference: VU-01 - 1250x2100; sets with these values: 2; Pset_ProductRequirements - Category: Doors
Basic Wall:Generic - 450mm:1047984 | 1 Korrus | Pset_ProductRequirements - Category: Windows; Pset_QuantityTakeOff - Reference: A-03_1140x670; Pset_DoorWindowGlazingType - SolarHeatGainTransmittance: 0; Pset_WindowCommon - IsExternal: no; ThermalTransmittance: 0 kg/K/s3; Reference: A-03_1140x670; FireRating: EI-30; AcousticRating: 30dB
Basic Wall:SS-02_ 150mm šahtide vahesein:1050691 | 1 Korrus | Pset_OpeningElementCommon - Reference: SU-M-07 - 800x2100 KORIS.; sets with these values: 2; Pset_ProductRequirements - Category: Doors
Basic Wall:Generic - 380mm:1058659 | 3 Korrus | Pset_OpeningElementCommon - Reference: A-00 - 19800x1900; sets with these values: 2; Pset_ProductRequirements - Category: Windows
Basic Wall:Generic - 400mm:1070423 | 1 Korrus | Pset_ProductRequirements - Category: Windows; Pset_QuantityTakeOff - Reference: A-03_1140x670; Pset_DoorWindowGlazingType - SolarHeatGainTransmittance: 0; Pset_WindowCommon - IsExternal: no; ThermalTransmittance: 0 kg/K/s3; Reference: A-03_1140x670; FireRating: EI-30; AcousticRating: 30dB
Basic Wall:Generic - 400mm:1073010:1 | 4 Korrus | Pset_OpeningElementCommon - Reference: Generic - 400mm; sets with these values: 2; Pset_ProductRequirements - Category: Walls; Pset_ElementShading - Roughness: 914.4 mm
Basic Wall:Generic - 770mm:1074240 | 3 Korrus | Pset_OpeningElementCommon - Reference: Kaare nišš; sets with these values: 2; Pset_ProductRequirements - Category: Generic Models
Basic Wall:Generic - 700mm:1074330 | 3 Korrus | Pset_OpeningElementCommon - Reference: Kaare nišš; sets with these values: 2; Pset_ProductRequirements - Category: Generic Models
Basic Wall:Generic - 700mm:1074550 | 0 Sokkel | Pset_OpeningElementCommon - Reference: VU-02 - 1000x2100; sets with these values: 2; Pset_ProductRequirements - Category: Doors
SMA_W1, 1-jaotus1:A-00_1860x750 mm:1046381:1 | 0 Sokkel
Basic Wall:Generic - 700mm:1074550 | 0 Sokkel | Pset_OpeningElementCommon - Reference: Kaare nišš; sets with these values: 2; Pset_ProductRequirements - Category: Generic Models
Basic Wall:Generic - 700mm:1075490 | 2 Korrus | Pset_OpeningElementCommon - Reference: Kaare nišš; sets with these values: 2; Pset_ProductRequirements - Category: Generic Models
Basic Wall:Generic - 770mm:1078048 | 1 Korrus | Pset_OpeningElementCommon - Reference: VU-02 - 1000x2100; sets with these values: 2; Pset_ProductRequirements - Category: Doors
SMA_W1, 1-jaotus1:A-00_1860x750 mm:1046380:1 | 0 Sokkel
Basic Wall:SS-05_Kips, 66mm metallkarkass:1087234 | 1 Korrus | Pset_ProductRequirements - Category: Doors; Pset_ConcreteElementGeneral - FireRating: -; Pset_DoorCommon - IsExternal: no; Reference: SU-P-06 - 800x2100 DUŠŠ; FireRating: -; AcousticRating: 30dB; Pset_QuantityTakeOff - Reference: SU-P-06 - 800x2100 DUŠŠ
Basic Wall:SS-05_Kips, 66mm metallkarkass:1087276 | 1 Korrus | Pset_ProductRequirements - Category: Doors; Pset_ConcreteElementGeneral - FireRating: -; Pset_DoorCommon - IsExternal: no; Reference: SU-P-06 - 800x2100 DUŠŠ; FireRating: -; AcousticRating: 30dB; Pset_QuantityTakeOff - Reference: SU-P-06 - 800x2100 DUŠŠ
2 x Basic Wall:Generic - 700mm:1096458 | 2 Korrus | Pset_OpeningElementCommon - Reference: A-00_18000x600 mm; sets with these values: 2; Pset_ProductRequirements - Category: Windows
SMA_W1, 1-jaotus1:A-00_1860x750 mm:1046379:1 | 0 Sokkel
2 x Basic Wall:Generic - 700mm:1096658 | 3 Korrus | Pset_OpeningElementCommon - Reference: A-00_18000x600 mm; sets with these values: 2; Pset_ProductRequirements - Category: Windows
Basic Wall:Generic - 700mm:1099487 | 1 Korrus | Pset_OpeningElementCommon - Reference: A-00_18000x600 mm; sets with these values: 2; Pset_ProductRequirements - Category: Windows
Basic Wall:Generic - 700mm:1101285 | 4 Korrus | Pset_OpeningElementCommon - Reference: A-00_18000x600 mm; sets with these values: 2; Pset_ProductRequirements - Category: Windows
Basic Wall:SS-03_Kips, 66mm metallkarkass:1102554 | 0 Sokkel | Pset_OpeningElementCommon - Reference: Curtain Wall SKF-04; sets with these values: 2; Pset_ProductRequirements - Category: Walls
SMA_W1, 1-jaotus1:A-00_1860x750 mm:1046378:1 | 0 Sokkel
SMA_W1, 1-jaotus1:A-00_18000x600 mm:1045943:1 | 2 Korrus
SMA_W1, 1-jaotus1:A-00_18000x600 mm:1045942:1 | 2 Korrus
SMA_D02, 2-poolne:SU-AL-02 - 1400x2100 EI-30:776660:1 | 1 Korrus
SMA_D02, 2-poolne:SU-AL-03 - 1350x2100:774996:1 | 1 Korrus
SMA_W2, 2-jaotus:A-00 - 2100x1900:777538:1 | 1 Korrus
SMA_W2, 2-jaotus:A-00 - 2100x1900:777559:1 | 1 Korrus
SMA_W2, 2-jaotus:A-00 - 2100x1900:777601:1 | 1 Korrus
SMA_W2, 2-jaotus:A-00 - 2100x1900:777643:1 | 1 Korrus
SMA_W2, 2-jaotus:A-00 - 2100x1900:777686:1 | 1 Korrus
SMA_W2, 2-jaotus:A-00 - 2100x1900:777728:1 | 1 Korrus
SMA_W2, 2-jaotus:A-01 - 2100x1900:777772:1 | 1 Korrus
SMA_D02, 2-poolne:VU-AL-03- 1600x2100:779409:1 | 0 Sokkel
SMA_W1, 1-jaotus1:A-00_1650x1900 mm:780050:1 | 2 Korrus
SMA_W1, 1-jaotus1:A-00_1650x1900 mm kinni:780051:1 | 2 Korrus
SMA_W2, 2-jaotus:A-00 - 2100x1300:783577:1 | 2 Korrus
SMA_D02, 2-poolne:SU-AL-03 - 1350x2100:780028:1 | 2 Korrus
SMA_D02, 2-poolne:SU-AL-03 - 1350x2100:780030:1 | 2 Korrus
SMA_W2, 2-jaotus:A-00 - 2100x1900:1068498:1 | 3 Korrus
SMA_W2, 2-jaotus:A-00 - 2100x1900:1068551:1 | 3 Korrus
SMA_W2, 2-jaotus:A-00 - 2100x1900:1068596:1 | 3 Korrus
SMA_W2, 2-jaotus:A-00 - 2100x1900:1068660:1 | 3 Korrus
SMA_W2, 2-jaotus:A-00 - 2100x1900:1068708:1 | 3 Korrus
SMA_W2, 2-jaotus:A-00 - 2100x1900:1068760:1 | 3 Korrus
SMA_W2, 2-jaotus:A-00 - 2100x1900:1068810:1 | 3 Korrus
SMA_W2, 2-jaotus:A-00 - 2100x1900:1068860:1 | 3 Korrus
SMA_W1, 1-jaotus1:A-00_1650x1900 mm kinni:780784:1 | 3 Korrus
SMA_W1, 1-jaotus1:A-00_1650x1900 mm:1068017:1 | 3 Korrus
SMA_D02, 2-poolne:SU-AL-03 - 1350x2100:780763:1 | 3 Korrus
SMA_W2, 2-jaotus:A-00 - 2100x1300:780782:1 | 3 Korrus
SMA_D02, 2-poolne:SU-AL-03 - 1350x2100:780761:1 | 3 Korrus
SMA_W1, 1-jaotus1:A-00_18000x600 mm:780772:1 | 3 Korrus
SMA_W2, 2-jaotus:A-00 - 2100x1900:780775:1 | 3 Korrus
SMA_W2, 2-jaotus:A-00 - 2100x1900:780776:1 | 3 Korrus
SMA_W2, 2-jaotus:A-00 - 2100x1900:780777:1 | 3 Korrus
SMA_W2, 2-jaotus:A-00 - 2100x1900:780778:1 | 3 Korrus
SMA_W2, 2-jaotus:A-00 - 2100x1900:780779:1 | 3 Korrus
SMA_W2, 2-jaotus:A-00 - 2100x1900:780780:1 | 3 Korrus
SMA_W2, 2-jaotus:A-00 - 2100x1900:780781:1 | 3 Korrus
SMA_W1, 1-jaotus1:A-00_18000x600 mm:780787:1 | 3 Korrus
SMA_W2, 2-jaotus:A-00 - 2100x1900:1068500:1 | 4 Korrus
SMA_W2, 2-jaotus:A-00 - 2100x1900:1068553:1 | 4 Korrus
SMA_W2, 2-jaotus:A-00 - 2100x1900:1068598:1 | 4 Korrus
SMA_W2, 2-jaotus:A-00 - 2100x1900:1068662:1 | 4 Korrus
SMA_W2, 2-jaotus:A-00 - 2100x1900:1068710:1 | 4 Korrus
SMA_W2, 2-jaotus:A-00 - 2100x1900:1068762:1 | 4 Korrus
SMA_W2, 2-jaotus:A-00 - 2100x1900:1068812:1 | 4 Korrus
SMA_W2, 2-jaotus:A-00 - 2100x1900:1068862:1 | 4 Korrus
SMA_W2, 2-jaotus:A-00 - 2100x1900:908459:1 | 4 Korrus
SMA_W2, 2-jaotus:A-00 - 2100x1900:908460:1 | 4 Korrus
SMA_W2, 2-jaotus:A-00 - 2100x1900:908461:1 | 4 Korrus
SMA_W2, 2-jaotus:A-00 - 2100x1900:908462:1 | 4 Korrus
SMA_W2, 2-jaotus:A-00 - 2100x1900:908463:1 | 4 Korrus
SMA_W2, 2-jaotus:A-00 - 2100x1900:908464:1 | 4 Korrus
SMA_W2, 2-jaotus:A-00 - 2100x1900:908499:1 | 4 Korrus
SMA_W1, 1-jaotus1:A-00_1650x1900 mm kinni:780844:1 | 4 Korrus
SMA_W1, 1-jaotus1:A-00_1650x1900 mm:1068019:1 | 4 Korrus
SMA_D02, 2-poolne:SU-AL-03 - 1350x2100:780823:1 | 4 Korrus
SMA_W2, 2-jaotus:A-00 - 2100x1300:783579:1 | 4 Korrus
SMA_D02, 2-poolne:SU-AL-03 - 1350x2100:780821:1 | 4 Korrus
SMA_W1, 1-jaotus1:A-00_18000x600 mm:780832:1 | 4 Korrus
SMA_W2, 2-jaotus:A-00 - 19800x1900:782989:1 | 3 Korrus
SMA_W2, 2-jaotus:A-00 - 19800x1900:782990:1 | 3 Korrus
SMA_D02, 2-poolne:SU-AL-01 - 1500x2100:783124:1 | 0 Sokkel
SMA_W1, 1-jaotus1:A-00_950x1450:878381:1 | 0 Sokkel
SMA_D01, 1-poolne:SU-P-09 - 1000x2050:788391:1 | 1 Korrus
SMA_D01, 1-poolne:SU-P-04 - 1000x2050 EI-30:788744:1 | 1 Korrus
SMA_D01, 1-poolne:SU-P-04 - 1000x2060 EI-30:788842:1 | 1 Korrus
SMA_D01, 1-poolne:SU-P-07 - 1000x2100:788999:1 | 1 Korrus
SMA_D01, 1-poolne:SU-P-05 - 900x2100 TUBA:809404:1 | 1 Korrus
SMA_D01, 1-poolne:SU-P-05 - 900x2100 TUBA:809587:1 | 1 Korrus
SMA_D01, 1-poolne:SU-P-05 - 900x2100 TUBA:814190:1 | 1 Korrus
SMA_D01, 1-poolne:SU-P-06 - 800x2100 DUŠŠ:817009:1 | 1 Korrus
SMA_D01, 1-poolne:SU-P-05 - 900x2100 TUBA:813377:1 | 1 Korrus
SMA_D01, 1-poolne:SU-P-05 - 900x2100 TUBA:811581:1 | 1 Korrus
SMA_D01, 1-poolne:SU-P-05 - 900x2100 TUBA:811532:1 | 1 Korrus
SMA_D01, 1-poolne:SU-P-05 - 900x2100 TUBA:825858:1 | 1 Korrus
SMA_D01, 1-poolne:SU-P-04 - 1000x2100 EI-30:830798:1 | 1 Korrus
SMA_D01, 1-poolne:SU-P-04 - 1000x2100 EI-30:828314:1 | 1 Korrus
SMA_D01, 1-poolne:SU-M-07 - 800x2100 KORIS.:845257:1 | 1 Korrus
SMA_D01, 1-poolne:SU-P-04 - 1000x2100 EI-30:831116:1 | 1 Korrus
SMA_D01, 1-poolne:SU-P-05 - 900x2100 TUBA:830719:1 | 1 Korrus
SMA_D01, 1-poolne:SU-P-05 - 900x2100 TUBA:828277:1 | 1 Korrus
SMA_D01, 1-poolne:SU-P-08 - 700x2100 DUŠŠ:839488:1 | 1 Korrus
SMA_D01, 1-poolne:SU-P-06 - 800x2100 DUŠŠ:830090:1 | 1 Korrus
SMA_D01, 1-poolne:SU-P-06 - 800x2100 DUŠŠ:830153:1 | 1 Korrus
SMA_D01, 1-poolne:SU-P-05 - 900x2100 TUBA:830617:1 | 1 Korrus
SMA_D01, 1-poolne:SU-P-05 - 900x2100 TUBA:838925:1 | 1 Korrus
SMA_D01, 1-poolne:SU-P-06 - 800x2100 DUŠŠ:843613:1 | 1 Korrus
SMA_D01, 1-poolne:SU-P-04 - 1000x2100 EI-30:845374:1 | 1 Korrus
SMA_D01, 1-poolne:SU-P-03 - 1000x2100:847005:1 | Sissepääs
SMA_D02, 2-poolne:SU-AL-04 - 1600x2100:846940:1 | Sissepääs
SMA_D01, 1-poolne:VU-02 - 1000x2100:847238:1 | 1 Korrus
SMA_D01, 1-poolne:VU-01 - 1250x2100:847334:1 | 1 Korrus
SMA_D01, 1-poolne:SU-P-05 - 900x2100 TUBA:847472:1 | 2 Korrus
SMA_D01, 1-poolne:SU-P-05 - 900x2100 TUBA:847461:1 | 2 Korrus
SMA_D01, 1-poolne:SU-P-05 - 900x2100 TUBA:847460:1 | 2 Korrus
SMA_D01, 1-poolne:SU-P-05 - 900x2100 TUBA:847470:1 | 2 Korrus
SMA_D01, 1-poolne:SU-P-05 - 900x2100 TUBA:847468:1 | 2 Korrus
SMA_D01, 1-poolne:SU-P-05 - 900x2100 TUBA:847467:1 | 2 Korrus
SMA_D01, 1-poolne:SU-P-05 - 900x2100 TUBA:847483:1 | 2 Korrus
SMA_D01, 1-poolne:SU-P-04 - 1000x2100 EI-30:847499:1 | 2 Korrus
SMA_D01, 1-poolne:SU-P-04 - 1000x2100 EI-30:847492:1 | 2 Korrus
SMA_D01, 1-poolne:SU-P-05 - 900x2100 TUBA:847494:1 | 2 Korrus
SMA_D01, 1-poolne:SU-P-05 - 900x2100 TUBA:847497:1 | 2 Korrus
SMA_D01, 1-poolne:SU-P-05 - 900x2100 TUBA:860016:1 | 2 Korrus
SMA_D01, 1-poolne:SU-P-05 - 900x2100 TUBA:860031:1 | 2 Korrus
SMA_D01, 1-poolne:SU-P-06 - 800x2100 DUŠŠ:859936:1 | 2 Korrus
SMA_D01, 1-poolne:SU-M-07 - 800x2100 KORIS.:847510:1 | 2 Korrus
SMA_D01, 1-poolne:SU-P-04 - 1000x2100 EI-30:847500:1 | 2 Korrus
SMA_D01, 1-poolne:SU-P-05 - 900x2100 TUBA:847498:1 | 2 Korrus
SMA_D01, 1-poolne:SU-P-05 - 900x2100 TUBA:847495:1 | 2 Korrus
SMA_D01, 1-poolne:SU-P-05 - 900x2100 TUBA:852751:1 | 2 Korrus
SMA_D01, 1-poolne:SU-P-05 - 900x2100 TUBA:847504:1 | 2 Korrus
SMA_D01, 1-poolne:SU-P-04 - 1000x2100 EI-30:847511:1 | 2 Korrus
SMA_D01, 1-poolne:SU-P-06 - 800x2100 DUŠŠ:847550:1 | 2 Korrus
SMA_D01, 1-poolne:SU-P-08 - 700x2100 DUŠŠ:847561:1 | 2 Korrus
SMA_D01, 1-poolne:SU-P-06 - 800x2100 DUŠŠ:847556:1 | 2 Korrus
SMA_D01, 1-poolne:SU-P-06 - 800x2100 DUŠŠ:847557:1 | 2 Korrus
SMA_D01, 1-poolne:SU-P-06 - 800x2100 DUŠŠ:847565:1 | 2 Korrus
SMA_D01, 1-poolne:SU-P-04 - 1000x2070 EI-30:847724:1 | 2 Korrus
SMA_D01, 1-poolne:SU-P-09 - 1000x2070:847815:1 | 2 Korrus
SMA_D01, 1-poolne:SU-P-04 - 1000x2090 EI-30:849220:1 | 2 Korrus
SMA_D01, 1-poolne:SU-P-05 - 900x2100 TUBA:852576:1 | 2 Korrus
SMA_D01, 1-poolne:SU-P-05 - 900x2100 TUBA:855845:1 | 2 Korrus
SMA_D01, 1-poolne:SU-P-05 - 900x2100 TUBA:862805:1 | 3 Korrus
SMA_D01, 1-poolne:SU-P-05 - 900x2100 TUBA:862795:1 | 3 Korrus
SMA_D01, 1-poolne:SU-P-05 - 900x2100 TUBA:862794:1 | 3 Korrus
SMA_D01, 1-poolne:SU-P-05 - 900x2100 TUBA:862803:1 | 3 Korrus
SMA_D01, 1-poolne:SU-P-05 - 900x2100 TUBA:862801:1 | 3 Korrus
SMA_D01, 1-poolne:SU-P-05 - 900x2100 TUBA:862800:1 | 3 Korrus
SMA_D01, 1-poolne:SU-P-05 - 900x2100 TUBA:862815:1 | 3 Korrus
SMA_D01, 1-poolne:SU-P-04 - 1000x2100 EI-30:862829:1 | 3 Korrus
SMA_D01, 1-poolne:SU-P-04 - 1000x2100 EI-30:862823:1 | 3 Korrus
SMA_D01, 1-poolne:SU-P-05 - 900x2100 TUBA:862827:1 | 3 Korrus
SMA_D01, 1-poolne:SU-P-05 - 900x2100 TUBA:862825:1 | 3 Korrus
SMA_D01, 1-poolne:SU-P-05 - 900x2100 TUBA:862851:1 | 3 Korrus
SMA_D01, 1-poolne:SU-P-05 - 900x2100 TUBA:862852:1 | 3 Korrus
SMA_D01, 1-poolne:SU-P-06 - 800x2100 DUŠŠ:862850:1 | 3 Korrus
SMA_D01, 1-poolne:SU-M-07 - 800x2100 KORIS.:862837:1 | 3 Korrus
SMA_D01, 1-poolne:SU-P-04 - 1000x2100 EI-30:862830:1 | 3 Korrus
SMA_D01, 1-poolne:SU-P-05 - 900x2100 TUBA:862828:1 | 3 Korrus
SMA_D01, 1-poolne:SU-P-05 - 900x2100 TUBA:862826:1 | 3 Korrus
SMA_D01, 1-poolne:SU-P-05 - 900x2100 TUBA:862847:1 | 3 Korrus
SMA_D01, 1-poolne:SU-P-05 - 900x2100 TUBA:862833:1 | 3 Korrus
SMA_D01, 1-poolne:SU-P-04 - 1000x2100 EI-30:862838:1 | 3 Korrus
SMA_D01, 1-poolne:SU-P-05 - 900x2100 TUBA:862846:1 | 3 Korrus
SMA_D01, 1-poolne:SU-P-05 - 900x2100 TUBA:862849:1 | 3 Korrus
SMA_D01, 1-poolne:SU-P-06 - 800x2100 DUŠŠ:863623:1 | 3 Korrus
SMA_D01, 1-poolne:SU-P-06 - 800x2100 DUŠŠ:863627:1 | 3 Korrus
SMA_D01, 1-poolne:SU-P-06 - 800x2100 DUŠŠ:863628:1 | 3 Korrus
SMA_D01, 1-poolne:SU-P-06 - 800x2100 DUŠŠ:863634:1 | 3 Korrus
SMA_D01, 1-poolne:SU-P-09 - 1000x2020:863814:1 | 3 Korrus
SMA_D01, 1-poolne:SU-P-04 - 1000x2020 EI-30:864017:1 | 3 Korrus
SMA_D01, 1-poolne:SU-P-04 - 1000x2040 EI-30:864098:1 | 3 Korrus
SMA_D01, 1-poolne:SU-P-05 - 900x2100 TUBA:865919:1 | 4 Korrus
SMA_D01, 1-poolne:SU-P-05 - 900x2100 TUBA:865909:1 | 4 Korrus
SMA_D01, 1-poolne:SU-P-05 - 900x2100 TUBA:865908:1 | 4 Korrus
SMA_D01, 1-poolne:SU-P-05 - 900x2100 TUBA:865917:1 | 4 Korrus
SMA_D01, 1-poolne:SU-P-05 - 900x2100 TUBA:865915:1 | 4 Korrus
SMA_D01, 1-poolne:SU-P-05 - 900x2100 TUBA:865914:1 | 4 Korrus
SMA_D01, 1-poolne:SU-P-05 - 900x2100 TUBA:865929:1 | 4 Korrus
SMA_D01, 1-poolne:SU-P-04 - 1000x2100 EI-30:865943:1 | 4 Korrus
SMA_D01, 1-poolne:SU-P-04 - 1000x2100 EI-30:865937:1 | 4 Korrus
SMA_D01, 1-poolne:SU-P-05 - 900x2100 TUBA:865939:1 | 4 Korrus
SMA_D01, 1-poolne:SU-P-05 - 900x2100 TUBA:865941:1 | 4 Korrus
SMA_D01, 1-poolne:SU-P-05 - 900x2100 TUBA:865965:1 | 4 Korrus
SMA_D01, 1-poolne:SU-P-05 - 900x2100 TUBA:865966:1 | 4 Korrus
SMA_D01, 1-poolne:SU-P-06 - 800x2100 DUŠŠ:865964:1 | 4 Korrus
SMA_D01, 1-poolne:SU-M-07 - 800x2100 KORIS.:865951:1 | 4 Korrus
SMA_D01, 1-poolne:SU-P-04 - 1000x2100 EI-30:865944:1 | 4 Korrus
SMA_D01, 1-poolne:SU-P-05 - 900x2100 TUBA:865942:1 | 4 Korrus
SMA_D01, 1-poolne:SU-P-05 - 900x2100 TUBA:865940:1 | 4 Korrus
SMA_D01, 1-poolne:SU-P-05 - 900x2100 TUBA:865961:1 | 4 Korrus
SMA_D01, 1-poolne:SU-P-05 - 900x2100 TUBA:865947:1 | 4 Korrus
SMA_D01, 1-poolne:SU-P-04 - 1000x2100 EI-30:865952:1 | 4 Korrus
SMA_D01, 1-poolne:SU-P-05 - 900x2100 TUBA:865960:1 | 4 Korrus
SMA_D01, 1-poolne:SU-P-05 - 900x2100 TUBA:865963:1 | 4 Korrus
SMA_D01, 1-poolne:SU-P-06 - 800x2100 DUŠŠ:866267:1 | 4 Korrus
SMA_D01, 1-poolne:SU-P-06 - 800x2100 DUŠŠ:866271:1 | 4 Korrus
SMA_D01, 1-poolne:SU-P-06 - 800x2100 DUŠŠ:866272:1 | 4 Korrus
SMA_D01, 1-poolne:SU-P-06 - 800x2100 DUŠŠ:866278:1 | 4 Korrus
SMA_D01, 1-poolne:SU-P-08 - 700x2100 DUŠŠ:866580:1 | 3 Korrus
SMA_D01, 1-poolne:SU-P-08 - 700x2100 DUŠŠ:866586:1 | 4 Korrus
SMA_D01, 1-poolne:SU-P-04 - 1000x2070 EI-30:866954:1 | 4 Korrus
SMA_D01, 1-poolne:SU-P-09 - 1000x2090:866955:1 | 4 Korrus
SMA_D01, 1-poolne:SU-P-04 - 1000x2080 EI-30:867932:1 | 4 Korrus
SMA_D01, 1-poolne:SU-KL-02 - 900x2100:887654:1 | 0 Sokkel
SMA_D01, 1-poolne:SU-KL-02 - 900x2100:887573:1 | 0 Sokkel
sma_D01:SU-KL-01 - 700x2000 SAUN KLAAS:885303:1 | 0 Sokkel
SMA_D01, 1-poolne:SU-M-01 - 1200x2100 EI-30:887443:1 | 0 Sokkel
SMA_D01, 1-poolne:SU-M-02 - 1000x2100 EI-30:887050:1 | 0 Sokkel
SMA_D01, 1-poolne:SU-M-04 - 1000x2100 EI-60:1081425:1 | 0 Sokkel
SMA_D01, 1-poolne:SU-M-04 - 1000x2100 EI-60:1081426:1 | 0 Sokkel
SMA_D01, 1-poolne:SU-M-04 - 1000x2100 EI-60:1081427:1 | 0 Sokkel
SMA_D01, 1-poolne:SU-M-03 - 1000x2100:887324:1 | 0 Sokkel
SMA_D01, 1-poolne:SU-M-02 - 1000x2100 EI-30:887383:1 | 0 Sokkel
SMA_D01, 1-poolne:SU-M-01 - 1200x2100 EI-30:898495:1 | 0 Sokkel
SMA_D01, 1-poolne:SU-M-03 - 1000x2000:882178:1 | 0 Sokkel
SMA_D01, 1-poolne:SU-P-01 - 900x2100:885756:1 | 0 Sokkel
SMA_D01, 1-poolne:SU-M-02 - 1000x2100 EI-30:1242184:1 | Sissepääs
SMA_D01, 1-poolne:SU-M-06 - 1000x1200 EI-30:1145495:1 | 0 Sokkel
SMA_D01, 1-poolne:SU-M-06 - 1000x1200 EI-30:1241829:1 | 0 Sokkel
SMA_W1, 1-jaotus1:A-03_1140x670:903815:1 | 1 Korrus
SMA_W1, 1-jaotus1:A-03_1140x670:904301:1 | 2 Korrus
SMA_W1, 1-jaotus1:A-03_1140x670:904315:1 | 3 Korrus
SMA_W2, 2-jaotus:A-00 - 2100x1900:908363:1 | 2 Korrus
SMA_W2, 2-jaotus:A-00 - 2100x1900:908364:1 | 2 Korrus
SMA_W2, 2-jaotus:A-00 - 2100x1900:908365:1 | 2 Korrus
SMA_W2, 2-jaotus:A-00 - 2100x1900:908366:1 | 2 Korrus
SMA_W2, 2-jaotus:A-00 - 2100x1900:908367:1 | 2 Korrus
SMA_W2, 2-jaotus:A-00 - 2100x1900:908368:1 | 2 Korrus
SMA_W2, 2-jaotus:A-00 - 2100x1900:908394:1 | 2 Korrus
SMA_D01, 1-poolne:SU-P-02 - 700x2100:1040854:1 | 0 Sokkel
sma_D01:SU-KL-01 - 700x2000 SAUN KLAAS:1037578:1 | 0 Sokkel
SMA_D01, 1-poolne:SU-P-01 - 900x2100:1040855:1 | 0 Sokkel
SMA_D01, 1-poolne:SU-P-02 - 700x2100:1040864:1 | 0 Sokkel
SMA_D01, 1-poolne:SU-P-03 - 1000x2100:1041072:1 | 0 Sokkel
SMA_W2, 2-jaotus:A-00 - 19800x1900:1044149:1 | 1 Korrus
SMA_W2, 2-jaotus:A-00 - 19800x1900:1044148:1 | 1 Korrus
SMA_W2, 2-jaotus:A-00 - 19800x1900:1044336:1 | 2 Korrus
SMA_W2, 2-jaotus:A-00 - 19800x1900:1044337:1 | 2 Korrus
SMA_W2, 2-jaotus:A-00 - 2100x1900:1045944:1 | 2 Korrus
SMA_W2, 2-jaotus:A-00 - 2100x1900:1045945:1 | 2 Korrus
SMA_W2, 2-jaotus:A-00 - 2100x1900:1045946:1 | 2 Korrus
SMA_W2, 2-jaotus:A-00 - 2100x1900:1045947:1 | 2 Korrus
SMA_W2, 2-jaotus:A-00 - 2100x1900:1045948:1 | 2 Korrus
SMA_W2, 2-jaotus:A-00 - 2100x1900:1045949:1 | 2 Korrus
SMA_W2, 2-jaotus:A-00 - 2100x1900:1045950:1 | 2 Korrus
SMA_W2, 2-jaotus:A-00 - 2100x1900:1045951:1 | 2 Korrus

# IfcOpeningElement: Recess (21)
Name (Basic Wall:...) | In | Pset_OpeningElementCommon, Reference | sets with these values | Category
Generic - 450mm:780014 | 2 Korrus | niššid | 2 | Generic Models
Generic - 700mm:780742 | 3 Korrus | radikate nišš | 2 | Generic Models
Generic - 450mm:780747 | 3 Korrus | niššid | 2 | Generic Models
Generic - 700mm:780802 | 4 Korrus | radikate nišš | 2 | Generic Models
Generic - 665mm:780804 | 4 Korrus | niššid | 2 | Generic Models
Generic - 470mm:780807 | 4 Korrus | niššid | 2 | Generic Models
Generic - 700mm:1045941 | 2 Korrus | radikate nišš | 2 | Generic Models
Generic - 700mm:1046494 | 1 Korrus | radikate nišš | 2 | Generic Models
Generic - 450mm:1047984 | 1 Korrus | niššid | 2 | Generic Models
Generic - 770mm:1065658 | 2 Korrus |  |  | Windows | Pset_DoorWindowGlazingType - SolarHeatGainTransmittance: 0; Pset_QuantityTakeOff - Reference: A-03_1140x670; Pset_WindowCommon - IsExternal: no; ThermalTransmittance: 0 kg/K/s3; Reference: A-03_1140x670; FireRating: EI-30; AcousticRating: 30dB
Generic - 770mm:1065658 | 2 Korrus | A-03_1140x670 | 2 | Windows
Generic - 770mm:1073577 | 4 Korrus | A-03_1140x670 | 2 | Windows
Generic - 700mm:1073612 | 4 Korrus | A-03_1140x670 | 2 | Windows
Generic - 770mm:1074240 | 3 Korrus | A-03_1140x670 | 2 | Windows
Generic - 770mm:1075477 | 2 Korrus |  |  | Windows | Pset_DoorWindowGlazingType - SolarHeatGainTransmittance: 0; Pset_QuantityTakeOff - Reference: A-03_1140x670; Pset_WindowCommon - IsExternal: no; ThermalTransmittance: 0 kg/K/s3; Reference: A-03_1140x670; FireRating: EI-30; AcousticRating: 30dB
Generic - 770mm:1075477 | 2 Korrus | A-03_1140x670 | 2 | Windows
Generic - 700mm:1075490 | 2 Korrus |  |  | Windows | Pset_DoorWindowGlazingType - SolarHeatGainTransmittance: 0; Pset_QuantityTakeOff - Reference: A-03_1140x670; Pset_WindowCommon - IsExternal: no; ThermalTransmittance: 0 kg/K/s3; Reference: A-03_1140x670; FireRating: EI-30; AcousticRating: 30dB
Generic - 700mm:1075490 | 2 Korrus | A-03_1140x670 | 2 | Windows
Generic - 770mm:1078048 | 1 Korrus |  |  | Windows | Pset_DoorWindowGlazingType - SolarHeatGainTransmittance: 0; Pset_QuantityTakeOff - Reference: A-03_1140x670; Pset_WindowCommon - IsExternal: no; ThermalTransmittance: 0 kg/K/s3; Reference: A-03_1140x670; FireRating: EI-30; AcousticRating: 30dB
Generic - 470mm:1096638 | 3 Korrus | radikate nišš | 2 | Generic Models
Generic - 700mm:1096658 | 3 Korrus | radikate nišš | 2 | Generic Models

# IfcPlate: System Panel:Glazed (7)
Type - PredefinedType: CURTAIN_PANEL
Type - Pset_PlateCommon - IsExternal: no; Reference: Glazed; ThermalTransmittance: 6.7069 kg/K/s3
Type - Pset_ProductRequirements - Category: Curtain Panels
Type - Pset_QuantityTakeOff - Reference: Glazed
Pset_PlateCommon - IsExternal: yes
Name (System Panel:Glazed:...) | In
1021931 | 0 Sokkel
1027752 | 1 Korrus
1366897 | 1 Korrus
1367320 | 1 Korrus
1368520 | 1 Korrus
1366803 | 1 Korrus
1330474 | 1 Korrus

# IfcRailing: Railing:1000mm_sisearh railing offsetiga (13)
Material: Metal - Stainless Steel,Polished
Pset_ProductRequirements - Category: Railings
Pset_QuantityTakeOff - Reference: 1000mm_sisearh railing offsetiga
Pset_RailingCommon - IsExternal: no; Reference: 1000mm_sisearh railing offsetiga; Height: 1000 mm
Name (Railing:1000mm_sisearh railing offsetiga:...) | In
914726 | 2 Korrus
914742 | 3 Korrus
915085 | 0 Sokkel
915246 | 2 Korrus
916954 | 1 Korrus
916980 | 1 Korrus
1045991 | 3 Korrus
1055765 | 2 Korrus
1055931 | 3 Korrus
1067807 | 1 Korrus
1077479 | 1 Korrus
1077764 | 2 Korrus
1077836 | 3 Korrus

# IfcRamp: Ramp:Ramp 1 (3)
In: 0 Sokkel
Pset_ProductRequirements - Category: Ramps
Pset_QuantityTakeOff - Reference: Ramp 1
Pset_RampCommon - IsExternal: no; Reference: Ramp 1
Name (Ramp:Ramp 1:...)
1136626
1136688
1136816

# IfcRampFlight: Ramp:Ramp 1 (3)
In: 0 Sokkel
Pset_ProductRequirements - Category: Ramps
Pset_QuantityTakeOff - Reference: Ramp 1; sets with these values: 2
Name (Ramp:Ramp 1:...)
1136626:1
1136688:1
1136816:1

# IfcRoof: Basic Roof:Generic - 400mm, Basic Roof:Generic - 400mm:901206
In: Katus
Material: _ol.olev sein 800 mm
Pset_ElementShading - Roughness: 914.4 mm
Pset_ProductRequirements - Category: Roofs
Pset_QuantityTakeOff - Reference: Generic - 400mm
Pset_RoofCommon - Reference: Generic - 400mm; IsExternal: yes; ProjectedArea: 528.817 m2; TotalArea: 525.055 m2

# IfcSlab: Floor:Generic 200mm (3)
Type - PredefinedType: FLOOR; Material: EST. Betoon. Armeeritud. Monteeritav(1) 300 mm
Type - Pset_ElementShading - Roughness: 914.4 mm
Type - Pset_ProductRequirements - Category: Floors
Type - Pset_QuantityTakeOff - Reference: Generic 200mm
Type - Pset_ReinforcementBarPitchOfSlab - Reference: Generic 200mm
Type - Pset_SlabCommon - IsExternal: no; Reference: Generic 200mm
Pset_QuantityTakeOff - sets with these values: 2
Pset_SlabCommon - LoadBearing: no; PitchAngle: 0 deg
Name (Floor:Generic 200mm:...) | In
1062543 | Katus
1137078 | 1 Korrus
1138762 | 1 Korrus

# IfcSlab: Floor:P-01_Põrand pinnasel 400mm, Floor:P-01_Põrand pinnasel 400mm:1045070
In: 0 Sokkel
Type - PredefinedType: FLOOR; Material: EST. Betoon. Armeeritud. Kohtvalu 100 mm, EST. Soojustus. EPS. Default 100 mm, EST. Soojustus. EPS. Default 50 mm
Type - Pset_ElementShading - Roughness: 914.4 mm
Type - Pset_ProductRequirements - Category: Floors
Type - Pset_QuantityTakeOff - Reference: P-01_Põrand pinnasel 400mm
Type - Pset_ReinforcementBarPitchOfSlab - Reference: P-01_Põrand pinnasel 400mm
Type - Pset_SlabCommon - IsExternal: no; Reference: P-01_Põrand pinnasel 400mm
Pset_QuantityTakeOff - sets with these values: 2
Pset_SlabCommon - LoadBearing: no; PitchAngle: 0 deg

# IfcSlab: Floor:VL-00_R/B 370mm, Floor:VL-00_R/B 370mm:878167
In: Sissepääs
Type - PredefinedType: FLOOR; Material: EST. Betoon. Armeeritud. Kohtvalu 60 mm, EST. Soojustus. Mineraalvill. Default 30 mm, EST. Betoon. Armeeritud. Monteeritav(1) 220 mm
Type - Pset_ElementShading - Roughness: 914.4 mm
Type - Pset_ProductRequirements - Category: Floors
Type - Pset_QuantityTakeOff - Reference: VL-00_R/B 370mm
Type - Pset_ReinforcementBarPitchOfSlab - Reference: VL-00_R/B 370mm
Type - Pset_SlabCommon - IsExternal: no; Reference: VL-00_R/B 370mm
Pset_QuantityTakeOff - sets with these values: 2
Pset_SlabCommon - LoadBearing: no; PitchAngle: 0 deg

# IfcSlab: Floor:VL-00_R/B 370mm 1 k 1, Floor:VL-00_R/B 370mm 1 k 1:850151
In: 1 Korrus
Type - PredefinedType: FLOOR; Material: EST. Betoon. Armeeritud. Kohtvalu 60 mm, EST. Soojustus. Mineraalvill. Default 30 mm, EST. Puistematerjal. Kergkruus 100 mm, EST. Betoon. Armeeritud. Monteeritav(1) 220 mm
Type - Pset_ElementShading - Roughness: 914.4 mm
Type - Pset_ProductRequirements - Category: Floors
Type - Pset_QuantityTakeOff - Reference: VL-00_R/B 370mm 1 k 1
Type - Pset_ReinforcementBarPitchOfSlab - Reference: VL-00_R/B 370mm 1 k 1
Type - Pset_SlabCommon - IsExternal: no; Reference: VL-00_R/B 370mm 1 k 1
Pset_QuantityTakeOff - sets with these values: 2
Pset_SlabCommon - LoadBearing: no; PitchAngle: 0 deg

# IfcSlab: Floor:VL-00_R/B 370mm 1 k 2, Floor:VL-00_R/B 370mm 1 k 2:1208063
In: 1 Korrus
Type - PredefinedType: FLOOR; Material: EST. Betoon. Armeeritud. Kohtvalu 60 mm, EST. Soojustus. Mineraalvill. Default 30 mm, EST. Puistematerjal. Kergkruus 40 mm, EST. Betoon. Armeeritud. Monteeritav(1) 220 mm
Type - Pset_ElementShading - Roughness: 914.4 mm
Type - Pset_ProductRequirements - Category: Floors
Type - Pset_QuantityTakeOff - Reference: VL-00_R/B 370mm 1 k 2
Type - Pset_ReinforcementBarPitchOfSlab - Reference: VL-00_R/B 370mm 1 k 2
Type - Pset_SlabCommon - IsExternal: no; Reference: VL-00_R/B 370mm 1 k 2
Pset_QuantityTakeOff - sets with these values: 2
Pset_SlabCommon - LoadBearing: no; PitchAngle: 0 deg

# IfcSlab: Floor:VL-00_R/B 370mm 1 k 2, Floor:VL-00_R/B 370mm 1 k 2:1173232
In: 1 Korrus
Type - PredefinedType: FLOOR
Type - Pset_ElementShading - Roughness: 914.4 mm
Type - Pset_ProductRequirements - Category: Floors
Type - Pset_QuantityTakeOff - Reference: VL-00_R/B 370mm 1 k 2
Type - Pset_ReinforcementBarPitchOfSlab - Reference: VL-00_R/B 370mm 1 k 2
Type - Pset_SlabCommon - IsExternal: no; Reference: VL-00_R/B 370mm 1 k 2
Material: EST. Betoon. Armeeritud. Kohtvalu, EST. Soojustus. Mineraalvill. Default, EST. Puistematerjal. Kergkruus, EST. Betoon. Armeeritud. Monteeritav(1)
Pset_QuantityTakeOff - sets with these values: 2
Pset_SlabCommon - LoadBearing: no; PitchAngle: 0 deg

# IfcSlab: Floor:VL-00_R/B 370mm 2 k, Floor:VL-00_R/B 370mm 2 k:861033
In: 2 Korrus
Type - PredefinedType: FLOOR; Material: EST. Betoon. Armeeritud. Kohtvalu 60 mm, EST. Soojustus. Mineraalvill. Default 30 mm, EST. Puistematerjal. Kergkruus 40 mm, EST. Betoon. Armeeritud. Monteeritav(1) 220 mm
Type - Pset_ElementShading - Roughness: 914.4 mm
Type - Pset_ProductRequirements - Category: Floors
Type - Pset_QuantityTakeOff - Reference: VL-00_R/B 370mm 2 k
Type - Pset_ReinforcementBarPitchOfSlab - Reference: VL-00_R/B 370mm 2 k
Type - Pset_SlabCommon - IsExternal: no; Reference: VL-00_R/B 370mm 2 k
Pset_QuantityTakeOff - sets with these values: 2
Pset_SlabCommon - LoadBearing: no; PitchAngle: 0 deg

# IfcSlab: Floor:VL-00_R/B 370mm 2 k 2 (2)
Type - PredefinedType: FLOOR; Material: EST. Betoon. Armeeritud. Kohtvalu 60 mm, EST. Soojustus. Mineraalvill. Default 30 mm, EST. Puistematerjal. Kergkruus 20 mm, EST. Betoon. Armeeritud. Monteeritav(1) 220 mm
Type - Pset_ElementShading - Roughness: 914.4 mm
Type - Pset_ProductRequirements - Category: Floors
Type - Pset_QuantityTakeOff - Reference: VL-00_R/B 370mm 2 k 2
Type - Pset_ReinforcementBarPitchOfSlab - Reference: VL-00_R/B 370mm 2 k 2
Type - Pset_SlabCommon - IsExternal: no; Reference: VL-00_R/B 370mm 2 k 2
Pset_QuantityTakeOff - sets with these values: 2
Pset_SlabCommon - LoadBearing: no; PitchAngle: 0 deg
Name (Floor:VL-00_R/B 370mm 2 k 2:...) | In
1125109 | 3 Korrus
1125604 | 4 Korrus

# IfcSlab: Floor:VL-00_R/B 370mm 2 k 3 (2)
Type - PredefinedType: FLOOR; Material: EST. Betoon. Armeeritud. Kohtvalu 60 mm, EST. Soojustus. Mineraalvill. Default 30 mm, EST. Betoon. Armeeritud. Monteeritav(1) 220 mm
Type - Pset_ElementShading - Roughness: 914.4 mm
Type - Pset_ProductRequirements - Category: Floors
Type - Pset_QuantityTakeOff - Reference: VL-00_R/B 370mm 2 k 3
Type - Pset_ReinforcementBarPitchOfSlab - Reference: VL-00_R/B 370mm 2 k 3
Type - Pset_SlabCommon - IsExternal: no; Reference: VL-00_R/B 370mm 2 k 3
Pset_QuantityTakeOff - sets with these values: 2
Pset_SlabCommon - LoadBearing: no; PitchAngle: 0 deg
Name (Floor:VL-00_R/B 370mm 2 k 3:...) | In
1124924 | 2 Korrus
1125409 | 1 Korrus

# IfcSlab: Floor:VL-00_R/B 370mm 3 k, Floor:VL-00_R/B 370mm 3 k:861328
In: 3 Korrus
Type - PredefinedType: FLOOR; Material: EST. Betoon. Armeeritud. Kohtvalu 60 mm, EST. Soojustus. Mineraalvill. Default 30 mm, EST. Puistematerjal. Kergkruus 40 mm, EST. Betoon. Armeeritud. Monteeritav(1) 220 mm
Type - Pset_ElementShading - Roughness: 914.4 mm
Type - Pset_ProductRequirements - Category: Floors
Type - Pset_QuantityTakeOff - Reference: VL-00_R/B 370mm 3 k
Type - Pset_ReinforcementBarPitchOfSlab - Reference: VL-00_R/B 370mm 3 k
Type - Pset_SlabCommon - IsExternal: no; Reference: VL-00_R/B 370mm 3 k
Pset_QuantityTakeOff - sets with these values: 2
Pset_SlabCommon - LoadBearing: no; PitchAngle: 0 deg

# IfcSlab: Floor:VL-00_R/B 370mm 4 k, Floor:VL-00_R/B 370mm 4 k:861373
In: 4 Korrus
Type - PredefinedType: FLOOR; Material: EST. Betoon. Armeeritud. Kohtvalu 60 mm, EST. Soojustus. Mineraalvill. Default 30 mm, EST. Puistematerjal. Kergkruus 30 mm, EST. Betoon. Armeeritud. Monteeritav(1) 220 mm
Type - Pset_ElementShading - Roughness: 914.4 mm
Type - Pset_ProductRequirements - Category: Floors
Type - Pset_QuantityTakeOff - Reference: VL-00_R/B 370mm 4 k
Type - Pset_ReinforcementBarPitchOfSlab - Reference: VL-00_R/B 370mm 4 k
Type - Pset_SlabCommon - IsExternal: no; Reference: VL-00_R/B 370mm 4 k
Pset_QuantityTakeOff - sets with these values: 2
Pset_SlabCommon - LoadBearing: no; PitchAngle: 0 deg

# IfcSlab: Floor:VL-00_karkass 50 pluss plaat (5)
In: 0 Sokkel
Type - PredefinedType: FLOOR; Material: EST. Ehitusplaat. OSB 20 mm, EST. Õhkvahe. Roov. Kipsplaadi alusroov. Vertikaalne 50 mm
Type - Pset_ElementShading - Roughness: 914.4 mm
Type - Pset_ProductRequirements - Category: Floors
Type - Pset_QuantityTakeOff - Reference: VL-00_karkass 50 pluss plaat
Type - Pset_ReinforcementBarPitchOfSlab - Reference: VL-00_karkass 50 pluss plaat
Type - Pset_SlabCommon - IsExternal: no; Reference: VL-00_karkass 50 pluss plaat
Pset_QuantityTakeOff - sets with these values: 2
Pset_SlabCommon - LoadBearing: no; PitchAngle: 0 deg
Name (Floor:VL-00_karkass 50 pluss plaat:...)
1035876
1036409
1036530
1040045
1321384:7

# IfcSlab: Floor:VL-00_karkass 50 pluss plaat (6)
In: 0 Sokkel
Type - PredefinedType: FLOOR
Type - Pset_ElementShading - Roughness: 914.4 mm
Type - Pset_ProductRequirements - Category: Floors
Type - Pset_QuantityTakeOff - Reference: VL-00_karkass 50 pluss plaat
Type - Pset_ReinforcementBarPitchOfSlab - Reference: VL-00_karkass 50 pluss plaat
Type - Pset_SlabCommon - IsExternal: no; Reference: VL-00_karkass 50 pluss plaat
Material: EST. Ehitusplaat. OSB 20 mm, EST. Õhkvahe. Roov. Kipsplaadi alusroov. Vertikaalne 50 mm
Pset_QuantityTakeOff - sets with these values: 2
Pset_SlabCommon - LoadBearing: no; PitchAngle: 0 deg
Name (Floor:VL-00_karkass 50 pluss plaat:...)
1321384
1321384:2
1321384:3
1321384:4
1321384:5
1321384:6

# IfcSlab: Monolithic Landing:300 mm Thickness (16)
Type - PredefinedType: LANDING
Type - Pset_ProductRequirements - Category: Landings
Type - Pset_QuantityTakeOff - Reference: 300 mm Thickness
Type - Pset_ReinforcementBarPitchOfSlab - Reference: 300 mm Thickness
Type - Pset_SlabCommon - IsExternal: no; Reference: 300 mm Thickness
Pset_QuantityTakeOff - sets with these values: 2
Pset_SlabCommon - PitchAngle: 0 deg
Name (Cast-In-Place Stair:Stair:...) | In
910648 Landing 1 | 0 Sokkel
911102 Landing 1 | 0 Sokkel
911166 Landing 1 | 0 Sokkel
912326 Landing 1 | 2 Korrus
912932 Landing 1 | 3 Korrus
914901 Landing 1 | 0 Sokkel
915214 Landing 1 | 2 Korrus
916944 Landing 1 | 1 Korrus
916967 Landing 1 | 1 Korrus
1045978 Landing 1 | 3 Korrus
1055754 Landing 1 | 2 Korrus
1055920 Landing 1 | 3 Korrus
1067786 Landing 1 | 1 Korrus
1077466 Landing 1 | 1 Korrus
1077753 Landing 1 | 2 Korrus
1077825 Landing 1 | 3 Korrus

# IfcStair: Cast-In-Place Stair:Cast-In-Place Stair (16)
ShapeType: STRAIGHT_RUN_STAIR
Pset_ProductRequirements - Category: Stairs
Pset_QuantityTakeOff - Reference: Cast-In-Place Stair
Pset_StairCommon - IsExternal: no; Reference: Cast-In-Place Stair
Name (Cast-In-Place Stair:Stair:...) | In | NumberOfRiser | NumberOfTreads | RiserHeight (mm) | TreadLength (mm)
910648 | 0 Sokkel | 9 | 8 | 154.444 | 300
911102 | 0 Sokkel | 9 | 8 | 155.556 | 300
911166 | 0 Sokkel | 9 | 8 | 152.222 | 300
912326 | 2 Korrus | 11 | 10 | 149.091 | 300
912932 | 3 Korrus | 11 | 10 | 147.273 | 300
914901 | 0 Sokkel | 9 | 8 | 150 | 295
915214 | 2 Korrus | 11 | 10 | 150 | 300
916944 | 1 Korrus | 11 | 10 | 148.182 | 300
916967 | 1 Korrus | 11 | 10 | 148.182 | 300
1045978 | 3 Korrus | 11 | 10 | 150 | 300
1055754 | 2 Korrus | 11 | 10 | 149.091 | 300
1055920 | 3 Korrus | 11 | 10 | 150 | 300
1067786 | 1 Korrus | 11 | 10 | 153.636 | 300
1077466 | 1 Korrus | 11 | 10 | 148.182 | 300
1077753 | 2 Korrus | 11 | 10 | 150 | 300
1077825 | 3 Korrus | 11 | 10 | 152.727 | 300

# IfcStair: Stairs 1:Stairs 1 (2)
In: 0 Sokkel
Name (Stairs 1:Stairs 1:...)
1184061
1184061 | Pset_ProductRequirements - Category: Stairs; Pset_QuantityTakeOff - Reference: Stairs 1; Pset_StairCommon - IsExternal: no; Reference: Stairs 1

# IfcStair: Stairs 2:Stairs 2 (2)
In: 0 Sokkel
Name (Stairs 2:Stairs 2:...)
1172025
1172025 | Pset_ProductRequirements - Category: Stairs; Pset_QuantityTakeOff - Reference: Stairs 2; Pset_StairCommon - IsExternal: no; Reference: Stairs 2

# IfcStairFlight: Monolithic Run:Monolithic Run (8)
Type - PredefinedType: STRAIGHT
Type - Pset_ProductRequirements - Category: Runs
Type - Pset_QuantityTakeOff - Reference: Monolithic Run
Type - Pset_StairFlightCommon - Reference: Monolithic Run; NosingLength: 0 mm
Material: EST. Betoon. Armeeritud. Monteeritav(1)
Name (Cast-In-Place Stair:Stair:...) | In | NumberOfRiser = Pset_StairFlightCommon, NumberOfRiser | NumberOfTreads = Pset_StairFlightCommon, NumberOfTreads | RiserHeight (mm) | TreadLength (mm) | Pset_StairFlightCommon, RiserHeight (mm) | Pset_StairFlightCommon, TreadLength (mm) = TreadLengthAtOffset (mm) = TreadLengthAtInnerSide (mm) | WalkingLineOffset (mm)
910648 Run 1 | 0 Sokkel | 9 | 8 | 0.506707 | 0.984252 | 154.444 | 300 | 2.13255
911102 Run 1 | 0 Sokkel | 9 | 8 | 0.510353 | 0.984252 | 155.556 | 300 | 2.13255
912326 Run 1 | 2 Korrus | 11 | 10 | 0.489143 | 0.984252 | 149.091 | 300 | 2.25558
912932 Run 1 | 3 Korrus | 11 | 10 | 0.483178 | 0.984252 | 147.273 | 300 | 2.25558
914901 Run 1 | 0 Sokkel | 9 | 8 | 0.492126 | 0.967848 | 150 | 295 | 2.25679
915214 Run 1 | 2 Korrus | 11 | 10 | 0.492126 | 0.984252 | 150 | 300 | 2.25558
1045978 Run 1 | 3 Korrus | 11 | 10 | 0.492126 | 0.984252 | 150 | 300 | 2.25558
1067786 Run 1 | 1 Korrus | 11 | 10 | 0.504056 | 0.984252 | 153.636 | 300 | 2.25558

# IfcStairFlight: Monolithic Run:Monolithic Run (8)
Type - Pset_ProductRequirements - Category: Runs
Type - Pset_QuantityTakeOff - Reference: Monolithic Run
Type - Pset_StairFlightCommon - Reference: Monolithic Run; NosingLength: 0 mm
TreadLength: 0.984252 mm; Material: EST. Betoon. Armeeritud. Monteeritav(1)
Pset_StairFlightCommon - TreadLength: 300 mm; TreadLengthAtOffset: 300 mm; TreadLengthAtInnerSide: 300 mm
Name (Cast-In-Place Stair:Stair:...) | In | NumberOfRiser = Pset_StairFlightCommon, NumberOfRiser | NumberOfTreads = Pset_StairFlightCommon, NumberOfTreads | RiserHeight (mm) | Pset_StairFlightCommon, RiserHeight (mm)
911166 Run 1 | 0 Sokkel | 9 | 8 | 0.499417 | 152.222
916944 Run 1 | 1 Korrus | 11 | 10 | 0.486161 | 148.182
916967 Run 1 | 1 Korrus | 11 | 10 | 0.486161 | 148.182
1055754 Run 1 | 2 Korrus | 11 | 10 | 0.489143 | 149.091
1055920 Run 1 | 3 Korrus | 11 | 10 | 0.492126 | 150
1077466 Run 1 | 1 Korrus | 11 | 10 | 0.486161 | 148.182
1077753 Run 1 | 2 Korrus | 11 | 10 | 0.492126 | 150
1077825 Run 1 | 3 Korrus | 11 | 10 | 0.501074 | 152.727

# IfcWall: Basic Wall:Generic - 280mm, Basic Wall:Generic - 280mm:780018
In: 2 Korrus
Type - PredefinedType: STANDARD; Material: _ol.olev sein 280 mm
Type - Pset_ConcreteElementGeneral - FireRating: EI-60
Type - Pset_ElementShading - Roughness: 914.4 mm
Type - Pset_ProductRequirements - Category: Walls
Type - Pset_QuantityTakeOff - Reference: Generic - 280mm
Type - Pset_ReinforcementBarPitchOfWall - Reference: Generic - 280mm
Type - Pset_WallCommon - IsExternal: no; Reference: Generic - 280mm; AcousticRating: 52 dB; FireRating: EI-60
Pset_QuantityTakeOff - sets with these values: 2
Pset_WallCommon - ExtendToStructure: no; LoadBearing: no

# IfcWall: Basic Wall:Generic - 400mm (2)
Type - PredefinedType: STANDARD; Material: _ol.olev sein 400 mm
Type - Pset_ConcreteElementGeneral - FireRating: EI-60
Type - Pset_ElementShading - Roughness: 914.4 mm
Type - Pset_ProductRequirements - Category: Walls
Type - Pset_QuantityTakeOff - Reference: Generic - 400mm
Type - Pset_ReinforcementBarPitchOfWall - Reference: Generic - 400mm
Type - Pset_WallCommon - IsExternal: no; Reference: Generic - 400mm; AcousticRating: 52 dB; FireRating: EI-60
Pset_QuantityTakeOff - sets with these values: 2
Pset_WallCommon - ExtendToStructure: no; LoadBearing: no
Name (Basic Wall:Generic - 400mm:...) | In
774472 | 1 Korrus | Material: _ol.olev sein
780818 | 4 Korrus

# IfcWall: Basic Wall:Generic - 510mm (7)
Type - PredefinedType: STANDARD; Material: _ol.olev sein 510 mm
Type - Pset_ConcreteElementGeneral - FireRating: EI-60
Type - Pset_ElementShading - Roughness: 914.4 mm
Type - Pset_ProductRequirements - Category: Walls
Type - Pset_QuantityTakeOff - Reference: Generic - 510mm
Type - Pset_ReinforcementBarPitchOfWall - Reference: Generic - 510mm
Type - Pset_WallCommon - IsExternal: no; Reference: Generic - 510mm; AcousticRating: 52 dB; FireRating: EI-60
Pset_QuantityTakeOff - sets with these values: 2
Pset_WallCommon - LoadBearing: no
Name (Basic Wall:Generic - 510mm:...) | In | ExtendToStructure
780017 | 2 Korrus | no | Material: _ol.olev sein
780749 | 3 Korrus | no
780750 | 3 Korrus | no
780810 | 4 Korrus | yes
788155 | 0 Sokkel | no
1048189 | 1 Korrus | no
1065093 | 4 Korrus | no

# IfcWall: Basic Wall:Generic - 520mm (2)
Type - PredefinedType: STANDARD; Material: _ol.olev sein 520 mm
Type - Pset_ConcreteElementGeneral - FireRating: EI-60
Type - Pset_ElementShading - Roughness: 914.4 mm
Type - Pset_ProductRequirements - Category: Walls
Type - Pset_QuantityTakeOff - Reference: Generic - 520mm
Type - Pset_ReinforcementBarPitchOfWall - Reference: Generic - 520mm
Type - Pset_WallCommon - IsExternal: no; Reference: Generic - 520mm; AcousticRating: 52 dB; FireRating: EI-60
Pset_QuantityTakeOff - sets with these values: 2
Pset_WallCommon - ExtendToStructure: no; LoadBearing: no
Name (Basic Wall:Generic - 520mm:...) | In
780016 | 2 Korrus
780806 | 4 Korrus

# IfcWall: Basic Wall:Generic - 550mm (2)
Type - PredefinedType: STANDARD; Material: _ol.olev sein 550 mm
Type - Pset_ConcreteElementGeneral - FireRating: EI-60
Type - Pset_ElementShading - Roughness: 914.4 mm
Type - Pset_ProductRequirements - Category: Walls
Type - Pset_QuantityTakeOff - Reference: Generic - 550mm
Type - Pset_ReinforcementBarPitchOfWall - Reference: Generic - 550mm
Type - Pset_WallCommon - IsExternal: no; Reference: Generic - 550mm; AcousticRating: 52 dB; FireRating: EI-60
Pset_QuantityTakeOff - sets with these values: 2
Pset_WallCommon - ExtendToStructure: no; LoadBearing: no
Name (Basic Wall:Generic - 550mm:...) | In
783108 | 0 Sokkel
1069874 | 4 Korrus

# IfcWall: Basic Wall:Generic - 620mm, Basic Wall:Generic - 620mm:901727
In: Katus
Type - PredefinedType: STANDARD; Material: _ol.olev sein 620 mm
Type - Pset_ConcreteElementGeneral - FireRating: EI-60
Type - Pset_ElementShading - Roughness: 914.4 mm
Type - Pset_ProductRequirements - Category: Walls
Type - Pset_QuantityTakeOff - Reference: Generic - 620mm
Type - Pset_ReinforcementBarPitchOfWall - Reference: Generic - 620mm
Type - Pset_WallCommon - IsExternal: no; Reference: Generic - 620mm; AcousticRating: 52 dB; FireRating: EI-60
Material: _ol.olev sein
Pset_QuantityTakeOff - sets with these values: 2
Pset_WallCommon - ExtendToStructure: no; LoadBearing: no

# IfcWall: Basic Wall:Generic - 665mm (3)
Type - PredefinedType: STANDARD; Material: _ol.olev sein 665 mm
Type - Pset_ConcreteElementGeneral - FireRating: EI-60
Type - Pset_ElementShading - Roughness: 914.4 mm
Type - Pset_ProductRequirements - Category: Walls
Type - Pset_QuantityTakeOff - Reference: Generic - 665mm
Type - Pset_ReinforcementBarPitchOfWall - Reference: Generic - 665mm
Type - Pset_WallCommon - IsExternal: no; Reference: Generic - 665mm; AcousticRating: 52 dB; FireRating: EI-60
Pset_QuantityTakeOff - sets with these values: 2
Pset_WallCommon - ExtendToStructure: no; LoadBearing: no
Name (Basic Wall:Generic - 665mm:...) | In
771335 | 1 Korrus | Material: _ol.olev sein
780011 | 2 Korrus
780744 | 3 Korrus

# IfcWall: Basic Wall:Generic - 700mm, Basic Wall:Generic - 700mm:1078061
In: 1 Korrus
Type - PredefinedType: STANDARD; Material: _ol.olev sein 700 mm
Type - Pset_ConcreteElementGeneral - FireRating: EI-60
Type - Pset_ElementShading - Roughness: 914.4 mm
Type - Pset_ProductRequirements - Category: Walls
Type - Pset_QuantityTakeOff - Reference: Generic - 700mm
Type - Pset_ReinforcementBarPitchOfWall - Reference: Generic - 700mm
Type - Pset_WallCommon - Reference: Generic - 700mm; AcousticRating: 52 dB; FireRating: EI-60; IsExternal: no
Pset_QuantityTakeOff - sets with these values: 2
Pset_WallCommon - ExtendToStructure: no; LoadBearing: no

# IfcWall: Basic Wall:Generic - 750mm (2)
In: 0 Sokkel
Type - PredefinedType: STANDARD; Material: _ol.olev sein 750 mm
Type - Pset_ConcreteElementGeneral - FireRating: EI-60
Type - Pset_ElementShading - Roughness: 914.4 mm
Type - Pset_ProductRequirements - Category: Walls
Type - Pset_QuantityTakeOff - Reference: Generic - 750mm
Type - Pset_ReinforcementBarPitchOfWall - Reference: Generic - 750mm
Type - Pset_WallCommon - IsExternal: no; Reference: Generic - 750mm; AcousticRating: 52 dB; FireRating: EI-60
Pset_QuantityTakeOff - sets with these values: 2
Pset_WallCommon - ExtendToStructure: no; LoadBearing: no
Name (Basic Wall:Generic - 750mm:...)
783102 | Material: _ol.olev sein
1061879

# IfcWall: Basic Wall:Generic - 770mm (2)
Type - PredefinedType: STANDARD; Material: _ol.olev sein 770 mm
Type - Pset_ConcreteElementGeneral - FireRating: EI-60
Type - Pset_ElementShading - Roughness: 914.4 mm
Type - Pset_ProductRequirements - Category: Walls
Type - Pset_QuantityTakeOff - Reference: Generic - 770mm
Type - Pset_ReinforcementBarPitchOfWall - Reference: Generic - 770mm
Type - Pset_WallCommon - IsExternal: no; Reference: Generic - 770mm; AcousticRating: 52 dB; FireRating: EI-60
Pset_QuantityTakeOff - sets with these values: 2
Pset_WallCommon - ExtendToStructure: no; LoadBearing: no
Name (Basic Wall:Generic - 770mm:...) | In
1065543 | 1 Korrus
1073494 | 3 Korrus

# IfcWall: Basic Wall:SS-03_Kips, 66mm metallkarkass, Basic Wall:SS-03_Kips, 66mm metallkarkass:863622
In: 3 Korrus
Type - PredefinedType: STANDARD; Material: EST. Ehitusplaat. Kipsplaat 12.5 mm, EST. Ehitusplaat. Kipsplaat 12.5 mm, EST. Õhkvahe. Roov. Kipsplaadi alusroov. Vertikaalne 66 mm, EST. Ehitusplaat. Kipsplaat 12.5 mm, EST. Ehitusplaat. Kipsplaat 12.5 mm
Type - Pset_ConcreteElementGeneral - FireRating: EI-60
Type - Pset_ElementShading - Roughness: 914.4 mm
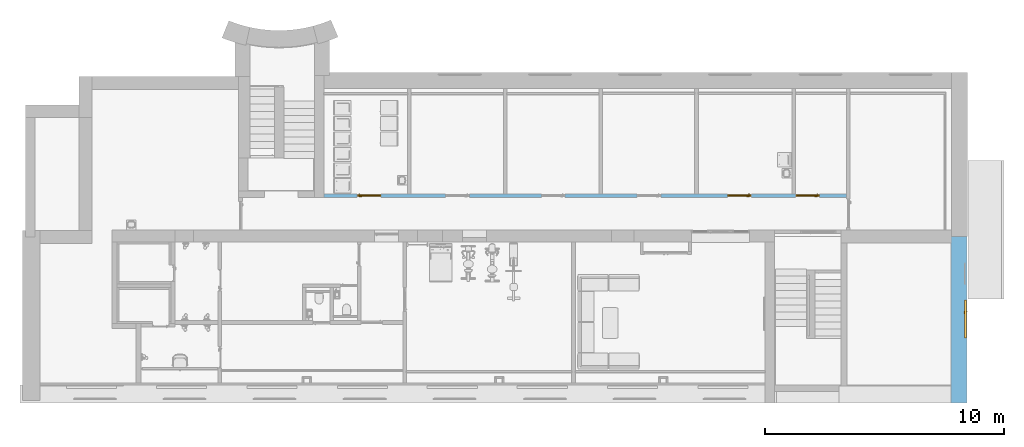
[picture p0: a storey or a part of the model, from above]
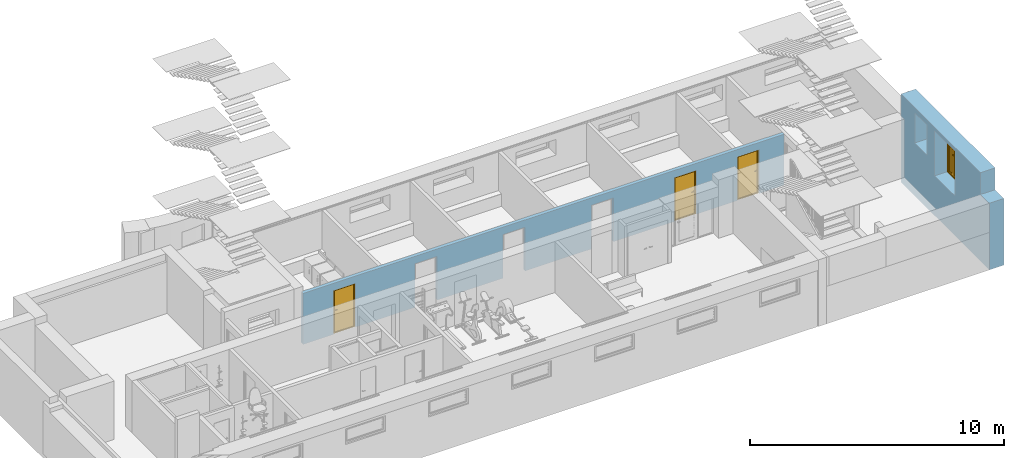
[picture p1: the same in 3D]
Properties of the parts of a building model (IFC2X3), part 4 of 4

# IfcWall: Basic Wall:SS-03_Kips, 66mm metallkarkass, Basic Wall:SS-03_Kips, 66mm metallkarkass:863622
Type - Pset_ProductRequirements - Category: Walls
Type - Pset_QuantityTakeOff - Reference: SS-03_Kips, 66mm metallkarkass
Type - Pset_ReinforcementBarPitchOfWall - Reference: SS-03_Kips, 66mm metallkarkass
Type - Pset_WallCommon - IsExternal: no; Combustible: no; Reference: SS-03_Kips, 66mm metallkarkass; AcousticRating: 48 dB; FireRating: EI-60
Pset_QuantityTakeOff - sets with these values: 2
Pset_WallCommon - ExtendToStructure: no; LoadBearing: no

# IfcWall: Basic Wall:SS-04_Kips, 50+50 mm metallkarkass 2, Basic Wall:SS-04_Kips, 50+50 mm metallkarkass 2:862836
In: 3 Korrus
Type - PredefinedType: STANDARD; Material: EST. Ehitusplaat. Kipsplaat 12.5 mm, EST. Ehitusplaat. Kipsplaat 12.5 mm, EST. Soojustus. Mineraalvill. Default 50 mm, EST. Ehitusplaat. Kipsplaat 12.5 mm, EST. Soojustus. Mineraalvill. Default 50 mm, EST. Ehitusplaat. Kipsplaat 12.5 mm, EST. Ehitusplaat. Kipsplaat 12.5 mm
Type - Pset_ConcreteElementGeneral - FireRating: EI-60
Type - Pset_ElementShading - Roughness: 914.4 mm
Type - Pset_ProductRequirements - Category: Walls
Type - Pset_QuantityTakeOff - Reference: SS-04_Kips, 50+50 mm metallkarkass 2
Type - Pset_ReinforcementBarPitchOfWall - Reference: SS-04_Kips, 50+50 mm metallkarkass 2
Type - Pset_WallCommon - IsExternal: no; Reference: SS-04_Kips, 50+50 mm metallkarkass 2; AcousticRating: 52 dB; FireRating: EI-60; Combustible: no
Pset_QuantityTakeOff - sets with these values: 2
Pset_WallCommon - ExtendToStructure: no; LoadBearing: no

# IfcWall: Basic Wall:SS-05_Kips, 66mm metallkarkass, Basic Wall:SS-05_Kips, 66mm metallkarkass:865946
In: 4 Korrus
Type - PredefinedType: STANDARD; Material: EST. Ehitusplaat. Kipsplaat 12.5 mm, EST. Ehitusplaat. Kipsplaat 12.5 mm, EST. Soojustus. Mineraalvill. Default 66 mm, EST. Ehitusplaat. Kipsplaat 12.5 mm, EST. Ehitusplaat. Kipsplaat 12.5 mm
Type - Pset_ConcreteElementGeneral - FireRating: EI-60
Type - Pset_ElementShading - Roughness: 914.4 mm
Type - Pset_ProductRequirements - Category: Walls
Type - Pset_QuantityTakeOff - Reference: SS-05_Kips, 66mm metallkarkass
Type - Pset_ReinforcementBarPitchOfWall - Reference: SS-05_Kips, 66mm metallkarkass
Type - Pset_WallCommon - IsExternal: no; Combustible: no; Reference: SS-05_Kips, 66mm metallkarkass; AcousticRating: 52 dB; FireRating: EI-60
Pset_QuantityTakeOff - sets with these values: 2
Pset_WallCommon - ExtendToStructure: no; LoadBearing: no

# IfcWallStandardCase: Basic Wall:Generic - 120mm (2)
In: 0 Sokkel
Type - PredefinedType: STANDARD; Material: _ol.olev sein 120 mm
Type - Pset_ElementShading - Roughness: 914.4 mm
Type - Pset_ProductRequirements - Category: Walls
Type - Pset_QuantityTakeOff - Reference: Generic - 120mm
Type - Pset_ReinforcementBarPitchOfWall - Reference: Generic - 120mm
Type - Pset_WallCommon - IsExternal: no; Reference: Generic - 120mm
Pset_QuantityTakeOff - sets with these values: 2
Pset_WallCommon - ExtendToStructure: no; LoadBearing: no
Name (Basic Wall:Generic - 120mm:...)
888521
889309

# IfcWallStandardCase: Basic Wall:Generic - 200mm (3)
In: 0 Sokkel
Type - PredefinedType: STANDARD; Material: _ol.olev sein 200 mm
Type - Pset_ConcreteElementGeneral - FireRating: EI-60
Type - Pset_ElementShading - Roughness: 914.4 mm
Type - Pset_ProductRequirements - Category: Walls
Type - Pset_QuantityTakeOff - Reference: Generic - 200mm
Type - Pset_ReinforcementBarPitchOfWall - Reference: Generic - 200mm
Type - Pset_WallCommon - IsExternal: no; Reference: Generic - 200mm; AcousticRating: 52 dB; FireRating: EI-60
Pset_QuantityTakeOff - sets with these values: 2
Pset_WallCommon - ExtendToStructure: no; LoadBearing: no
Name (Basic Wall:Generic - 200mm:...)
785763
785814
785881

# IfcWallStandardCase: Basic Wall:Generic - 250mm (14)
Type - PredefinedType: STANDARD; Material: _ol.olev sein 250 mm
Type - Pset_ConcreteElementGeneral - FireRating: EI-60
Type - Pset_ElementShading - Roughness: 914.4 mm
Type - Pset_ProductRequirements - Category: Walls
Type - Pset_QuantityTakeOff - Reference: Generic - 250mm
Type - Pset_ReinforcementBarPitchOfWall - Reference: Generic - 250mm
Type - Pset_WallCommon - IsExternal: no; Reference: Generic - 250mm; AcousticRating: 52 dB; FireRating: EI-60
Pset_QuantityTakeOff - sets with these values: 2
Pset_WallCommon - LoadBearing: no
Name (Basic Wall:Generic - 250mm:...) | In | ExtendToStructure
780019 | 2 Korrus | no
780026 | 2 Korrus | no
780752 | 3 Korrus | no
780759 | 3 Korrus | no
780812 | 4 Korrus | yes
780819 | 4 Korrus | no
783113 | 0 Sokkel | no
1072250 | 1 Korrus | no
1074021 | 2 Korrus | no
1074022 | 3 Korrus | no
1074023 | 4 Korrus | no
1074026 | 2 Korrus | no
1074030 | 3 Korrus | no
1080263 | 1 Korrus | no

# IfcWallStandardCase: Basic Wall:Generic - 280mm (13)
Type - PredefinedType: STANDARD; Material: _ol.olev sein 280 mm
Type - Pset_ConcreteElementGeneral - FireRating: EI-60
Type - Pset_ElementShading - Roughness: 914.4 mm
Type - Pset_ProductRequirements - Category: Walls
Type - Pset_QuantityTakeOff - Reference: Generic - 280mm
Type - Pset_ReinforcementBarPitchOfWall - Reference: Generic - 280mm
Type - Pset_WallCommon - IsExternal: no; Reference: Generic - 280mm; AcousticRating: 52 dB; FireRating: EI-60
Pset_QuantityTakeOff - sets with these values: 2
Pset_WallCommon - ExtendToStructure: no; LoadBearing: no
Name (Basic Wall:Generic - 280mm:...) | In
773745 | 1 Korrus
774696 | 1 Korrus
780751 | 3 Korrus
780811 | 4 Korrus
783120 | 0 Sokkel
1044146 | 1 Korrus
1044338 | 2 Korrus
1044577 | 3 Korrus
1060020 | 4 Korrus
1086890 | 1 Korrus
1090000 | 2 Korrus
1090433 | 3 Korrus
1090474 | 4 Korrus

# IfcWallStandardCase: Basic Wall:Generic - 350mm (4)
Type - PredefinedType: STANDARD; Material: _ol.olev sein 350 mm
Type - Pset_ConcreteElementGeneral - FireRating: EI-60
Type - Pset_ElementShading - Roughness: 914.4 mm
Type - Pset_ProductRequirements - Category: Walls
Type - Pset_QuantityTakeOff - Reference: Generic - 350mm
Type - Pset_ReinforcementBarPitchOfWall - Reference: Generic - 350mm
Type - Pset_WallCommon - IsExternal: no; Reference: Generic - 350mm; AcousticRating: 52 dB; FireRating: EI-60
Pset_QuantityTakeOff - sets with these values: 2
Pset_WallCommon - ExtendToStructure: no; LoadBearing: no
Name (Basic Wall:Generic - 350mm:...) | In
780817 | 4 Korrus
889013 | 0 Sokkel
1069410 | 1 Korrus
1069805 | 3 Korrus

# IfcWallStandardCase: Basic Wall:Generic - 380mm (12)
Type - PredefinedType: STANDARD; Material: _ol.olev sein 380 mm
Type - Pset_ConcreteElementGeneral - FireRating: EI-60
Type - Pset_ElementShading - Roughness: 914.4 mm
Type - Pset_ProductRequirements - Category: Walls
Type - Pset_QuantityTakeOff - Reference: Generic - 380mm
Type - Pset_ReinforcementBarPitchOfWall - Reference: Generic - 380mm
Type - Pset_WallCommon - IsExternal: no; Reference: Generic - 380mm; AcousticRating: 52 dB; FireRating: EI-60
Pset_QuantityTakeOff - sets with these values: 2
Pset_WallCommon - ExtendToStructure: no; LoadBearing: no
Name (Basic Wall:Generic - 380mm:...) | In
780020 | 2 Korrus
780021 | 2 Korrus
780753 | 3 Korrus
780754 | 3 Korrus
780813 | 4 Korrus
780814 | 4 Korrus
783114 | 0 Sokkel
783115 | 0 Sokkel
1047778 | 1 Korrus
1058659 | 3 Korrus
1058669 | 4 Korrus
1059319 | 2 Korrus

# IfcWallStandardCase: Basic Wall:Generic - 400mm (16)
Type - PredefinedType: STANDARD; Material: _ol.olev sein 400 mm
Type - Pset_ConcreteElementGeneral - FireRating: EI-60
Type - Pset_ElementShading - Roughness: 914.4 mm
Type - Pset_ProductRequirements - Category: Walls
Type - Pset_QuantityTakeOff - Reference: Generic - 400mm
Type - Pset_ReinforcementBarPitchOfWall - Reference: Generic - 400mm
Type - Pset_WallCommon - IsExternal: no; Reference: Generic - 400mm; AcousticRating: 52 dB; FireRating: EI-60
Pset_QuantityTakeOff - sets with these values: 2
Pset_WallCommon - LoadBearing: no
Name (Basic Wall:Generic - 400mm:...) | In | ExtendToStructure
774572 | 1 Korrus | no
780025 | 2 Korrus | no
780757 | 3 Korrus | no
780758 | 3 Korrus | no
780820 | 4 Korrus | yes
783119 | 0 Sokkel | no
886707 | 0 Sokkel | no
1035077 | 0 Sokkel | no
1069278 | 2 Korrus | no
1070423 | 1 Korrus | no
1070716 | 2 Korrus | no
1071183 | 3 Korrus | no
1071191 | 4 Korrus | no
1073010 | 4 Korrus | no
1080179 | 1 Korrus | no
1101122 | 4 Korrus | yes

# IfcWallStandardCase: Basic Wall:Generic - 420mm (7)
Type - PredefinedType: STANDARD; Material: _ol.olev sein 420 mm
Type - Pset_ConcreteElementGeneral - FireRating: EI-60
Type - Pset_ElementShading - Roughness: 914.4 mm
Type - Pset_ProductRequirements - Category: Walls
Type - Pset_QuantityTakeOff - Reference: Generic - 420mm
Type - Pset_ReinforcementBarPitchOfWall - Reference: Generic - 420mm
Type - Pset_WallCommon - IsExternal: no; Reference: Generic - 420mm; AcousticRating: 52 dB; FireRating: EI-60
Pset_QuantityTakeOff - sets with these values: 2
Pset_WallCommon - ExtendToStructure: no; LoadBearing: no
Name (Basic Wall:Generic - 420mm:...) | In
773390 | 1 Korrus
774841 | 1 Korrus
780027 | 2 Korrus
780760 | 3 Korrus
1086901 | 1 Korrus
1090097 | 2 Korrus
1090622 | 3 Korrus

# IfcWallStandardCase: Basic Wall:Generic - 450mm (10)
Type - PredefinedType: STANDARD; Material: _ol.olev sein 450 mm
Type - Pset_ConcreteElementGeneral - FireRating: EI-60
Type - Pset_ElementShading - Roughness: 914.4 mm
Type - Pset_ProductRequirements - Category: Walls
Type - Pset_QuantityTakeOff - Reference: Generic - 450mm
Type - Pset_ReinforcementBarPitchOfWall - Reference: Generic - 450mm
Type - Pset_WallCommon - IsExternal: no; Reference: Generic - 450mm; AcousticRating: 52 dB; FireRating: EI-60
Pset_QuantityTakeOff - sets with these values: 2
Pset_WallCommon - ExtendToStructure: no; LoadBearing: no
Name (Basic Wall:Generic - 450mm:...) | In
780014 | 2 Korrus
780747 | 3 Korrus
780809 | 4 Korrus
1047984 | 1 Korrus
1060041 | Katus
1074028 | 3 Korrus
1125028 | 2 Korrus
1125291 | 1 Korrus
1125567 | 3 Korrus
1125690 | 4 Korrus

# IfcWallStandardCase: Basic Wall:Generic - 457mm, Basic Wall:Generic - 457mm:780774
In: 3 Korrus
Type - PredefinedType: STANDARD; Material: _ol.olev sein 457 mm
Type - Pset_ConcreteElementGeneral - FireRating: EI-60
Type - Pset_ElementShading - Roughness: 914.4 mm
Type - Pset_ProductRequirements - Category: Walls
Type - Pset_QuantityTakeOff - Reference: Generic - 457mm
Type - Pset_ReinforcementBarPitchOfWall - Reference: Generic - 457mm
Type - Pset_WallCommon - IsExternal: no; Reference: Generic - 457mm; AcousticRating: 52 dB; FireRating: EI-60
Pset_QuantityTakeOff - sets with these values: 2
Pset_WallCommon - ExtendToStructure: no; LoadBearing: no

# IfcWallStandardCase: Basic Wall:Generic - 470mm (12)
Type - PredefinedType: STANDARD; Material: _ol.olev sein 470 mm
Type - Pset_ConcreteElementGeneral - FireRating: EI-60
Type - Pset_ElementShading - Roughness: 914.4 mm
Type - Pset_ProductRequirements - Category: Walls
Type - Pset_QuantityTakeOff - Reference: Generic - 470mm
Type - Pset_ReinforcementBarPitchOfWall - Reference: Generic - 470mm
Type - Pset_WallCommon - IsExternal: no; Reference: Generic - 470mm; AcousticRating: 52 dB; FireRating: EI-60
Pset_QuantityTakeOff - sets with these values: 2
Pset_WallCommon - ExtendToStructure: no; LoadBearing: no
Name (Basic Wall:Generic - 470mm:...) | In
780040 | 2 Korrus
780773 | 3 Korrus
780807 | 4 Korrus
780833 | 4 Korrus
1034883 | 0 Sokkel
1071733 | 1 Korrus
1092629 | 0 Sokkel
1096416 | 2 Korrus
1096638 | 3 Korrus
1099366 | 0 Sokkel
1099475 | 1 Korrus
1101265 | 4 Korrus

# IfcWallStandardCase: Basic Wall:Generic - 510mm (3)
Type - PredefinedType: STANDARD; Material: _ol.olev sein 510 mm
Type - Pset_ConcreteElementGeneral - FireRating: EI-60
Type - Pset_ElementShading - Roughness: 914.4 mm
Type - Pset_ProductRequirements - Category: Walls
Type - Pset_QuantityTakeOff - Reference: Generic - 510mm
Type - Pset_ReinforcementBarPitchOfWall - Reference: Generic - 510mm
Type - Pset_WallCommon - IsExternal: no; Reference: Generic - 510mm; AcousticRating: 52 dB; FireRating: EI-60
Pset_QuantityTakeOff - sets with these values: 2
Pset_WallCommon - ExtendToStructure: no; LoadBearing: no
Name (Basic Wall:Generic - 510mm:...) | In
787894 | 0 Sokkel
1046814 | 0 Sokkel
1074024 | 2 Korrus

# IfcWallStandardCase: Basic Wall:Generic - 520mm (8)
Type - PredefinedType: STANDARD; Material: _ol.olev sein 520 mm
Type - Pset_ConcreteElementGeneral - FireRating: EI-60
Type - Pset_ElementShading - Roughness: 914.4 mm
Type - Pset_ProductRequirements - Category: Walls
Type - Pset_QuantityTakeOff - Reference: Generic - 520mm
Type - Pset_ReinforcementBarPitchOfWall - Reference: Generic - 520mm
Type - Pset_WallCommon - IsExternal: no; Reference: Generic - 520mm; AcousticRating: 52 dB; FireRating: EI-60
Pset_QuantityTakeOff - sets with these values: 2
Pset_WallCommon - ExtendToStructure: no; LoadBearing: no
Name (Basic Wall:Generic - 520mm:...) | In
771521 | 1 Korrus
780012 | 2 Korrus
780013 | 2 Korrus
780024 | 2 Korrus
780745 | 3 Korrus
780746 | 3 Korrus
780805 | 4 Korrus
783106 | 0 Sokkel

# IfcWallStandardCase: Basic Wall:Generic - 535mm, Basic Wall:Generic - 535mm:1053386
In: 1 Korrus
Type - PredefinedType: STANDARD; Material: _ol.olev sein 535 mm
Type - Pset_ConcreteElementGeneral - FireRating: EI-60
Type - Pset_ElementShading - Roughness: 914.4 mm
Type - Pset_ProductRequirements - Category: Walls
Type - Pset_QuantityTakeOff - Reference: Generic - 535mm
Type - Pset_ReinforcementBarPitchOfWall - Reference: Generic - 535mm
Type - Pset_WallCommon - IsExternal: no; Reference: Generic - 535mm; AcousticRating: 52 dB; FireRating: EI-60
Pset_QuantityTakeOff - sets with these values: 2
Pset_WallCommon - ExtendToStructure: no; LoadBearing: no

# IfcWallStandardCase: Basic Wall:Generic - 550mm (9)
Type - PredefinedType: STANDARD; Material: _ol.olev sein 550 mm
Type - Pset_ConcreteElementGeneral - FireRating: EI-60
Type - Pset_ElementShading - Roughness: 914.4 mm
Type - Pset_ProductRequirements - Category: Walls
Type - Pset_QuantityTakeOff - Reference: Generic - 550mm
Type - Pset_ReinforcementBarPitchOfWall - Reference: Generic - 550mm
Type - Pset_WallCommon - IsExternal: no; Reference: Generic - 550mm; AcousticRating: 52 dB; FireRating: EI-60
Pset_QuantityTakeOff - sets with these values: 2
Pset_WallCommon - ExtendToStructure: no; LoadBearing: no
Name (Basic Wall:Generic - 550mm:...) | In
771425 | 1 Korrus
773525 | 1 Korrus
783107 | 0 Sokkel
783110 | 0 Sokkel
783111 | 0 Sokkel
783121 | 0 Sokkel
788686 | 1 Korrus
1069359 | 1 Korrus
1069766 | 3 Korrus

# IfcWallStandardCase: Basic Wall:Generic - 600mm (8)
Type - PredefinedType: STANDARD; Material: _ol.olev sein 600 mm
Type - Pset_ConcreteElementGeneral - FireRating: EI-60
Type - Pset_ElementShading - Roughness: 914.4 mm
Type - Pset_ProductRequirements - Category: Walls
Type - Pset_QuantityTakeOff - Reference: Generic - 600mm
Type - Pset_ReinforcementBarPitchOfWall - Reference: Generic - 600mm
Type - Pset_WallCommon - IsExternal: no; Reference: Generic - 600mm; AcousticRating: 52 dB; FireRating: EI-60
Pset_QuantityTakeOff - sets with these values: 2
Pset_WallCommon - ExtendToStructure: no; LoadBearing: no
Name (Basic Wall:Generic - 600mm:...) | In
774334 | 1 Korrus
780022 | 2 Korrus
901726 | Katus
1064530 | 3 Korrus
1064771 | 2 Korrus
1064836 | 3 Korrus
1064889 | 4 Korrus
1064999 | 4 Korrus

# IfcWallStandardCase: Basic Wall:Generic - 630mm (2)
In: 0 Sokkel
Type - PredefinedType: STANDARD; Material: _ol.olev sein 630 mm
Type - Pset_ConcreteElementGeneral - FireRating: EI-60
Type - Pset_ElementShading - Roughness: 914.4 mm
Type - Pset_ProductRequirements - Category: Walls
Type - Pset_QuantityTakeOff - Reference: Generic - 630mm
Type - Pset_ReinforcementBarPitchOfWall - Reference: Generic - 630mm
Type - Pset_WallCommon - IsExternal: no; Reference: Generic - 630mm; AcousticRating: 52 dB; FireRating: EI-60
Pset_QuantityTakeOff - sets with these values: 2
Pset_WallCommon - ExtendToStructure: no; LoadBearing: no
Name (Basic Wall:Generic - 630mm:...)
783118
1034815

# IfcWallStandardCase: Basic Wall:Generic - 650mm (4)
Type - PredefinedType: STANDARD; Material: _ol.olev sein 650 mm
Type - Pset_ConcreteElementGeneral - FireRating: EI-60
Type - Pset_ElementShading - Roughness: 914.4 mm
Type - Pset_ProductRequirements - Category: Walls
Type - Pset_QuantityTakeOff - Reference: Generic - 650mm
Type - Pset_ReinforcementBarPitchOfWall - Reference: Generic - 650mm
Type - Pset_WallCommon - IsExternal: no; Reference: Generic - 650mm; AcousticRating: 52 dB; FireRating: EI-60
Pset_QuantityTakeOff - sets with these values: 2
Pset_WallCommon - ExtendToStructure: no; LoadBearing: no
Name (Basic Wall:Generic - 650mm:...) | In
772438 | 1 Korrus
780015 | 2 Korrus
780748 | 3 Korrus
780808 | 4 Korrus

# IfcWallStandardCase: Basic Wall:Generic - 665mm (4)
Type - PredefinedType: STANDARD; Material: _ol.olev sein 665 mm
Type - Pset_ConcreteElementGeneral - FireRating: EI-60
Type - Pset_ElementShading - Roughness: 914.4 mm
Type - Pset_ProductRequirements - Category: Walls
Type - Pset_QuantityTakeOff - Reference: Generic - 665mm
Type - Pset_ReinforcementBarPitchOfWall - Reference: Generic - 665mm
Type - Pset_WallCommon - IsExternal: no; Reference: Generic - 665mm; AcousticRating: 52 dB; FireRating: EI-60
Pset_QuantityTakeOff - sets with these values: 2
Pset_WallCommon - ExtendToStructure: no; LoadBearing: no
Name (Basic Wall:Generic - 665mm:...) | In
780804 | 4 Korrus
783109 | 0 Sokkel
786336 | 0 Sokkel
1081037 | 0 Sokkel

# IfcWallStandardCase: Basic Wall:Generic - 680mm, Basic Wall:Generic - 680mm:780801
In: 4 Korrus
Type - PredefinedType: STANDARD; Material: _ol.olev sein 680 mm
Type - Pset_ConcreteElementGeneral - FireRating: EI-60
Type - Pset_ElementShading - Roughness: 914.4 mm
Type - Pset_ProductRequirements - Category: Walls
Type - Pset_QuantityTakeOff - Reference: Generic - 680mm
Type - Pset_ReinforcementBarPitchOfWall - Reference: Generic - 680mm
Type - Pset_WallCommon - IsExternal: no; Reference: Generic - 680mm; AcousticRating: 52 dB; FireRating: EI-60
Pset_QuantityTakeOff - sets with these values: 2
Pset_WallCommon - ExtendToStructure: no; LoadBearing: no

# IfcWallStandardCase: Basic Wall:Generic - 700mm (18)
Type - PredefinedType: STANDARD; Material: _ol.olev sein 700 mm
Type - Pset_ConcreteElementGeneral - FireRating: EI-60
Type - Pset_ElementShading - Roughness: 914.4 mm
Type - Pset_ProductRequirements - Category: Walls
Type - Pset_QuantityTakeOff - Reference: Generic - 700mm
Type - Pset_ReinforcementBarPitchOfWall - Reference: Generic - 700mm
Type - Pset_WallCommon - Reference: Generic - 700mm; AcousticRating: 52 dB; FireRating: EI-60; IsExternal: no
Pset_QuantityTakeOff - sets with these values: 2
Pset_WallCommon - ExtendToStructure: no; LoadBearing: no
Name (Basic Wall:Generic - 700mm:...) | In
770859 | 1 Korrus
780008 | 2 Korrus
780741 | 3 Korrus
780742 | 3 Korrus
780802 | 4 Korrus
901831 | Katus
1045941 | 2 Korrus
1046494 | 1 Korrus
1063064 | 1 Korrus
1073612 | 4 Korrus
1074330 | 3 Korrus
1074550 | 0 Sokkel
1075490 | 2 Korrus
1096458 | 2 Korrus
1096658 | 3 Korrus
1099428 | 0 Sokkel
1099487 | 1 Korrus
1101285 | 4 Korrus

# IfcWallStandardCase: Basic Wall:Generic - 750mm (2)
In: 0 Sokkel
Type - PredefinedType: STANDARD; Material: _ol.olev sein 750 mm
Type - Pset_ConcreteElementGeneral - FireRating: EI-60
Type - Pset_ElementShading - Roughness: 914.4 mm
Type - Pset_ProductRequirements - Category: Walls
Type - Pset_QuantityTakeOff - Reference: Generic - 750mm
Type - Pset_ReinforcementBarPitchOfWall - Reference: Generic - 750mm
Type - Pset_WallCommon - IsExternal: no; Reference: Generic - 750mm; AcousticRating: 52 dB; FireRating: EI-60
Pset_QuantityTakeOff - sets with these values: 2
Pset_WallCommon - ExtendToStructure: no; LoadBearing: no
Name (Basic Wall:Generic - 750mm:...)
1045702
1046377

# IfcWallStandardCase: Basic Wall:Generic - 770mm (10)
Type - PredefinedType: STANDARD; Material: _ol.olev sein 770 mm
Type - Pset_ConcreteElementGeneral - FireRating: EI-60
Type - Pset_ElementShading - Roughness: 914.4 mm
Type - Pset_ProductRequirements - Category: Walls
Type - Pset_QuantityTakeOff - Reference: Generic - 770mm
Type - Pset_ReinforcementBarPitchOfWall - Reference: Generic - 770mm
Type - Pset_WallCommon - IsExternal: no; Reference: Generic - 770mm; AcousticRating: 52 dB; FireRating: EI-60
Pset_QuantityTakeOff - sets with these values: 2
Pset_WallCommon - ExtendToStructure: no; LoadBearing: no
Name (Basic Wall:Generic - 770mm:...) | In
777373 | 1 Korrus
783123 | 0 Sokkel
1065658 | 2 Korrus
1065792 | Katus
1073513 | 4 Korrus
1073577 | 4 Korrus
1074240 | 3 Korrus
1074539 | 0 Sokkel
1075477 | 2 Korrus
1078048 | 1 Korrus

# IfcWallStandardCase: Basic Wall:Generic - 790mm (3)
Type - PredefinedType: STANDARD; Material: _ol.olev sein 790 mm
Type - Pset_ConcreteElementGeneral - FireRating: EI-60
Type - Pset_ElementShading - Roughness: 914.4 mm
Type - Pset_ProductRequirements - Category: Walls
Type - Pset_QuantityTakeOff - Reference: Generic - 790mm
Type - Pset_ReinforcementBarPitchOfWall - Reference: Generic - 790mm
Type - Pset_WallCommon - IsExternal: no; Reference: Generic - 790mm; AcousticRating: 52 dB; FireRating: EI-60
Pset_QuantityTakeOff - sets with these values: 2
Pset_WallCommon - ExtendToStructure: no; LoadBearing: no
Name (Basic Wall:Generic - 790mm:...) | In
780614 | 2 Korrus
780788 | 3 Korrus
780848 | 4 Korrus

# IfcWallStandardCase: Basic Wall:SS-00_Bauroc 100mm, Basic Wall:SS-00_Bauroc 100mm:886823
In: 0 Sokkel
Type - PredefinedType: STANDARD; Material: EST. Müüritis. Väikeplokk. Poorbetoonplokk 100 mm
Type - Pset_ElementShading - Roughness: 914.4 mm
Type - Pset_ProductRequirements - Category: Walls
Type - Pset_QuantityTakeOff - Reference: SS-00_Bauroc 100mm
Type - Pset_ReinforcementBarPitchOfWall - Reference: SS-00_Bauroc 100mm
Type - Pset_WallCommon - IsExternal: no; Combustible: yes; Reference: SS-00_Bauroc 100mm
Pset_QuantityTakeOff - sets with these values: 2
Pset_WallCommon - ExtendToStructure: no; LoadBearing: no

# IfcWallStandardCase: Basic Wall:SS-00_Fibo 200mm (5)
Type - PredefinedType: STANDARD; Material: EST. Müüritis. Väikeplokk. Kergkruusplokk 200 mm
Type - Pset_ElementShading - Roughness: 914.4 mm
Type - Pset_ProductRequirements - Category: Walls
Type - Pset_QuantityTakeOff - Reference: SS-00_Fibo 200mm
Type - Pset_ReinforcementBarPitchOfWall - Reference: SS-00_Fibo 200mm
Type - Pset_WallCommon - IsExternal: no; Combustible: yes; Reference: SS-00_Fibo 200mm
Pset_QuantityTakeOff - sets with these values: 2
Pset_WallCommon - ExtendToStructure: no; LoadBearing: no
Name (Basic Wall:SS-00_Fibo 200mm:...) | In
817538 | 1 Korrus
850743 | 2 Korrus
864738 | 3 Korrus
866972 | 4 Korrus
889711 | 0 Sokkel

# IfcWallStandardCase: Basic Wall:SS-00_Fibo 250mm (2)
Type - PredefinedType: STANDARD; Material: EST. Müüritis. Väikeplokk. Kergkruusplokk 250 mm
Type - Pset_ElementShading - Roughness: 914.4 mm
Type - Pset_ProductRequirements - Category: Walls
Type - Pset_QuantityTakeOff - Reference: SS-00_Fibo 250mm
Type - Pset_ReinforcementBarPitchOfWall - Reference: SS-00_Fibo 250mm
Type - Pset_WallCommon - IsExternal: no; Combustible: yes; Reference: SS-00_Fibo 250mm
Pset_QuantityTakeOff - sets with these values: 2
Pset_WallCommon - ExtendToStructure: no; LoadBearing: no
Name (Basic Wall:SS-00_Fibo 250mm:...) | In
850510 | 2 Korrus
864737 | 3 Korrus

# IfcWallStandardCase: Basic Wall:SS-00_Kips, 50mm metallkarkass ühe poolne (12)
In: 0 Sokkel
Type - PredefinedType: STANDARD; Material: EST. Ehitusplaat. Kipsplaat 12.5 mm, EST. Ehitusplaat. Kipsplaat 12.5 mm, EST. Õhkvahe. Roov. Kipsplaadi alusroov. Vertikaalne 50 mm
Type - Pset_ElementShading - Roughness: 914.4 mm
Type - Pset_ProductRequirements - Category: Walls
Type - Pset_QuantityTakeOff - Reference: SS-00_Kips, 50mm metallkarkass ühe poolne
Type - Pset_ReinforcementBarPitchOfWall - Reference: SS-00_Kips, 50mm metallkarkass ühe poolne
Type - Pset_WallCommon - IsExternal: no; Combustible: yes; Reference: SS-00_Kips, 50mm metallkarkass ühe poolne
Pset_QuantityTakeOff - sets with these values: 2
Pset_WallCommon - ExtendToStructure: no; LoadBearing: no
Name (Basic Wall:SS-00_Kips, 50mm metallkarkass ühe poolne:...)
1035597
1036366
1036527
1036570
1320936
1321081
1321109
1321122
1321164
1321177
1321214
1321315

# IfcWallStandardCase: Basic Wall:SS-00_Sauna sein (8)
In: 0 Sokkel
Type - PredefinedType: STANDARD; Material: EST. Fassaadikate. Laudis. Vertikaalne. Default 15 mm, EST. Õhkvahe. Roov. Fassaadikatte alusroov. Vertikaalne 25 mm, EST. Soojustus. Mineraalvill. Default 50 mm
Type - Pset_ElementShading - Roughness: 914.4 mm
Type - Pset_ProductRequirements - Category: Walls
Type - Pset_QuantityTakeOff - Reference: SS-00_Sauna sein
Type - Pset_ReinforcementBarPitchOfWall - Reference: SS-00_Sauna sein
Type - Pset_WallCommon - IsExternal: no; Combustible: no; Reference: SS-00_Sauna sein
Pset_QuantityTakeOff - sets with these values: 2
Pset_WallCommon - ExtendToStructure: no; LoadBearing: no
Name (Basic Wall:SS-00_Sauna sein:...)
882537
882778
882828
882919
883119
883163
883247
883346

# IfcWallStandardCase: Basic Wall:SS-01_ 150mm soklikorruse seinad (18)
In: 0 Sokkel
Type - PredefinedType: STANDARD; Material: EST. Müüritis. Väikeplokk. Kergkruusplokk 150 mm
Type - Pset_ConcreteElementGeneral - FireRating: EI-60
Type - Pset_ElementShading - Roughness: 914.4 mm
Type - Pset_ProductRequirements - Category: Walls
Type - Pset_QuantityTakeOff - Reference: SS-01_ 150mm soklikorruse seinad
Type - Pset_ReinforcementBarPitchOfWall - Reference: SS-01_ 150mm soklikorruse seinad
Type - Pset_WallCommon - IsExternal: no; Combustible: yes; Reference: SS-01_ 150mm soklikorruse seinad; AcousticRating: 42 dB; FireRating: EI-60
Pset_QuantityTakeOff - sets with these values: 2
Pset_WallCommon - ExtendToStructure: no; LoadBearing: no
Name (Basic Wall:SS-01_ 150mm soklikorruse seinad:...)
880460
880993
881069
881193
881304
881439
882993
1037457
1037577
1040851
1040852
1040853
1040863
1041071
1081421
1081861
1081862
1081863

# IfcWallStandardCase: Basic Wall:SS-02_ 100mm šahtide vahesein 2 (16)
Type - PredefinedType: STANDARD; Material: EST. Müüritis. Väikeplokk. Kergkruusplokk 100 mm
Type - Pset_ConcreteElementGeneral - FireRating: EI-60
Type - Pset_ElementShading - Roughness: 914.4 mm
Type - Pset_ProductRequirements - Category: Walls
Type - Pset_QuantityTakeOff - Reference: SS-02_ 100mm šahtide vahesein 2
Type - Pset_ReinforcementBarPitchOfWall - Reference: SS-02_ 100mm šahtide vahesein 2
Type - Pset_WallCommon - IsExternal: no; Combustible: yes; Reference: SS-02_ 100mm šahtide vahesein 2; AcousticRating: 42 dB; FireRating: EI-60
Pset_QuantityTakeOff - sets with these values: 2
Pset_WallCommon - ExtendToStructure: no; LoadBearing: no
Name (Basic Wall:SS-02_ 100mm šahtide vahesein 2:...) | In
818149 | 1 Korrus
1133599 | 2 Korrus
1133843 | 2 Korrus
1134042 | 2 Korrus
1134102 | 2 Korrus
1141290 | 1 Korrus
1141352 | 1 Korrus
1141483 | 1 Korrus
1151243 | 3 Korrus
1151244 | 3 Korrus
1151245 | 3 Korrus
1151246 | 3 Korrus
1151631 | 4 Korrus
1151632 | 4 Korrus
1151633 | 4 Korrus
1151634 | 4 Korrus

# IfcWallStandardCase: Basic Wall:SS-02_ 150mm šahtide vahesein (74)
Type - PredefinedType: STANDARD; Material: EST. Müüritis. Väikeplokk. Kergkruusplokk 150 mm
Type - Pset_ConcreteElementGeneral - FireRating: EI-60
Type - Pset_ElementShading - Roughness: 914.4 mm
Type - Pset_ProductRequirements - Category: Walls
Type - Pset_QuantityTakeOff - Reference: SS-02_ 150mm šahtide vahesein
Type - Pset_ReinforcementBarPitchOfWall - Reference: SS-02_ 150mm šahtide vahesein
Type - Pset_WallCommon - IsExternal: no; Reference: SS-02_ 150mm šahtide vahesein; AcousticRating: 42 dB; FireRating: EI-60; Combustible: yes
Pset_QuantityTakeOff - sets with these values: 2
Pset_WallCommon - LoadBearing: no
Name (Basic Wall:SS-02_ 150mm šahtide vahesein:...) | In | ExtendToStructure
775559 | 1 Korrus | no
775623 | 1 Korrus | no
775712 | 1 Korrus | no
775813 | 1 Korrus | no
775914 | 1 Korrus | no
775972 | 1 Korrus | no
776049 | 1 Korrus | no
776099 | 1 Korrus | no
776126 | 1 Korrus | no
776183 | 1 Korrus | no
776295 | 1 Korrus | no
776327 | 1 Korrus | no
776386 | 1 Korrus | no
776480 | 1 Korrus | no
776532 | 1 Korrus | no
776562 | 1 Korrus | no
776599 | 1 Korrus | no
783112 | 0 Sokkel | no
847579 | 2 Korrus | no
847580 | 2 Korrus | no
847581 | 2 Korrus | no
847582 | 2 Korrus | no
847583 | 2 Korrus | no
847584 | 2 Korrus | no
847585 | 2 Korrus | no
847586 | 2 Korrus | no
847587 | 2 Korrus | no
847588 | 2 Korrus | no
847589 | 2 Korrus | no
847590 | 2 Korrus | no
847591 | 2 Korrus | no
847592 | 2 Korrus | no
847593 | 2 Korrus | no
847594 | 2 Korrus | no
847595 | 2 Korrus | no
847596 | 2 Korrus | no
862870 | 3 Korrus | no
862871 | 3 Korrus | yes
862872 | 3 Korrus | no
862873 | 3 Korrus | no
862874 | 3 Korrus | no
862875 | 3 Korrus | no
862876 | 3 Korrus | no
862877 | 3 Korrus | no
862878 | 3 Korrus | no
862879 | 3 Korrus | no
862880 | 3 Korrus | no
862881 | 3 Korrus | no
862882 | 3 Korrus | no
862883 | 3 Korrus | no
862884 | 3 Korrus | no
862885 | 3 Korrus | no
862886 | 3 Korrus | no
862887 | 3 Korrus | no
866131 | 4 Korrus | no
866132 | 4 Korrus | no
866133 | 4 Korrus | no
866134 | 4 Korrus | no
866135 | 4 Korrus | yes
866136 | 4 Korrus | no
866137 | 4 Korrus | yes
866138 | 4 Korrus | no
866139 | 4 Korrus | no
866140 | 4 Korrus | yes
866141 | 4 Korrus | no
866142 | 4 Korrus | no
866143 | 4 Korrus | no
866144 | 4 Korrus | no
866145 | 4 Korrus | no
866146 | 4 Korrus | yes
866147 | 4 Korrus | no
866148 | 4 Korrus | yes
881788 | 0 Sokkel | no
1050691 | 1 Korrus | no

# IfcWallStandardCase: Basic Wall:SS-03_Fibo 510mm kinnilaotav ava (17)
Type - PredefinedType: STANDARD; Material: EST. Müüritis. Väikeplokk. Kergkruusplokk 510 mm
Type - Pset_ElementShading - Roughness: 914.4 mm
Type - Pset_ProductRequirements - Category: Walls
Type - Pset_QuantityTakeOff - Reference: SS-03_Fibo 510mm kinnilaotav ava
Type - Pset_ReinforcementBarPitchOfWall - Reference: SS-03_Fibo 510mm kinnilaotav ava
Type - Pset_WallCommon - IsExternal: no; Combustible: yes; Reference: SS-03_Fibo 510mm kinnilaotav ava
Pset_QuantityTakeOff - sets with these values: 2
Pset_WallCommon - ExtendToStructure: no; LoadBearing: no
Name (Basic Wall:SS-03_Fibo 510mm kinnilaotav ava:...) | In
819029 | 1 Korrus
850107 | 1 Korrus
851025 | 2 Korrus
851147 | 2 Korrus
851394 | 2 Korrus
852897 | 2 Korrus
864739 | 3 Korrus
864740 | 3 Korrus
864741 | 3 Korrus
864742 | 3 Korrus
866973 | 4 Korrus
866974 | 4 Korrus
866975 | 4 Korrus
866976 | 4 Korrus
882467 | 0 Sokkel
889524 | 0 Sokkel
918939 | 0 Sokkel

# IfcWallStandardCase: Basic Wall:SS-03_Kips, 66mm metallkarkass (36)
Type - PredefinedType: STANDARD; Material: EST. Ehitusplaat. Kipsplaat 12.5 mm, EST. Ehitusplaat. Kipsplaat 12.5 mm, EST. Õhkvahe. Roov. Kipsplaadi alusroov. Vertikaalne 66 mm, EST. Ehitusplaat. Kipsplaat 12.5 mm, EST. Ehitusplaat. Kipsplaat 12.5 mm
Type - Pset_ConcreteElementGeneral - FireRating: EI-60
Type - Pset_ElementShading - Roughness: 914.4 mm
Type - Pset_ProductRequirements - Category: Walls
Type - Pset_QuantityTakeOff - Reference: SS-03_Kips, 66mm metallkarkass
Type - Pset_ReinforcementBarPitchOfWall - Reference: SS-03_Kips, 66mm metallkarkass
Type - Pset_WallCommon - IsExternal: no; Combustible: no; Reference: SS-03_Kips, 66mm metallkarkass; AcousticRating: 48 dB; FireRating: EI-60
Pset_QuantityTakeOff - sets with these values: 2
Pset_WallCommon - LoadBearing: no
Name (Basic Wall:SS-03_Kips, 66mm metallkarkass:...) | In | ExtendToStructure
810437 | 1 Korrus | no
810511 | 1 Korrus | no
828461 | 1 Korrus | no
829469 | 1 Korrus | no
829883 | 1 Korrus | no
831218 | 1 Korrus | no
831359 | 1 Korrus | no
843454 | 1 Korrus | no
843499 | 1 Korrus | no
843557 | 1 Korrus | no
847553 | 2 Korrus | no
847558 | 2 Korrus | no
863621 | 3 Korrus | no
863625 | 3 Korrus | no
863626 | 3 Korrus | no
863629 | 3 Korrus | no
863630 | 3 Korrus | no
863631 | 3 Korrus | no
863632 | 3 Korrus | no
863633 | 3 Korrus | no
863635 | 3 Korrus | no
865923 | 4 Korrus | no
866265 | 4 Korrus | no
866266 | 4 Korrus | no
866269 | 4 Korrus | yes
866270 | 4 Korrus | yes
866273 | 4 Korrus | yes
866274 | 4 Korrus | yes
866275 | 4 Korrus | no
866276 | 4 Korrus | no
866277 | 4 Korrus | no
866279 | 4 Korrus | no
866579 | 3 Korrus | no
866585 | 4 Korrus | no
1102554 | 0 Sokkel | no
1368737 | 1 Korrus | no

# IfcWallStandardCase: Basic Wall:SS-04 - loputuskast (54)
Type - PredefinedType: STANDARD; Material: EST. Põrand. Plaatkate 10 mm, EST. Ehitusplaat. Kipsplaat 12.5 mm, EST. Õhkvahe. Roov. Kipsplaadi alusroov. Vertikaalne 42 mm
Type - Pset_ConcreteElementGeneral - FireRating: -
Type - Pset_ElementShading - Roughness: 914.4 mm
Type - Pset_ProductRequirements - Category: Walls
Type - Pset_QuantityTakeOff - Reference: SS-04 - loputuskast
Type - Pset_ReinforcementBarPitchOfWall - Reference: SS-04 - loputuskast
Type - Pset_WallCommon - IsExternal: no; Combustible: yes; Reference: SS-04 - loputuskast; AcousticRating: -; FireRating: -
Pset_QuantityTakeOff - sets with these values: 2
Pset_WallCommon - ExtendToStructure: no; LoadBearing: no
Name (Basic Wall:SS-04 - loputuskast:...) | In
814754 | 1 Korrus
814798 | 1 Korrus
819933 | 1 Korrus
819967 | 1 Korrus
828680 | 1 Korrus
828681 | 1 Korrus
828852 | 1 Korrus
828853 | 1 Korrus
839616 | 1 Korrus
839681 | 1 Korrus
841173 | 1 Korrus
843471 | 1 Korrus
843472 | 1 Korrus
849627 | 2 Korrus
849628 | 2 Korrus
849631 | 2 Korrus
849632 | 2 Korrus
849633 | 2 Korrus
849634 | 2 Korrus
849635 | 2 Korrus
849636 | 2 Korrus
849637 | 2 Korrus
849640 | 2 Korrus
849641 | 2 Korrus
858208 | 1 Korrus
863673 | 3 Korrus
863674 | 3 Korrus
863675 | 3 Korrus
863676 | 3 Korrus
863677 | 3 Korrus
863678 | 3 Korrus
863679 | 3 Korrus
863680 | 3 Korrus
863681 | 3 Korrus
863682 | 3 Korrus
863683 | 3 Korrus
863687 | 4 Korrus
863688 | 4 Korrus
863689 | 4 Korrus
863690 | 4 Korrus
863691 | 4 Korrus
863692 | 4 Korrus
863693 | 4 Korrus
863694 | 4 Korrus
863695 | 4 Korrus
863696 | 4 Korrus
863697 | 4 Korrus
1087119 | 1 Korrus
1089998 | 2 Korrus
1090001 | 2 Korrus
1090431 | 3 Korrus
1090434 | 3 Korrus
1090472 | 4 Korrus
1090475 | 4 Korrus

# IfcWallStandardCase: Basic Wall:SS-04_Kips, 50+50 mm metallkarkass 2 (52)
Type - PredefinedType: STANDARD; Material: EST. Ehitusplaat. Kipsplaat 12.5 mm, EST. Ehitusplaat. Kipsplaat 12.5 mm, EST. Soojustus. Mineraalvill. Default 50 mm, EST. Ehitusplaat. Kipsplaat 12.5 mm, EST. Soojustus. Mineraalvill. Default 50 mm, EST. Ehitusplaat. Kipsplaat 12.5 mm, EST. Ehitusplaat. Kipsplaat 12.5 mm
Type - Pset_ConcreteElementGeneral - FireRating: EI-60
Type - Pset_ElementShading - Roughness: 914.4 mm
Type - Pset_ProductRequirements - Category: Walls
Type - Pset_QuantityTakeOff - Reference: SS-04_Kips, 50+50 mm metallkarkass 2
Type - Pset_ReinforcementBarPitchOfWall - Reference: SS-04_Kips, 50+50 mm metallkarkass 2
Type - Pset_WallCommon - IsExternal: no; Reference: SS-04_Kips, 50+50 mm metallkarkass 2; AcousticRating: 52 dB; FireRating: EI-60; Combustible: no
Pset_QuantityTakeOff - sets with these values: 2
Pset_WallCommon - LoadBearing: no
Name (Basic Wall:SS-04_Kips, 50+50 mm metallkarkass 2:...) | In | ExtendToStructure
806177 | 1 Korrus | no
809369 | 1 Korrus | no
810786 | 1 Korrus | no
810896 | 1 Korrus | no
810962 | 1 Korrus | no
817686 | 1 Korrus | no
817736 | 1 Korrus | no
818572 | 1 Korrus | no
827500 | 1 Korrus | no
827786 | 1 Korrus | no
827800 | 1 Korrus | no
845232 | 1 Korrus | no
847457 | 2 Korrus | no
847459 | 2 Korrus | no
847462 | 2 Korrus | no
847473 | 2 Korrus | no
847474 | 2 Korrus | no
847484 | 2 Korrus | no
847486 | 2 Korrus | no
847489 | 2 Korrus | no
847509 | 2 Korrus | no
847552 | 2 Korrus | no
859404 | 1 Korrus | no
862791 | 3 Korrus | no
862793 | 3 Korrus | no
862796 | 3 Korrus | no
862806 | 3 Korrus | no
862807 | 3 Korrus | no
862816 | 3 Korrus | no
862818 | 3 Korrus | no
862821 | 3 Korrus | no
863624 | 3 Korrus | no
865115 | 2 Korrus | no
865905 | 4 Korrus | yes
865907 | 4 Korrus | no
865910 | 4 Korrus | yes
865920 | 4 Korrus | yes
865921 | 4 Korrus | no
865930 | 4 Korrus | yes
865932 | 4 Korrus | no
865935 | 4 Korrus | yes
865950 | 4 Korrus | no
865968 | 4 Korrus | no
866268 | 4 Korrus | no
1108191 | 2 Korrus | no
1140862 | 1 Korrus | no
1143742 | 1 Korrus | no
1147410 | 2 Korrus | no
1150129 | 3 Korrus | no
1150760 | 4 Korrus | yes
1151120 | 3 Korrus | no
1151538 | 4 Korrus | yes

# IfcWallStandardCase: Basic Wall:SS-04_Kips, 95mm metallkarkass (13)
Type - PredefinedType: STANDARD; Material: EST. Ehitusplaat. Kipsplaat 12.5 mm, EST. Ehitusplaat. Kipsplaat 12.5 mm, EST. Õhkvahe. Roov. Kipsplaadi alusroov. Vertikaalne 95 mm, EST. Ehitusplaat. Kipsplaat 12.5 mm, EST. Ehitusplaat. Kipsplaat 12.5 mm
Type - Pset_ConcreteElementGeneral - FireRating: EI-60
Type - Pset_ElementShading - Roughness: 914.4 mm
Type - Pset_ProductRequirements - Category: Walls
Type - Pset_QuantityTakeOff - Reference: SS-04_Kips, 95mm metallkarkass
Type - Pset_ReinforcementBarPitchOfWall - Reference: SS-04_Kips, 95mm metallkarkass
Type - Pset_WallCommon - IsExternal: no; Combustible: no; Reference: SS-04_Kips, 95mm metallkarkass; AcousticRating: 52 dB; FireRating: EI-60
Pset_QuantityTakeOff - sets with these values: 2
Pset_WallCommon - LoadBearing: no
Name (Basic Wall:SS-04_Kips, 95mm metallkarkass:...) | In | ExtendToStructure
838566 | 1 Korrus | no
846701 | Sissepääs | no
846753 | Sissepääs | no
846809 | Sissepääs | no
847475 | 2 Korrus | no
862808 | 3 Korrus | no
862848 | 3 Korrus | no
865922 | 4 Korrus | yes
865962 | 4 Korrus | no
900469 | 3 Korrus | no
1090757 | 3 Korrus | no
1091674 | 2 Korrus | no
1101167 | 4 Korrus | no

# IfcWallStandardCase: Basic Wall:SS-05_Kips, 50mm metallkarkass (15)
Type - PredefinedType: STANDARD; Material: EST. Soojustus. Mineraalvill. Default 50 mm, EST. Ehitusplaat. Kipsplaat 12.5 mm
Type - Pset_ConcreteElementGeneral - FireRating: EI-60
Type - Pset_ElementShading - Roughness: 914.4 mm
Type - Pset_ProductRequirements - Category: Walls
Type - Pset_QuantityTakeOff - Reference: SS-05_Kips, 50mm metallkarkass
Type - Pset_ReinforcementBarPitchOfWall - Reference: SS-05_Kips, 50mm metallkarkass
Type - Pset_WallCommon - IsExternal: no; Combustible: no; Reference: SS-05_Kips, 50mm metallkarkass; AcousticRating: 52 dB; FireRating: EI-60
Pset_QuantityTakeOff - sets with these values: 2
Pset_WallCommon - ExtendToStructure: no; LoadBearing: no
Name (Basic Wall:SS-05_Kips, 50mm metallkarkass:...) | In
1040865 | 0 Sokkel
1040866 | 0 Sokkel
1133053 | 2 Korrus
1143991 | 1 Korrus
1150265 | 3 Korrus
1150280 | 4 Korrus
1282953 | 0 Sokkel
1283100 | 0 Sokkel
1283126 | 0 Sokkel
1283353 | 0 Sokkel
1283354 | 0 Sokkel
1283355 | 0 Sokkel
1283388 | 0 Sokkel
1283389 | 0 Sokkel
1283390 | 0 Sokkel

# IfcWallStandardCase: Basic Wall:SS-05_Kips, 50mm metallkarkass 2 (3)
Type - PredefinedType: STANDARD; Material: EST. Õhkvahe. Roov. Kipsplaadi alusroov. Vertikaalne 50 mm, EST. Ehitusplaat. Kipsplaat 12.5 mm, EST. Ehitusplaat. Kipsplaat 12.5 mm
Type - Pset_ConcreteElementGeneral - FireRating: EI-60
Type - Pset_ElementShading - Roughness: 914.4 mm
Type - Pset_ProductRequirements - Category: Walls
Type - Pset_QuantityTakeOff - Reference: SS-05_Kips, 50mm metallkarkass 2
Type - Pset_ReinforcementBarPitchOfWall - Reference: SS-05_Kips, 50mm metallkarkass 2
Type - Pset_WallCommon - IsExternal: no; Combustible: no; Reference: SS-05_Kips, 50mm metallkarkass 2; AcousticRating: 52 dB; FireRating: EI-60
Pset_QuantityTakeOff - sets with these values: 2
Pset_WallCommon - ExtendToStructure: no; LoadBearing: no
Name (Basic Wall:SS-05_Kips, 50mm metallkarkass 2:...) | In
1147534 | 2 Korrus
1151247 | 3 Korrus
1151635 | 4 Korrus

# IfcWallStandardCase: Basic Wall:SS-05_Kips, 66mm metallkarkass (115)
Type - PredefinedType: STANDARD; Material: EST. Ehitusplaat. Kipsplaat 12.5 mm, EST. Ehitusplaat. Kipsplaat 12.5 mm, EST. Soojustus. Mineraalvill. Default 66 mm, EST. Ehitusplaat. Kipsplaat 12.5 mm, EST. Ehitusplaat. Kipsplaat 12.5 mm
Type - Pset_ConcreteElementGeneral - FireRating: EI-60
Type - Pset_ElementShading - Roughness: 914.4 mm
Type - Pset_ProductRequirements - Category: Walls
Type - Pset_QuantityTakeOff - Reference: SS-05_Kips, 66mm metallkarkass
Type - Pset_ReinforcementBarPitchOfWall - Reference: SS-05_Kips, 66mm metallkarkass
Type - Pset_WallCommon - IsExternal: no; Combustible: no; Reference: SS-05_Kips, 66mm metallkarkass; AcousticRating: 52 dB; FireRating: EI-60
Pset_QuantityTakeOff - sets with these values: 2
Pset_WallCommon - LoadBearing: no
Name (Basic Wall:SS-05_Kips, 66mm metallkarkass:...) | In | ExtendToStructure
808341 | 1 Korrus | no
811091 | 1 Korrus | no
811240 | 1 Korrus | no
812245 | 1 Korrus | no
813476 | 1 Korrus | no
818264 | 1 Korrus | no
818273 | 1 Korrus | no
818639 | 1 Korrus | no
818687 | 1 Korrus | no
827697 | 1 Korrus | no
827793 | 1 Korrus | no
827809 | 1 Korrus | no
827820 | 1 Korrus | no
828545 | 1 Korrus | no
835381 | 1 Korrus | no
841683 | 1 Korrus | no
841755 | 1 Korrus | no
847458 | 2 Korrus | no
847464 | 2 Korrus | no
847465 | 2 Korrus | no
847466 | 2 Korrus | no
847469 | 2 Korrus | no
847471 | 2 Korrus | no
847476 | 2 Korrus | no
847478 | 2 Korrus | no
847479 | 2 Korrus | no
847480 | 2 Korrus | no
847481 | 2 Korrus | no
847482 | 2 Korrus | no
847485 | 2 Korrus | no
847487 | 2 Korrus | no
847488 | 2 Korrus | no
847490 | 2 Korrus | no
847493 | 2 Korrus | no
847502 | 2 Korrus | no
847503 | 2 Korrus | no
847505 | 2 Korrus | no
847506 | 2 Korrus | no
847512 | 2 Korrus | no
847548 | 2 Korrus | no
847549 | 2 Korrus | no
847554 | 2 Korrus | no
847555 | 2 Korrus | no
847559 | 2 Korrus | no
847562 | 2 Korrus | no
847563 | 2 Korrus | no
847564 | 2 Korrus | no
848696 | 2 Korrus | no
852493 | 2 Korrus | no
854160 | 2 Korrus | no
855820 | 2 Korrus | no
858436 | 1 Korrus | no
860082 | 2 Korrus | no
862792 | 3 Korrus | no
862797 | 3 Korrus | no
862798 | 3 Korrus | no
862799 | 3 Korrus | no
862802 | 3 Korrus | no
862804 | 3 Korrus | no
862809 | 3 Korrus | no
862810 | 3 Korrus | no
862811 | 3 Korrus | no
862812 | 3 Korrus | no
862813 | 3 Korrus | no
862814 | 3 Korrus | no
862817 | 3 Korrus | no
862819 | 3 Korrus | no
862820 | 3 Korrus | no
862822 | 3 Korrus | no
862824 | 3 Korrus | no
862831 | 3 Korrus | no
862832 | 3 Korrus | no
862834 | 3 Korrus | no
862835 | 3 Korrus | no
862839 | 3 Korrus | no
862844 | 3 Korrus | no
862845 | 3 Korrus | no
862853 | 3 Korrus | no
865906 | 4 Korrus | yes
865911 | 4 Korrus | no
865912 | 4 Korrus | no
865913 | 4 Korrus | yes
865916 | 4 Korrus | yes
865918 | 4 Korrus | yes
865924 | 4 Korrus | yes
865925 | 4 Korrus | yes
865926 | 4 Korrus | no
865927 | 4 Korrus | no
865928 | 4 Korrus | no
865931 | 4 Korrus | no
865933 | 4 Korrus | no
865934 | 4 Korrus | no
865936 | 4 Korrus | yes
865938 | 4 Korrus | no
865945 | 4 Korrus | yes
865948 | 4 Korrus | no
865949 | 4 Korrus | yes
865958 | 4 Korrus | yes
865959 | 4 Korrus | yes
865967 | 4 Korrus | yes
886555 | Sissepääs | no
1065298 | 4 Korrus | yes
1066457 | 1 Korrus | no
1066862 | 0 Sokkel | no
1066887 | 0 Sokkel | no
1066913 | 0 Sokkel | no
1087234 | 1 Korrus | no
1087276 | 1 Korrus | no
1109826 | 2 Korrus | no
1141424 | 1 Korrus | no
1141547 | 1 Korrus | no
1143541 | 1 Korrus | no
1149666 | 3 Korrus | no
1150412 | 4 Korrus | no
1157040 | 1 Korrus | no

# IfcWindow: SMA_W1, 1-jaotus1:A-00_1650x1900 mm, SMA_W1, 1-jaotus1:A-00_1650x1900 mm:1068019
In: 4 Korrus
Type - ParameterTakesPrecedence: no; Sizeable: no; Material: <Unnamed> (2), EST. Klaas. 3x. Default, Default (2)
Type - Pset_ProductRequirements - Category: Windows
Type - Pset_QuantityTakeOff - Reference: A-00_1650x1900 mm
Type - Pset_WindowCommon - IsExternal: no; Reference: A-00_1650x1900 mm; ThermalTransmittance: 0 kg/K/s3
OverallHeight: 1900 mm; OverallWidth: 1600 mm; Material: EST. Klaas. 3x. Default, Default
Pset_DoorWindowGlazingType - SolarHeatGainTransmittance: 0

# IfcWindow: SMA_W1, 1-jaotus1:A-00_1650x1900 mm (3)
Type - ParameterTakesPrecedence: no; Sizeable: no; Material: EST. Klaas. 3x. Default, Default (2), <Unnamed> (2)
Type - Pset_ProductRequirements - Category: Windows
Type - Pset_QuantityTakeOff - Reference: A-00_1650x1900 mm
Type - Pset_WindowCommon - IsExternal: no; Reference: A-00_1650x1900 mm; ThermalTransmittance: 0 kg/K/s3
OverallHeight: 1900 mm; OverallWidth: 1600 mm; Material: EST. Klaas. 3x. Default, Default
Pset_DoorWindowGlazingType - SolarHeatGainTransmittance: 0
Name (SMA_W1, 1-jaotus1:A-00_1650x1900 mm:...) | In
780050 | 2 Korrus
1047985 | 1 Korrus
1068017 | 3 Korrus

# IfcWindow: SMA_W1, 1-jaotus1:A-00_1650x1900 mm kinni (3)
Type - ParameterTakesPrecedence: no; Sizeable: no; Material: <Unnamed> (2), Default (2), EST. Klaas. 3x. Default
Type - Pset_ProductRequirements - Category: Windows
Type - Pset_QuantityTakeOff - Reference: A-00_1650x1900 mm kinni
Type - Pset_WindowCommon - IsExternal: no; ThermalTransmittance: 0 kg/K/s3; Reference: A-00_1650x1900 mm kinni
OverallHeight: 1900 mm; OverallWidth: 1600 mm; Material: Default, EST. Klaas. 3x. Default
Pset_DoorWindowGlazingType - SolarHeatGainTransmittance: 0
Name (SMA_W1, 1-jaotus1:A-00_1650x1900 mm kinni:...) | In
780051 | 2 Korrus
780784 | 3 Korrus
780844 | 4 Korrus

# IfcWindow: SMA_W1, 1-jaotus1:A-00_18000x600 mm (7)
Type - ParameterTakesPrecedence: no; Sizeable: no; Material: <Unnamed> (2), Default (2), EST. Klaas. 3x. Default
Type - Pset_ProductRequirements - Category: Windows
Type - Pset_QuantityTakeOff - Reference: A-00_18000x600 mm
Type - Pset_WindowCommon - IsExternal: no; ThermalTransmittance: 0 kg/K/s3; Reference: A-00_18000x600 mm
OverallHeight: 820 mm; OverallWidth: 1800 mm; Material: EST. Klaas. 3x. Default, Default
Name (SMA_W1, 1-jaotus1:A-00_18000x600 mm:...) | In | Reference | sets with these values
780772 | 3 Korrus | A-00_18000x600 mm | 2
780787 | 3 Korrus | A-00_18000x600 mm | 2
780832 | 4 Korrus | A-00_18000x600 mm | 2
1045942 | 2 Korrus | A-00_18000x600 mm | 2
1045943 | 2 Korrus | A-00_18000x600 mm | 2
1046503 | 1 Korrus | A-00_18000x600 mm | 2
1246395 | 2 Korrus | Pset_DoorWindowGlazingType - SolarHeatGainTransmittance: 0

# IfcWindow: SMA_W1, 1-jaotus1:A-00_1860x750 mm (8)
In: 0 Sokkel
Type - ParameterTakesPrecedence: no; Sizeable: no; Material: <Unnamed> (2), Default (2), EST. Klaas. 3x. Default
Type - Pset_ProductRequirements - Category: Windows
Type - Pset_QuantityTakeOff - Reference: A-00_1860x750 mm
Type - Pset_WindowCommon - IsExternal: no; ThermalTransmittance: 0 kg/K/s3; Reference: A-00_1860x750 mm
OverallHeight: 750 mm; OverallWidth: 1820 mm; Material: EST. Klaas. 3x. Default, Default
Pset_DoorWindowGlazingType - SolarHeatGainTransmittance: 0
Name (SMA_W1, 1-jaotus1:A-00_1860x750 mm:...)
1046378
1046379
1046380
1046381
1046382
1046383
1046384
1046385

# IfcWindow: SMA_W1, 1-jaotus1:A-00_1860x750 mm (6)
In: 0 Sokkel
Type - ParameterTakesPrecedence: no; Sizeable: no; Material: Default (2), <Unnamed> (2), EST. Klaas. 3x. Default
Type - Pset_ProductRequirements - Category: Windows
Type - Pset_QuantityTakeOff - Reference: A-00_1860x750 mm
Type - Pset_WindowCommon - IsExternal: no; ThermalTransmittance: 0 kg/K/s3; Reference: A-00_1860x750 mm
OverallHeight: 750 mm; OverallWidth: 1820 mm; Material: EST. Klaas. 3x. Default, Default
Pset_DoorWindowGlazingType - SolarHeatGainTransmittance: 0
Name (SMA_W1, 1-jaotus1:A-00_1860x750 mm:...)
1081038
1081039
1081040
1081041
1081042
1081043

# IfcWindow: SMA_W1, 1-jaotus1:A-00_950x1450, SMA_W1, 1-jaotus1:A-00_950x1450:878381
In: 0 Sokkel
Type - ParameterTakesPrecedence: no; Sizeable: no; Material: <Unnamed> (2), EST. Klaas. 3x. Default, Default (2)
Type - Pset_ProductRequirements - Category: Windows
Type - Pset_QuantityTakeOff - Reference: A-00_950x1450
Type - Pset_WindowCommon - IsExternal: no; Reference: A-00_950x1450; ThermalTransmittance: 0 kg/K/s3
OverallHeight: 1450 mm; OverallWidth: 950 mm; Material: EST. Klaas. 3x. Default, Default
Pset_OpeningElementCommon - Reference: A-00_950x1450; sets with these values: 2

# IfcWindow: SMA_W1, 1-jaotus1:A-02_1650x1900 mm kinni EI-30, SMA_W1, 1-jaotus1:A-02_1650x1900 mm kinni EI-30:1047986
In: 1 Korrus
Type - ParameterTakesPrecedence: no; Sizeable: no; Material: Default (2), EST. Klaas. 3x. Default, <Unnamed> (2)
Type - Pset_ProductRequirements - Category: Windows
Type - Pset_QuantityTakeOff - Reference: A-02_1650x1900 mm kinni EI-30
Type - Pset_WindowCommon - IsExternal: no; ThermalTransmittance: 0 kg/K/s3; Reference: A-02_1650x1900 mm kinni EI-30; FireRating: EI-30; AcousticRating: 30dB
OverallHeight: 1900 mm; OverallWidth: 1600 mm; Material: Default, EST. Klaas. 3x. Default
Pset_DoorWindowGlazingType - SolarHeatGainTransmittance: 0

# IfcWindow: SMA_W1, 1-jaotus1:A-03_1140x670 (2)
Type - ParameterTakesPrecedence: no; Sizeable: no; Material: <Unnamed> (2), Default (2), EST. Klaas. 3x. Default
Type - Pset_ProductRequirements - Category: Windows
Type - Pset_QuantityTakeOff - Reference: A-03_1140x670
Type - Pset_WindowCommon - IsExternal: no; ThermalTransmittance: 0 kg/K/s3; Reference: A-03_1140x670; FireRating: EI-30; AcousticRating: 30dB
OverallHeight: 670 mm; OverallWidth: 1140 mm; Material: Default, EST. Klaas. 3x. Default
Name (SMA_W1, 1-jaotus1:A-03_1140x670:...) | In
903815 | 2 Korrus | Pset_DoorWindowGlazingType - SolarHeatGainTransmittance: 0
904315 | 3 Korrus | Pset_OpeningElementCommon - Reference: A-03_1140x670; sets with these values: 2

# IfcWindow: SMA_W1, 1-jaotus1:A-03_1140x670, SMA_W1, 1-jaotus1:A-03_1140x670:904301
In: 2 Korrus
Type - ParameterTakesPrecedence: no; Sizeable: no; Material: <Unnamed> (2), EST. Klaas. 3x. Default, Default (2)
Type - Pset_ProductRequirements - Category: Windows
Type - Pset_QuantityTakeOff - Reference: A-03_1140x670
Type - Pset_WindowCommon - IsExternal: no; ThermalTransmittance: 0 kg/K/s3; Reference: A-03_1140x670; FireRating: EI-30; AcousticRating: 30dB
OverallHeight: 670 mm; OverallWidth: 1140 mm; Material: Default, EST. Klaas. 3x. Default
Pset_OpeningElementCommon - Reference: A-03_1140x670; sets with these values: 2

# IfcWindow: SMA_W2, 2-jaotus:A-00 - 19800x1900 (4)
Type - ParameterTakesPrecedence: no; Sizeable: no; Material: Glass, Hall (2), <Unnamed> (2)
Type - Pset_ProductRequirements - Category: Windows
Type - Pset_QuantityTakeOff - Reference: A-00 - 19800x1900
Type - Pset_WindowCommon - IsExternal: no; Reference: A-00 - 19800x1900
OverallHeight: 1300 mm; OverallWidth: 2130 mm; Material: Glass, Hall
Name (SMA_W2, 2-jaotus:A-00 - 19800x1900:...) | In
782989 | 3 Korrus
782990 | 3 Korrus | Pset_OpeningElementCommon - Reference: A-00 - 19800x1900; sets with these values: 2
1044148 | 1 Korrus
1044149 | 1 Korrus | Pset_OpeningElementCommon - Reference: A-00 - 19800x1900; sets with these values: 2

# IfcWindow: SMA_W2, 2-jaotus:A-00 - 19800x1900 (4)
Type - ParameterTakesPrecedence: no; Sizeable: no; Material: Hall (2), Glass, <Unnamed> (2)
Type - Pset_ProductRequirements - Category: Windows
Type - Pset_QuantityTakeOff - Reference: A-00 - 19800x1900
Type - Pset_WindowCommon - IsExternal: no; Reference: A-00 - 19800x1900
OverallHeight: 1300 mm; OverallWidth: 2130 mm; Material: Glass, Hall
Name (SMA_W2, 2-jaotus:A-00 - 19800x1900:...) | In
1044336 | 2 Korrus
1044337 | 2 Korrus
1060018 | 4 Korrus
1060019 | 4 Korrus

# IfcWindow: SMA_W2, 2-jaotus:A-00 - 2100x1300 (2)
Type - ParameterTakesPrecedence: no; Sizeable: no; Material: <Unnamed> (2), Hall (2), Glass
Type - Pset_ProductRequirements - Category: Windows
Type - Pset_QuantityTakeOff - Reference: A-00 - 2100x1300
Type - Pset_WindowCommon - IsExternal: no; Reference: A-00 - 2100x1300
OverallHeight: 1300 mm; OverallWidth: 2050 mm; Material: Glass, Hall
Name (SMA_W2, 2-jaotus:A-00 - 2100x1300:...) | In
780782 | 3 Korrus
1047779 | 1 Korrus

# IfcWindow: SMA_W2, 2-jaotus:A-00 - 2100x1300 (2)
Type - ParameterTakesPrecedence: no; Sizeable: no; Material: Glass, <Unnamed> (2), Hall (2)
Type - Pset_ProductRequirements - Category: Windows
Type - Pset_QuantityTakeOff - Reference: A-00 - 2100x1300
Type - Pset_WindowCommon - IsExternal: no; Reference: A-00 - 2100x1300
OverallHeight: 1300 mm; OverallWidth: 2050 mm; Material: Glass, Hall
Name (SMA_W2, 2-jaotus:A-00 - 2100x1300:...) | In
783577 | 2 Korrus
783579 | 4 Korrus

# IfcWindow: SMA_W2, 2-jaotus:A-00 - 2100x1900 (15)
Type - ParameterTakesPrecedence: no; Sizeable: no; Material: <Unnamed> (2), Hall (2), Glass
Type - Pset_ProductRequirements - Category: Windows
Type - Pset_QuantityTakeOff - Reference: A-00 - 2100x1900
Type - Pset_WindowCommon - IsExternal: no; Reference: A-00 - 2100x1900
OverallHeight: 1950 mm; OverallWidth: 2100 mm; Material: Glass, Hall
Name (SMA_W2, 2-jaotus:A-00 - 2100x1900:...) | In
1045944 | 2 Korrus
1045946 | 2 Korrus
1045950 | 2 Korrus
1046496 | 1 Korrus
1046498 | 1 Korrus
1046500 | 1 Korrus
1046502 | 1 Korrus
1068500 | 4 Korrus
1068551 | 3 Korrus
1068598 | 4 Korrus
1068660 | 3 Korrus
1068710 | 4 Korrus
1068760 | 3 Korrus
1068812 | 4 Korrus
1068860 | 3 Korrus

# IfcWindow: SMA_W2, 2-jaotus:A-00 - 2100x1900 (28)
Type - ParameterTakesPrecedence: no; Sizeable: no; Material: Hall (2), <Unnamed> (2), Glass
Type - Pset_ProductRequirements - Category: Windows
Type - Pset_QuantityTakeOff - Reference: A-00 - 2100x1900
Type - Pset_WindowCommon - IsExternal: no; Reference: A-00 - 2100x1900
OverallHeight: 1950 mm; OverallWidth: 2100 mm; Material: Glass, Hall
Name (SMA_W2, 2-jaotus:A-00 - 2100x1900:...) | In
777538 | 1 Korrus
777559 | 1 Korrus
777601 | 1 Korrus
777643 | 1 Korrus
777686 | 1 Korrus
777728 | 1 Korrus
780775 | 3 Korrus
780776 | 3 Korrus
780777 | 3 Korrus
780778 | 3 Korrus
780779 | 3 Korrus
780780 | 3 Korrus
780781 | 3 Korrus
908363 | 2 Korrus
908364 | 2 Korrus
908365 | 2 Korrus
908366 | 2 Korrus
908367 | 2 Korrus
908368 | 2 Korrus
908394 | 2 Korrus
908459 | 4 Korrus
908460 | 4 Korrus
908461 | 4 Korrus
908462 | 4 Korrus
908463 | 4 Korrus
908464 | 4 Korrus
908499 | 4 Korrus
1045948 | 2 Korrus

# IfcWindow: SMA_W2, 2-jaotus:A-00 - 2100x1900 (16)
Type - ParameterTakesPrecedence: no; Sizeable: no; Material: Hall (2), Glass, <Unnamed> (2)
Type - Pset_ProductRequirements - Category: Windows
Type - Pset_QuantityTakeOff - Reference: A-00 - 2100x1900
Type - Pset_WindowCommon - IsExternal: no; Reference: A-00 - 2100x1900
OverallHeight: 1950 mm; OverallWidth: 2100 mm; Material: Glass, Hall
Name (SMA_W2, 2-jaotus:A-00 - 2100x1900:...) | In
1045945 | 2 Korrus
1045947 | 2 Korrus
1045949 | 2 Korrus
1045951 | 2 Korrus
1046495 | 1 Korrus
1046497 | 1 Korrus
1046499 | 1 Korrus
1046501 | 1 Korrus
1068498 | 3 Korrus
1068553 | 4 Korrus
1068596 | 3 Korrus
1068662 | 4 Korrus
1068708 | 3 Korrus
1068762 | 4 Korrus
1068810 | 3 Korrus
1068862 | 4 Korrus

# IfcWindow: SMA_W2, 2-jaotus:A-01 - 2100x1900, SMA_W2, 2-jaotus:A-01 - 2100x1900:777772
In: 1 Korrus
Type - ParameterTakesPrecedence: no; Sizeable: no; Material: Glass, Hall (2), <Unnamed> (2)
Type - Pset_ProductRequirements - Category: Windows
Type - Pset_QuantityTakeOff - Reference: A-01 - 2100x1900
Type - Pset_WindowCommon - IsExternal: no; Reference: A-01 - 2100x1900; FireRating: EI-30; AcousticRating: 30dB
OverallHeight: 1950 mm; OverallWidth: 2100 mm; Material: Glass, Hall

# IfcWindow: SMA_katuseluuk 1, kuppel:LU-01 - 1000 x 1500 (2)
In: Katus
Type - ParameterTakesPrecedence: no; Sizeable: no; Material: <Unnamed> (6)
Type - Pset_ProductRequirements - Category: Windows
Type - Pset_QuantityTakeOff - Reference: LU-01 - 1000 x 1500
Type - Pset_WindowCommon - IsExternal: no; Reference: LU-01 - 1000 x 1500
OverallHeight: 1441.66 mm; OverallWidth: 1700 mm
Pset_WindowCommon - IsExternal: yes
Name (SMA_katuseluuk 1, kuppel:LU-01 - 1000 x 1500:...)
902371
902504
